VERSION 5.8 ;
BUSBITCHARS "[]" ;
DIVIDERCHAR "/" ;
UNITS
    DATABASE MICRONS 1000 ;
END UNITS

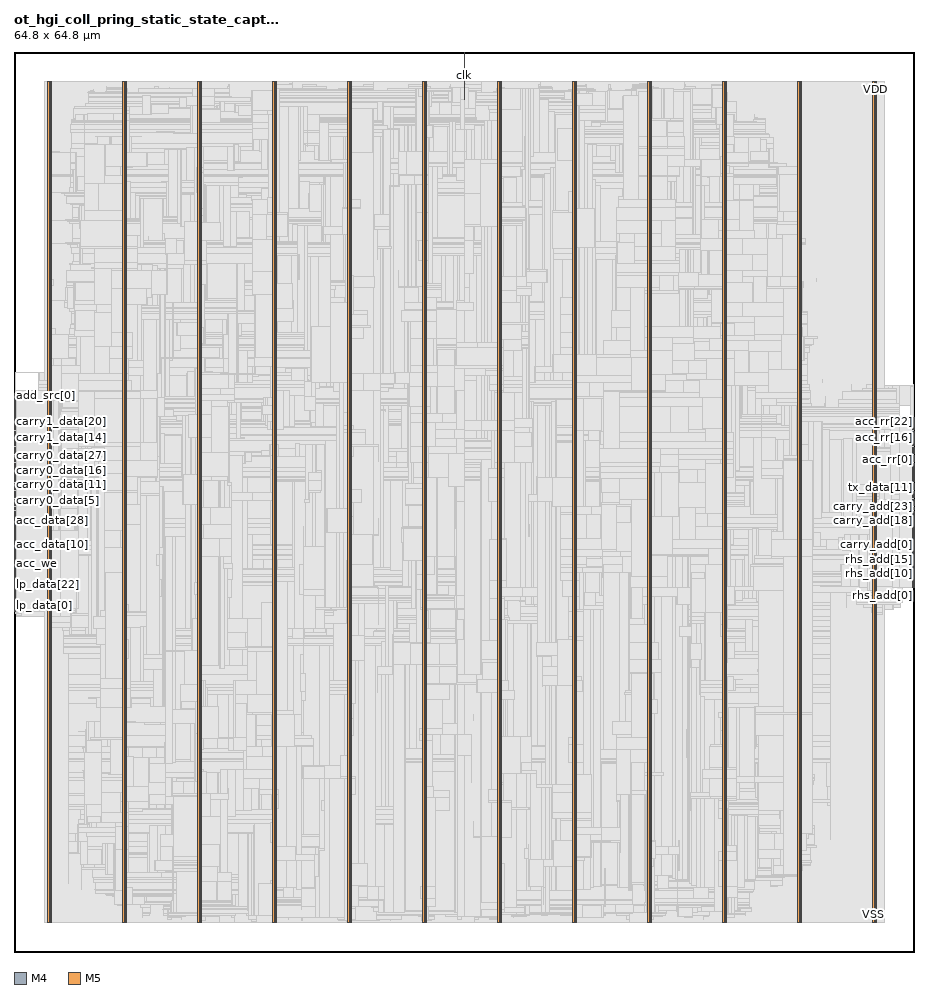
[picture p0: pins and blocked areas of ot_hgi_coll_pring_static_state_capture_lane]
MACRO ot_hgi_coll_pring_static_state_capture_lane
  FOREIGN ot_hgi_coll_pring_static_state_capture_lane 0 0 ;
  CLASS BLOCK ;
  SIZE 64.8 BY 64.8 ;
  PIN acc_data[0]
    DIRECTION INPUT ;
    USE SIGNAL ;
    PORT
      LAYER M4 ;
        RECT  0 28.368 0.084 28.392 ;
    END
  END acc_data[0]
  PIN acc_data[10]
    DIRECTION INPUT ;
    USE SIGNAL ;
    PORT
      LAYER M4 ;
        RECT  0 29.328 0.084 29.352 ;
    END
  END acc_data[10]
  PIN acc_data[11]
    DIRECTION INPUT ;
    USE SIGNAL ;
    PORT
      LAYER M4 ;
        RECT  0 29.424 0.084 29.448 ;
    END
  END acc_data[11]
  PIN acc_data[12]
    DIRECTION INPUT ;
    USE SIGNAL ;
    PORT
      LAYER M4 ;
        RECT  0 29.52 0.084 29.544 ;
    END
  END acc_data[12]
  PIN acc_data[13]
    DIRECTION INPUT ;
    USE SIGNAL ;
    PORT
      LAYER M4 ;
        RECT  0 29.616 0.084 29.64 ;
    END
  END acc_data[13]
  PIN acc_data[14]
    DIRECTION INPUT ;
    USE SIGNAL ;
    PORT
      LAYER M4 ;
        RECT  0 29.712 0.084 29.736 ;
    END
  END acc_data[14]
  PIN acc_data[15]
    DIRECTION INPUT ;
    USE SIGNAL ;
    PORT
      LAYER M4 ;
        RECT  0 29.808 0.084 29.832 ;
    END
  END acc_data[15]
  PIN acc_data[16]
    DIRECTION INPUT ;
    USE SIGNAL ;
    PORT
      LAYER M4 ;
        RECT  0 29.904 0.084 29.928 ;
    END
  END acc_data[16]
  PIN acc_data[17]
    DIRECTION INPUT ;
    USE SIGNAL ;
    PORT
      LAYER M4 ;
        RECT  0 30 0.084 30.024 ;
    END
  END acc_data[17]
  PIN acc_data[18]
    DIRECTION INPUT ;
    USE SIGNAL ;
    PORT
      LAYER M4 ;
        RECT  0 30.096 0.084 30.12 ;
    END
  END acc_data[18]
  PIN acc_data[19]
    DIRECTION INPUT ;
    USE SIGNAL ;
    PORT
      LAYER M4 ;
        RECT  0 30.192 0.084 30.216 ;
    END
  END acc_data[19]
  PIN acc_data[1]
    DIRECTION INPUT ;
    USE SIGNAL ;
    PORT
      LAYER M4 ;
        RECT  0 28.464 0.084 28.488 ;
    END
  END acc_data[1]
  PIN acc_data[20]
    DIRECTION INPUT ;
    USE SIGNAL ;
    PORT
      LAYER M4 ;
        RECT  0 30.288 0.084 30.312 ;
    END
  END acc_data[20]
  PIN acc_data[21]
    DIRECTION INPUT ;
    USE SIGNAL ;
    PORT
      LAYER M4 ;
        RECT  0 30.384 0.084 30.408 ;
    END
  END acc_data[21]
  PIN acc_data[22]
    DIRECTION INPUT ;
    USE SIGNAL ;
    PORT
      LAYER M4 ;
        RECT  0 30.48 0.084 30.504 ;
    END
  END acc_data[22]
  PIN acc_data[23]
    DIRECTION INPUT ;
    USE SIGNAL ;
    PORT
      LAYER M4 ;
        RECT  0 30.576 0.084 30.6 ;
    END
  END acc_data[23]
  PIN acc_data[24]
    DIRECTION INPUT ;
    USE SIGNAL ;
    PORT
      LAYER M4 ;
        RECT  0 30.672 0.084 30.696 ;
    END
  END acc_data[24]
  PIN acc_data[25]
    DIRECTION INPUT ;
    USE SIGNAL ;
    PORT
      LAYER M4 ;
        RECT  0 30.768 0.084 30.792 ;
    END
  END acc_data[25]
  PIN acc_data[26]
    DIRECTION INPUT ;
    USE SIGNAL ;
    PORT
      LAYER M4 ;
        RECT  0 30.864 0.084 30.888 ;
    END
  END acc_data[26]
  PIN acc_data[27]
    DIRECTION INPUT ;
    USE SIGNAL ;
    PORT
      LAYER M4 ;
        RECT  0 30.96 0.084 30.984 ;
    END
  END acc_data[27]
  PIN acc_data[28]
    DIRECTION INPUT ;
    USE SIGNAL ;
    PORT
      LAYER M4 ;
        RECT  0 31.056 0.084 31.08 ;
    END
  END acc_data[28]
  PIN acc_data[29]
    DIRECTION INPUT ;
    USE SIGNAL ;
    PORT
      LAYER M4 ;
        RECT  0 31.152 0.084 31.176 ;
    END
  END acc_data[29]
  PIN acc_data[2]
    DIRECTION INPUT ;
    USE SIGNAL ;
    PORT
      LAYER M4 ;
        RECT  0 28.56 0.084 28.584 ;
    END
  END acc_data[2]
  PIN acc_data[30]
    DIRECTION INPUT ;
    USE SIGNAL ;
    PORT
      LAYER M4 ;
        RECT  0 31.248 0.084 31.272 ;
    END
  END acc_data[30]
  PIN acc_data[31]
    DIRECTION INPUT ;
    USE SIGNAL ;
    PORT
      LAYER M4 ;
        RECT  0 31.344 0.084 31.368 ;
    END
  END acc_data[31]
  PIN acc_data[3]
    DIRECTION INPUT ;
    USE SIGNAL ;
    PORT
      LAYER M4 ;
        RECT  0 28.656 0.084 28.68 ;
    END
  END acc_data[3]
  PIN acc_data[4]
    DIRECTION INPUT ;
    USE SIGNAL ;
    PORT
      LAYER M4 ;
        RECT  0 28.752 0.084 28.776 ;
    END
  END acc_data[4]
  PIN acc_data[5]
    DIRECTION INPUT ;
    USE SIGNAL ;
    PORT
      LAYER M4 ;
        RECT  0 28.848 0.084 28.872 ;
    END
  END acc_data[5]
  PIN acc_data[6]
    DIRECTION INPUT ;
    USE SIGNAL ;
    PORT
      LAYER M4 ;
        RECT  0 28.944 0.084 28.968 ;
    END
  END acc_data[6]
  PIN acc_data[7]
    DIRECTION INPUT ;
    USE SIGNAL ;
    PORT
      LAYER M4 ;
        RECT  0 29.04 0.084 29.064 ;
    END
  END acc_data[7]
  PIN acc_data[8]
    DIRECTION INPUT ;
    USE SIGNAL ;
    PORT
      LAYER M4 ;
        RECT  0 29.136 0.084 29.16 ;
    END
  END acc_data[8]
  PIN acc_data[9]
    DIRECTION INPUT ;
    USE SIGNAL ;
    PORT
      LAYER M4 ;
        RECT  0 29.232 0.084 29.256 ;
    END
  END acc_data[9]
  PIN acc_rr[0]
    DIRECTION OUTPUT ;
    USE SIGNAL ;
    PORT
      LAYER M4 ;
        RECT  64.716 35.472 64.8 35.496 ;
    END
  END acc_rr[0]
  PIN acc_rr[10]
    DIRECTION OUTPUT ;
    USE SIGNAL ;
    PORT
      LAYER M4 ;
        RECT  64.716 36.432 64.8 36.456 ;
    END
  END acc_rr[10]
  PIN acc_rr[11]
    DIRECTION OUTPUT ;
    USE SIGNAL ;
    PORT
      LAYER M4 ;
        RECT  64.716 36.528 64.8 36.552 ;
    END
  END acc_rr[11]
  PIN acc_rr[12]
    DIRECTION OUTPUT ;
    USE SIGNAL ;
    PORT
      LAYER M4 ;
        RECT  64.716 36.624 64.8 36.648 ;
    END
  END acc_rr[12]
  PIN acc_rr[13]
    DIRECTION OUTPUT ;
    USE SIGNAL ;
    PORT
      LAYER M4 ;
        RECT  64.716 36.72 64.8 36.744 ;
    END
  END acc_rr[13]
  PIN acc_rr[14]
    DIRECTION OUTPUT ;
    USE SIGNAL ;
    PORT
      LAYER M4 ;
        RECT  64.716 36.816 64.8 36.84 ;
    END
  END acc_rr[14]
  PIN acc_rr[15]
    DIRECTION OUTPUT ;
    USE SIGNAL ;
    PORT
      LAYER M4 ;
        RECT  64.716 36.912 64.8 36.936 ;
    END
  END acc_rr[15]
  PIN acc_rr[16]
    DIRECTION OUTPUT ;
    USE SIGNAL ;
    PORT
      LAYER M4 ;
        RECT  64.716 37.008 64.8 37.032 ;
    END
  END acc_rr[16]
  PIN acc_rr[17]
    DIRECTION OUTPUT ;
    USE SIGNAL ;
    PORT
      LAYER M4 ;
        RECT  64.716 37.104 64.8 37.128 ;
    END
  END acc_rr[17]
  PIN acc_rr[18]
    DIRECTION OUTPUT ;
    USE SIGNAL ;
    PORT
      LAYER M4 ;
        RECT  64.716 37.2 64.8 37.224 ;
    END
  END acc_rr[18]
  PIN acc_rr[19]
    DIRECTION OUTPUT ;
    USE SIGNAL ;
    PORT
      LAYER M4 ;
        RECT  64.716 37.296 64.8 37.32 ;
    END
  END acc_rr[19]
  PIN acc_rr[1]
    DIRECTION OUTPUT ;
    USE SIGNAL ;
    PORT
      LAYER M4 ;
        RECT  64.716 35.568 64.8 35.592 ;
    END
  END acc_rr[1]
  PIN acc_rr[20]
    DIRECTION OUTPUT ;
    USE SIGNAL ;
    PORT
      LAYER M4 ;
        RECT  64.716 37.392 64.8 37.416 ;
    END
  END acc_rr[20]
  PIN acc_rr[21]
    DIRECTION OUTPUT ;
    USE SIGNAL ;
    PORT
      LAYER M4 ;
        RECT  64.716 37.488 64.8 37.512 ;
    END
  END acc_rr[21]
  PIN acc_rr[22]
    DIRECTION OUTPUT ;
    USE SIGNAL ;
    PORT
      LAYER M4 ;
        RECT  64.716 37.584 64.8 37.608 ;
    END
  END acc_rr[22]
  PIN acc_rr[23]
    DIRECTION OUTPUT ;
    USE SIGNAL ;
    PORT
      LAYER M4 ;
        RECT  64.716 37.68 64.8 37.704 ;
    END
  END acc_rr[23]
  PIN acc_rr[24]
    DIRECTION OUTPUT ;
    USE SIGNAL ;
    PORT
      LAYER M4 ;
        RECT  64.716 37.776 64.8 37.8 ;
    END
  END acc_rr[24]
  PIN acc_rr[25]
    DIRECTION OUTPUT ;
    USE SIGNAL ;
    PORT
      LAYER M4 ;
        RECT  64.716 37.872 64.8 37.896 ;
    END
  END acc_rr[25]
  PIN acc_rr[26]
    DIRECTION OUTPUT ;
    USE SIGNAL ;
    PORT
      LAYER M4 ;
        RECT  64.716 37.968 64.8 37.992 ;
    END
  END acc_rr[26]
  PIN acc_rr[27]
    DIRECTION OUTPUT ;
    USE SIGNAL ;
    PORT
      LAYER M4 ;
        RECT  64.716 38.064 64.8 38.088 ;
    END
  END acc_rr[27]
  PIN acc_rr[28]
    DIRECTION OUTPUT ;
    USE SIGNAL ;
    PORT
      LAYER M4 ;
        RECT  64.716 38.16 64.8 38.184 ;
    END
  END acc_rr[28]
  PIN acc_rr[29]
    DIRECTION OUTPUT ;
    USE SIGNAL ;
    PORT
      LAYER M4 ;
        RECT  64.716 38.256 64.8 38.28 ;
    END
  END acc_rr[29]
  PIN acc_rr[2]
    DIRECTION OUTPUT ;
    USE SIGNAL ;
    PORT
      LAYER M4 ;
        RECT  64.716 35.664 64.8 35.688 ;
    END
  END acc_rr[2]
  PIN acc_rr[30]
    DIRECTION OUTPUT ;
    USE SIGNAL ;
    PORT
      LAYER M4 ;
        RECT  64.716 38.352 64.8 38.376 ;
    END
  END acc_rr[30]
  PIN acc_rr[31]
    DIRECTION OUTPUT ;
    USE SIGNAL ;
    PORT
      LAYER M4 ;
        RECT  64.716 38.448 64.8 38.472 ;
    END
  END acc_rr[31]
  PIN acc_rr[3]
    DIRECTION OUTPUT ;
    USE SIGNAL ;
    PORT
      LAYER M4 ;
        RECT  64.716 35.76 64.8 35.784 ;
    END
  END acc_rr[3]
  PIN acc_rr[4]
    DIRECTION OUTPUT ;
    USE SIGNAL ;
    PORT
      LAYER M4 ;
        RECT  64.716 35.856 64.8 35.88 ;
    END
  END acc_rr[4]
  PIN acc_rr[5]
    DIRECTION OUTPUT ;
    USE SIGNAL ;
    PORT
      LAYER M4 ;
        RECT  64.716 35.952 64.8 35.976 ;
    END
  END acc_rr[5]
  PIN acc_rr[6]
    DIRECTION OUTPUT ;
    USE SIGNAL ;
    PORT
      LAYER M4 ;
        RECT  64.716 36.048 64.8 36.072 ;
    END
  END acc_rr[6]
  PIN acc_rr[7]
    DIRECTION OUTPUT ;
    USE SIGNAL ;
    PORT
      LAYER M4 ;
        RECT  64.716 36.144 64.8 36.168 ;
    END
  END acc_rr[7]
  PIN acc_rr[8]
    DIRECTION OUTPUT ;
    USE SIGNAL ;
    PORT
      LAYER M4 ;
        RECT  64.716 36.24 64.8 36.264 ;
    END
  END acc_rr[8]
  PIN acc_rr[9]
    DIRECTION OUTPUT ;
    USE SIGNAL ;
    PORT
      LAYER M4 ;
        RECT  64.716 36.336 64.8 36.36 ;
    END
  END acc_rr[9]
  PIN acc_tag[0]
    DIRECTION INPUT ;
    USE SIGNAL ;
    PORT
      LAYER M4 ;
        RECT  0 28.08 0.084 28.104 ;
    END
  END acc_tag[0]
  PIN acc_tag[1]
    DIRECTION INPUT ;
    USE SIGNAL ;
    PORT
      LAYER M4 ;
        RECT  0 28.176 0.084 28.2 ;
    END
  END acc_tag[1]
  PIN acc_tag[2]
    DIRECTION INPUT ;
    USE SIGNAL ;
    PORT
      LAYER M4 ;
        RECT  0 28.272 0.084 28.296 ;
    END
  END acc_tag[2]
  PIN acc_we
    DIRECTION INPUT ;
    USE SIGNAL ;
    PORT
      LAYER M4 ;
        RECT  0 27.984 0.084 28.008 ;
    END
  END acc_we
  PIN add_src[0]
    DIRECTION INPUT ;
    USE SIGNAL ;
    PORT
      LAYER M4 ;
        RECT  0 40.08 0.084 40.104 ;
    END
  END add_src[0]
  PIN add_src[1]
    DIRECTION INPUT ;
    USE SIGNAL ;
    PORT
      LAYER M4 ;
        RECT  0 40.176 0.084 40.2 ;
    END
  END add_src[1]
  PIN add_tag[0]
    DIRECTION INPUT ;
    USE SIGNAL ;
    PORT
      LAYER M4 ;
        RECT  0 39.216 0.084 39.24 ;
    END
  END add_tag[0]
  PIN add_tag[1]
    DIRECTION INPUT ;
    USE SIGNAL ;
    PORT
      LAYER M4 ;
        RECT  0 39.312 0.084 39.336 ;
    END
  END add_tag[1]
  PIN add_tag[2]
    DIRECTION INPUT ;
    USE SIGNAL ;
    PORT
      LAYER M4 ;
        RECT  0 39.408 0.084 39.432 ;
    END
  END add_tag[2]
  PIN carry0_data[0]
    DIRECTION INPUT ;
    USE SIGNAL ;
    PORT
      LAYER M4 ;
        RECT  0 32.592 0.084 32.616 ;
    END
  END carry0_data[0]
  PIN carry0_data[10]
    DIRECTION INPUT ;
    USE SIGNAL ;
    PORT
      LAYER M4 ;
        RECT  0 33.552 0.084 33.576 ;
    END
  END carry0_data[10]
  PIN carry0_data[11]
    DIRECTION INPUT ;
    USE SIGNAL ;
    PORT
      LAYER M4 ;
        RECT  0 33.648 0.084 33.672 ;
    END
  END carry0_data[11]
  PIN carry0_data[12]
    DIRECTION INPUT ;
    USE SIGNAL ;
    PORT
      LAYER M4 ;
        RECT  0 33.744 0.084 33.768 ;
    END
  END carry0_data[12]
  PIN carry0_data[13]
    DIRECTION INPUT ;
    USE SIGNAL ;
    PORT
      LAYER M4 ;
        RECT  0 33.84 0.084 33.864 ;
    END
  END carry0_data[13]
  PIN carry0_data[14]
    DIRECTION INPUT ;
    USE SIGNAL ;
    PORT
      LAYER M4 ;
        RECT  0 33.936 0.084 33.96 ;
    END
  END carry0_data[14]
  PIN carry0_data[15]
    DIRECTION INPUT ;
    USE SIGNAL ;
    PORT
      LAYER M4 ;
        RECT  0 34.032 0.084 34.056 ;
    END
  END carry0_data[15]
  PIN carry0_data[16]
    DIRECTION INPUT ;
    USE SIGNAL ;
    PORT
      LAYER M4 ;
        RECT  0 34.128 0.084 34.152 ;
    END
  END carry0_data[16]
  PIN carry0_data[17]
    DIRECTION INPUT ;
    USE SIGNAL ;
    PORT
      LAYER M4 ;
        RECT  0 34.224 0.084 34.248 ;
    END
  END carry0_data[17]
  PIN carry0_data[18]
    DIRECTION INPUT ;
    USE SIGNAL ;
    PORT
      LAYER M4 ;
        RECT  0 34.32 0.084 34.344 ;
    END
  END carry0_data[18]
  PIN carry0_data[19]
    DIRECTION INPUT ;
    USE SIGNAL ;
    PORT
      LAYER M4 ;
        RECT  0 34.416 0.084 34.44 ;
    END
  END carry0_data[19]
  PIN carry0_data[1]
    DIRECTION INPUT ;
    USE SIGNAL ;
    PORT
      LAYER M4 ;
        RECT  0 32.688 0.084 32.712 ;
    END
  END carry0_data[1]
  PIN carry0_data[20]
    DIRECTION INPUT ;
    USE SIGNAL ;
    PORT
      LAYER M4 ;
        RECT  0 34.512 0.084 34.536 ;
    END
  END carry0_data[20]
  PIN carry0_data[21]
    DIRECTION INPUT ;
    USE SIGNAL ;
    PORT
      LAYER M4 ;
        RECT  0 34.608 0.084 34.632 ;
    END
  END carry0_data[21]
  PIN carry0_data[22]
    DIRECTION INPUT ;
    USE SIGNAL ;
    PORT
      LAYER M4 ;
        RECT  0 34.704 0.084 34.728 ;
    END
  END carry0_data[22]
  PIN carry0_data[23]
    DIRECTION INPUT ;
    USE SIGNAL ;
    PORT
      LAYER M4 ;
        RECT  0 34.8 0.084 34.824 ;
    END
  END carry0_data[23]
  PIN carry0_data[24]
    DIRECTION INPUT ;
    USE SIGNAL ;
    PORT
      LAYER M4 ;
        RECT  0 34.896 0.084 34.92 ;
    END
  END carry0_data[24]
  PIN carry0_data[25]
    DIRECTION INPUT ;
    USE SIGNAL ;
    PORT
      LAYER M4 ;
        RECT  0 34.992 0.084 35.016 ;
    END
  END carry0_data[25]
  PIN carry0_data[26]
    DIRECTION INPUT ;
    USE SIGNAL ;
    PORT
      LAYER M4 ;
        RECT  0 35.088 0.084 35.112 ;
    END
  END carry0_data[26]
  PIN carry0_data[27]
    DIRECTION INPUT ;
    USE SIGNAL ;
    PORT
      LAYER M4 ;
        RECT  0 35.184 0.084 35.208 ;
    END
  END carry0_data[27]
  PIN carry0_data[28]
    DIRECTION INPUT ;
    USE SIGNAL ;
    PORT
      LAYER M4 ;
        RECT  0 35.28 0.084 35.304 ;
    END
  END carry0_data[28]
  PIN carry0_data[29]
    DIRECTION INPUT ;
    USE SIGNAL ;
    PORT
      LAYER M4 ;
        RECT  0 35.376 0.084 35.4 ;
    END
  END carry0_data[29]
  PIN carry0_data[2]
    DIRECTION INPUT ;
    USE SIGNAL ;
    PORT
      LAYER M4 ;
        RECT  0 32.784 0.084 32.808 ;
    END
  END carry0_data[2]
  PIN carry0_data[30]
    DIRECTION INPUT ;
    USE SIGNAL ;
    PORT
      LAYER M4 ;
        RECT  0 35.472 0.084 35.496 ;
    END
  END carry0_data[30]
  PIN carry0_data[31]
    DIRECTION INPUT ;
    USE SIGNAL ;
    PORT
      LAYER M4 ;
        RECT  0 35.568 0.084 35.592 ;
    END
  END carry0_data[31]
  PIN carry0_data[3]
    DIRECTION INPUT ;
    USE SIGNAL ;
    PORT
      LAYER M4 ;
        RECT  0 32.88 0.084 32.904 ;
    END
  END carry0_data[3]
  PIN carry0_data[4]
    DIRECTION INPUT ;
    USE SIGNAL ;
    PORT
      LAYER M4 ;
        RECT  0 32.976 0.084 33 ;
    END
  END carry0_data[4]
  PIN carry0_data[5]
    DIRECTION INPUT ;
    USE SIGNAL ;
    PORT
      LAYER M4 ;
        RECT  0 33.072 0.084 33.096 ;
    END
  END carry0_data[5]
  PIN carry0_data[6]
    DIRECTION INPUT ;
    USE SIGNAL ;
    PORT
      LAYER M4 ;
        RECT  0 33.168 0.084 33.192 ;
    END
  END carry0_data[6]
  PIN carry0_data[7]
    DIRECTION INPUT ;
    USE SIGNAL ;
    PORT
      LAYER M4 ;
        RECT  0 33.264 0.084 33.288 ;
    END
  END carry0_data[7]
  PIN carry0_data[8]
    DIRECTION INPUT ;
    USE SIGNAL ;
    PORT
      LAYER M4 ;
        RECT  0 33.36 0.084 33.384 ;
    END
  END carry0_data[8]
  PIN carry0_data[9]
    DIRECTION INPUT ;
    USE SIGNAL ;
    PORT
      LAYER M4 ;
        RECT  0 33.456 0.084 33.48 ;
    END
  END carry0_data[9]
  PIN carry0_src[0]
    DIRECTION INPUT ;
    USE SIGNAL ;
    PORT
      LAYER M4 ;
        RECT  0 32.208 0.084 32.232 ;
    END
  END carry0_src[0]
  PIN carry0_src[1]
    DIRECTION INPUT ;
    USE SIGNAL ;
    PORT
      LAYER M4 ;
        RECT  0 32.304 0.084 32.328 ;
    END
  END carry0_src[1]
  PIN carry0_tag[0]
    DIRECTION INPUT ;
    USE SIGNAL ;
    PORT
      LAYER M4 ;
        RECT  0 31.632 0.084 31.656 ;
    END
  END carry0_tag[0]
  PIN carry0_tag[1]
    DIRECTION INPUT ;
    USE SIGNAL ;
    PORT
      LAYER M4 ;
        RECT  0 31.728 0.084 31.752 ;
    END
  END carry0_tag[1]
  PIN carry0_tag[2]
    DIRECTION INPUT ;
    USE SIGNAL ;
    PORT
      LAYER M4 ;
        RECT  0 31.824 0.084 31.848 ;
    END
  END carry0_tag[2]
  PIN carry1_data[0]
    DIRECTION INPUT ;
    USE SIGNAL ;
    PORT
      LAYER M4 ;
        RECT  0 35.664 0.084 35.688 ;
    END
  END carry1_data[0]
  PIN carry1_data[10]
    DIRECTION INPUT ;
    USE SIGNAL ;
    PORT
      LAYER M4 ;
        RECT  0 36.624 0.084 36.648 ;
    END
  END carry1_data[10]
  PIN carry1_data[11]
    DIRECTION INPUT ;
    USE SIGNAL ;
    PORT
      LAYER M4 ;
        RECT  0 36.72 0.084 36.744 ;
    END
  END carry1_data[11]
  PIN carry1_data[12]
    DIRECTION INPUT ;
    USE SIGNAL ;
    PORT
      LAYER M4 ;
        RECT  0 36.816 0.084 36.84 ;
    END
  END carry1_data[12]
  PIN carry1_data[13]
    DIRECTION INPUT ;
    USE SIGNAL ;
    PORT
      LAYER M4 ;
        RECT  0 36.912 0.084 36.936 ;
    END
  END carry1_data[13]
  PIN carry1_data[14]
    DIRECTION INPUT ;
    USE SIGNAL ;
    PORT
      LAYER M4 ;
        RECT  0 37.008 0.084 37.032 ;
    END
  END carry1_data[14]
  PIN carry1_data[15]
    DIRECTION INPUT ;
    USE SIGNAL ;
    PORT
      LAYER M4 ;
        RECT  0 37.104 0.084 37.128 ;
    END
  END carry1_data[15]
  PIN carry1_data[16]
    DIRECTION INPUT ;
    USE SIGNAL ;
    PORT
      LAYER M4 ;
        RECT  0 37.2 0.084 37.224 ;
    END
  END carry1_data[16]
  PIN carry1_data[17]
    DIRECTION INPUT ;
    USE SIGNAL ;
    PORT
      LAYER M4 ;
        RECT  0 37.296 0.084 37.32 ;
    END
  END carry1_data[17]
  PIN carry1_data[18]
    DIRECTION INPUT ;
    USE SIGNAL ;
    PORT
      LAYER M4 ;
        RECT  0 37.392 0.084 37.416 ;
    END
  END carry1_data[18]
  PIN carry1_data[19]
    DIRECTION INPUT ;
    USE SIGNAL ;
    PORT
      LAYER M4 ;
        RECT  0 37.488 0.084 37.512 ;
    END
  END carry1_data[19]
  PIN carry1_data[1]
    DIRECTION INPUT ;
    USE SIGNAL ;
    PORT
      LAYER M4 ;
        RECT  0 35.76 0.084 35.784 ;
    END
  END carry1_data[1]
  PIN carry1_data[20]
    DIRECTION INPUT ;
    USE SIGNAL ;
    PORT
      LAYER M4 ;
        RECT  0 37.584 0.084 37.608 ;
    END
  END carry1_data[20]
  PIN carry1_data[21]
    DIRECTION INPUT ;
    USE SIGNAL ;
    PORT
      LAYER M4 ;
        RECT  0 37.68 0.084 37.704 ;
    END
  END carry1_data[21]
  PIN carry1_data[22]
    DIRECTION INPUT ;
    USE SIGNAL ;
    PORT
      LAYER M4 ;
        RECT  0 37.776 0.084 37.8 ;
    END
  END carry1_data[22]
  PIN carry1_data[23]
    DIRECTION INPUT ;
    USE SIGNAL ;
    PORT
      LAYER M4 ;
        RECT  0 37.872 0.084 37.896 ;
    END
  END carry1_data[23]
  PIN carry1_data[24]
    DIRECTION INPUT ;
    USE SIGNAL ;
    PORT
      LAYER M4 ;
        RECT  0 37.968 0.084 37.992 ;
    END
  END carry1_data[24]
  PIN carry1_data[25]
    DIRECTION INPUT ;
    USE SIGNAL ;
    PORT
      LAYER M4 ;
        RECT  0 38.064 0.084 38.088 ;
    END
  END carry1_data[25]
  PIN carry1_data[26]
    DIRECTION INPUT ;
    USE SIGNAL ;
    PORT
      LAYER M4 ;
        RECT  0 38.16 0.084 38.184 ;
    END
  END carry1_data[26]
  PIN carry1_data[27]
    DIRECTION INPUT ;
    USE SIGNAL ;
    PORT
      LAYER M4 ;
        RECT  0 38.256 0.084 38.28 ;
    END
  END carry1_data[27]
  PIN carry1_data[28]
    DIRECTION INPUT ;
    USE SIGNAL ;
    PORT
      LAYER M4 ;
        RECT  0 38.352 0.084 38.376 ;
    END
  END carry1_data[28]
  PIN carry1_data[29]
    DIRECTION INPUT ;
    USE SIGNAL ;
    PORT
      LAYER M4 ;
        RECT  0 38.448 0.084 38.472 ;
    END
  END carry1_data[29]
  PIN carry1_data[2]
    DIRECTION INPUT ;
    USE SIGNAL ;
    PORT
      LAYER M4 ;
        RECT  0 35.856 0.084 35.88 ;
    END
  END carry1_data[2]
  PIN carry1_data[30]
    DIRECTION INPUT ;
    USE SIGNAL ;
    PORT
      LAYER M4 ;
        RECT  0 38.544 0.084 38.568 ;
    END
  END carry1_data[30]
  PIN carry1_data[31]
    DIRECTION INPUT ;
    USE SIGNAL ;
    PORT
      LAYER M4 ;
        RECT  0 38.64 0.084 38.664 ;
    END
  END carry1_data[31]
  PIN carry1_data[3]
    DIRECTION INPUT ;
    USE SIGNAL ;
    PORT
      LAYER M4 ;
        RECT  0 35.952 0.084 35.976 ;
    END
  END carry1_data[3]
  PIN carry1_data[4]
    DIRECTION INPUT ;
    USE SIGNAL ;
    PORT
      LAYER M4 ;
        RECT  0 36.048 0.084 36.072 ;
    END
  END carry1_data[4]
  PIN carry1_data[5]
    DIRECTION INPUT ;
    USE SIGNAL ;
    PORT
      LAYER M4 ;
        RECT  0 36.144 0.084 36.168 ;
    END
  END carry1_data[5]
  PIN carry1_data[6]
    DIRECTION INPUT ;
    USE SIGNAL ;
    PORT
      LAYER M4 ;
        RECT  0 36.24 0.084 36.264 ;
    END
  END carry1_data[6]
  PIN carry1_data[7]
    DIRECTION INPUT ;
    USE SIGNAL ;
    PORT
      LAYER M4 ;
        RECT  0 36.336 0.084 36.36 ;
    END
  END carry1_data[7]
  PIN carry1_data[8]
    DIRECTION INPUT ;
    USE SIGNAL ;
    PORT
      LAYER M4 ;
        RECT  0 36.432 0.084 36.456 ;
    END
  END carry1_data[8]
  PIN carry1_data[9]
    DIRECTION INPUT ;
    USE SIGNAL ;
    PORT
      LAYER M4 ;
        RECT  0 36.528 0.084 36.552 ;
    END
  END carry1_data[9]
  PIN carry1_src[0]
    DIRECTION INPUT ;
    USE SIGNAL ;
    PORT
      LAYER M4 ;
        RECT  0 32.4 0.084 32.424 ;
    END
  END carry1_src[0]
  PIN carry1_src[1]
    DIRECTION INPUT ;
    USE SIGNAL ;
    PORT
      LAYER M4 ;
        RECT  0 32.496 0.084 32.52 ;
    END
  END carry1_src[1]
  PIN carry1_tag[0]
    DIRECTION INPUT ;
    USE SIGNAL ;
    PORT
      LAYER M4 ;
        RECT  0 31.92 0.084 31.944 ;
    END
  END carry1_tag[0]
  PIN carry1_tag[1]
    DIRECTION INPUT ;
    USE SIGNAL ;
    PORT
      LAYER M4 ;
        RECT  0 32.016 0.084 32.04 ;
    END
  END carry1_tag[1]
  PIN carry1_tag[2]
    DIRECTION INPUT ;
    USE SIGNAL ;
    PORT
      LAYER M4 ;
        RECT  0 32.112 0.084 32.136 ;
    END
  END carry1_tag[2]
  PIN carry_add[0]
    DIRECTION OUTPUT ;
    USE SIGNAL ;
    PORT
      LAYER M4 ;
        RECT  64.716 29.328 64.8 29.352 ;
    END
  END carry_add[0]
  PIN carry_add[10]
    DIRECTION OUTPUT ;
    USE SIGNAL ;
    PORT
      LAYER M4 ;
        RECT  64.716 30.288 64.8 30.312 ;
    END
  END carry_add[10]
  PIN carry_add[11]
    DIRECTION OUTPUT ;
    USE SIGNAL ;
    PORT
      LAYER M4 ;
        RECT  64.716 30.384 64.8 30.408 ;
    END
  END carry_add[11]
  PIN carry_add[12]
    DIRECTION OUTPUT ;
    USE SIGNAL ;
    PORT
      LAYER M4 ;
        RECT  64.716 30.48 64.8 30.504 ;
    END
  END carry_add[12]
  PIN carry_add[13]
    DIRECTION OUTPUT ;
    USE SIGNAL ;
    PORT
      LAYER M4 ;
        RECT  64.716 30.576 64.8 30.6 ;
    END
  END carry_add[13]
  PIN carry_add[14]
    DIRECTION OUTPUT ;
    USE SIGNAL ;
    PORT
      LAYER M4 ;
        RECT  64.716 30.672 64.8 30.696 ;
    END
  END carry_add[14]
  PIN carry_add[15]
    DIRECTION OUTPUT ;
    USE SIGNAL ;
    PORT
      LAYER M4 ;
        RECT  64.716 30.768 64.8 30.792 ;
    END
  END carry_add[15]
  PIN carry_add[16]
    DIRECTION OUTPUT ;
    USE SIGNAL ;
    PORT
      LAYER M4 ;
        RECT  64.716 30.864 64.8 30.888 ;
    END
  END carry_add[16]
  PIN carry_add[17]
    DIRECTION OUTPUT ;
    USE SIGNAL ;
    PORT
      LAYER M4 ;
        RECT  64.716 30.96 64.8 30.984 ;
    END
  END carry_add[17]
  PIN carry_add[18]
    DIRECTION OUTPUT ;
    USE SIGNAL ;
    PORT
      LAYER M4 ;
        RECT  64.716 31.056 64.8 31.08 ;
    END
  END carry_add[18]
  PIN carry_add[19]
    DIRECTION OUTPUT ;
    USE SIGNAL ;
    PORT
      LAYER M4 ;
        RECT  64.716 31.152 64.8 31.176 ;
    END
  END carry_add[19]
  PIN carry_add[1]
    DIRECTION OUTPUT ;
    USE SIGNAL ;
    PORT
      LAYER M4 ;
        RECT  64.716 29.424 64.8 29.448 ;
    END
  END carry_add[1]
  PIN carry_add[20]
    DIRECTION OUTPUT ;
    USE SIGNAL ;
    PORT
      LAYER M4 ;
        RECT  64.716 31.248 64.8 31.272 ;
    END
  END carry_add[20]
  PIN carry_add[21]
    DIRECTION OUTPUT ;
    USE SIGNAL ;
    PORT
      LAYER M4 ;
        RECT  64.716 31.344 64.8 31.368 ;
    END
  END carry_add[21]
  PIN carry_add[22]
    DIRECTION OUTPUT ;
    USE SIGNAL ;
    PORT
      LAYER M4 ;
        RECT  64.716 31.44 64.8 31.464 ;
    END
  END carry_add[22]
  PIN carry_add[23]
    DIRECTION OUTPUT ;
    USE SIGNAL ;
    PORT
      LAYER M4 ;
        RECT  64.716 31.536 64.8 31.56 ;
    END
  END carry_add[23]
  PIN carry_add[24]
    DIRECTION OUTPUT ;
    USE SIGNAL ;
    PORT
      LAYER M4 ;
        RECT  64.716 31.632 64.8 31.656 ;
    END
  END carry_add[24]
  PIN carry_add[25]
    DIRECTION OUTPUT ;
    USE SIGNAL ;
    PORT
      LAYER M4 ;
        RECT  64.716 31.728 64.8 31.752 ;
    END
  END carry_add[25]
  PIN carry_add[26]
    DIRECTION OUTPUT ;
    USE SIGNAL ;
    PORT
      LAYER M4 ;
        RECT  64.716 31.824 64.8 31.848 ;
    END
  END carry_add[26]
  PIN carry_add[27]
    DIRECTION OUTPUT ;
    USE SIGNAL ;
    PORT
      LAYER M4 ;
        RECT  64.716 31.92 64.8 31.944 ;
    END
  END carry_add[27]
  PIN carry_add[28]
    DIRECTION OUTPUT ;
    USE SIGNAL ;
    PORT
      LAYER M4 ;
        RECT  64.716 32.016 64.8 32.04 ;
    END
  END carry_add[28]
  PIN carry_add[29]
    DIRECTION OUTPUT ;
    USE SIGNAL ;
    PORT
      LAYER M4 ;
        RECT  64.716 32.112 64.8 32.136 ;
    END
  END carry_add[29]
  PIN carry_add[2]
    DIRECTION OUTPUT ;
    USE SIGNAL ;
    PORT
      LAYER M4 ;
        RECT  64.716 29.52 64.8 29.544 ;
    END
  END carry_add[2]
  PIN carry_add[30]
    DIRECTION OUTPUT ;
    USE SIGNAL ;
    PORT
      LAYER M4 ;
        RECT  64.716 32.208 64.8 32.232 ;
    END
  END carry_add[30]
  PIN carry_add[31]
    DIRECTION OUTPUT ;
    USE SIGNAL ;
    PORT
      LAYER M4 ;
        RECT  64.716 32.304 64.8 32.328 ;
    END
  END carry_add[31]
  PIN carry_add[3]
    DIRECTION OUTPUT ;
    USE SIGNAL ;
    PORT
      LAYER M4 ;
        RECT  64.716 29.616 64.8 29.64 ;
    END
  END carry_add[3]
  PIN carry_add[4]
    DIRECTION OUTPUT ;
    USE SIGNAL ;
    PORT
      LAYER M4 ;
        RECT  64.716 29.712 64.8 29.736 ;
    END
  END carry_add[4]
  PIN carry_add[5]
    DIRECTION OUTPUT ;
    USE SIGNAL ;
    PORT
      LAYER M4 ;
        RECT  64.716 29.808 64.8 29.832 ;
    END
  END carry_add[5]
  PIN carry_add[6]
    DIRECTION OUTPUT ;
    USE SIGNAL ;
    PORT
      LAYER M4 ;
        RECT  64.716 29.904 64.8 29.928 ;
    END
  END carry_add[6]
  PIN carry_add[7]
    DIRECTION OUTPUT ;
    USE SIGNAL ;
    PORT
      LAYER M4 ;
        RECT  64.716 30 64.8 30.024 ;
    END
  END carry_add[7]
  PIN carry_add[8]
    DIRECTION OUTPUT ;
    USE SIGNAL ;
    PORT
      LAYER M4 ;
        RECT  64.716 30.096 64.8 30.12 ;
    END
  END carry_add[8]
  PIN carry_add[9]
    DIRECTION OUTPUT ;
    USE SIGNAL ;
    PORT
      LAYER M4 ;
        RECT  64.716 30.192 64.8 30.216 ;
    END
  END carry_add[9]
  PIN carry_we[0]
    DIRECTION INPUT ;
    USE SIGNAL ;
    PORT
      LAYER M4 ;
        RECT  0 31.44 0.084 31.464 ;
    END
  END carry_we[0]
  PIN carry_we[1]
    DIRECTION INPUT ;
    USE SIGNAL ;
    PORT
      LAYER M4 ;
        RECT  0 31.536 0.084 31.56 ;
    END
  END carry_we[1]
  PIN clk
    DIRECTION INPUT ;
    USE SIGNAL ;
    PORT
      LAYER M5 ;
        RECT  32.4 64.716 32.424 64.8 ;
    END
    PORT
      LAYER M5 ;
        RECT  32.4 61.379 32.424 64.784 ;
    END
  END clk
  PIN lp_data[0]
    DIRECTION INPUT ;
    USE SIGNAL ;
    PORT
      LAYER M4 ;
        RECT  0 24.912 0.084 24.936 ;
    END
  END lp_data[0]
  PIN lp_data[10]
    DIRECTION INPUT ;
    USE SIGNAL ;
    PORT
      LAYER M4 ;
        RECT  0 25.872 0.084 25.896 ;
    END
  END lp_data[10]
  PIN lp_data[11]
    DIRECTION INPUT ;
    USE SIGNAL ;
    PORT
      LAYER M4 ;
        RECT  0 25.968 0.084 25.992 ;
    END
  END lp_data[11]
  PIN lp_data[12]
    DIRECTION INPUT ;
    USE SIGNAL ;
    PORT
      LAYER M4 ;
        RECT  0 26.064 0.084 26.088 ;
    END
  END lp_data[12]
  PIN lp_data[13]
    DIRECTION INPUT ;
    USE SIGNAL ;
    PORT
      LAYER M4 ;
        RECT  0 26.16 0.084 26.184 ;
    END
  END lp_data[13]
  PIN lp_data[14]
    DIRECTION INPUT ;
    USE SIGNAL ;
    PORT
      LAYER M4 ;
        RECT  0 26.256 0.084 26.28 ;
    END
  END lp_data[14]
  PIN lp_data[15]
    DIRECTION INPUT ;
    USE SIGNAL ;
    PORT
      LAYER M4 ;
        RECT  0 26.352 0.084 26.376 ;
    END
  END lp_data[15]
  PIN lp_data[16]
    DIRECTION INPUT ;
    USE SIGNAL ;
    PORT
      LAYER M4 ;
        RECT  0 26.448 0.084 26.472 ;
    END
  END lp_data[16]
  PIN lp_data[17]
    DIRECTION INPUT ;
    USE SIGNAL ;
    PORT
      LAYER M4 ;
        RECT  0 26.544 0.084 26.568 ;
    END
  END lp_data[17]
  PIN lp_data[18]
    DIRECTION INPUT ;
    USE SIGNAL ;
    PORT
      LAYER M4 ;
        RECT  0 26.64 0.084 26.664 ;
    END
  END lp_data[18]
  PIN lp_data[19]
    DIRECTION INPUT ;
    USE SIGNAL ;
    PORT
      LAYER M4 ;
        RECT  0 26.736 0.084 26.76 ;
    END
  END lp_data[19]
  PIN lp_data[1]
    DIRECTION INPUT ;
    USE SIGNAL ;
    PORT
      LAYER M4 ;
        RECT  0 25.008 0.084 25.032 ;
    END
  END lp_data[1]
  PIN lp_data[20]
    DIRECTION INPUT ;
    USE SIGNAL ;
    PORT
      LAYER M4 ;
        RECT  0 26.832 0.084 26.856 ;
    END
  END lp_data[20]
  PIN lp_data[21]
    DIRECTION INPUT ;
    USE SIGNAL ;
    PORT
      LAYER M4 ;
        RECT  0 26.928 0.084 26.952 ;
    END
  END lp_data[21]
  PIN lp_data[22]
    DIRECTION INPUT ;
    USE SIGNAL ;
    PORT
      LAYER M4 ;
        RECT  0 27.024 0.084 27.048 ;
    END
  END lp_data[22]
  PIN lp_data[23]
    DIRECTION INPUT ;
    USE SIGNAL ;
    PORT
      LAYER M4 ;
        RECT  0 27.12 0.084 27.144 ;
    END
  END lp_data[23]
  PIN lp_data[24]
    DIRECTION INPUT ;
    USE SIGNAL ;
    PORT
      LAYER M4 ;
        RECT  0 27.216 0.084 27.24 ;
    END
  END lp_data[24]
  PIN lp_data[25]
    DIRECTION INPUT ;
    USE SIGNAL ;
    PORT
      LAYER M4 ;
        RECT  0 27.312 0.084 27.336 ;
    END
  END lp_data[25]
  PIN lp_data[26]
    DIRECTION INPUT ;
    USE SIGNAL ;
    PORT
      LAYER M4 ;
        RECT  0 27.408 0.084 27.432 ;
    END
  END lp_data[26]
  PIN lp_data[27]
    DIRECTION INPUT ;
    USE SIGNAL ;
    PORT
      LAYER M4 ;
        RECT  0 27.504 0.084 27.528 ;
    END
  END lp_data[27]
  PIN lp_data[28]
    DIRECTION INPUT ;
    USE SIGNAL ;
    PORT
      LAYER M4 ;
        RECT  0 27.6 0.084 27.624 ;
    END
  END lp_data[28]
  PIN lp_data[29]
    DIRECTION INPUT ;
    USE SIGNAL ;
    PORT
      LAYER M4 ;
        RECT  0 27.696 0.084 27.72 ;
    END
  END lp_data[29]
  PIN lp_data[2]
    DIRECTION INPUT ;
    USE SIGNAL ;
    PORT
      LAYER M4 ;
        RECT  0 25.104 0.084 25.128 ;
    END
  END lp_data[2]
  PIN lp_data[30]
    DIRECTION INPUT ;
    USE SIGNAL ;
    PORT
      LAYER M4 ;
        RECT  0 27.792 0.084 27.816 ;
    END
  END lp_data[30]
  PIN lp_data[31]
    DIRECTION INPUT ;
    USE SIGNAL ;
    PORT
      LAYER M4 ;
        RECT  0 27.888 0.084 27.912 ;
    END
  END lp_data[31]
  PIN lp_data[3]
    DIRECTION INPUT ;
    USE SIGNAL ;
    PORT
      LAYER M4 ;
        RECT  0 25.2 0.084 25.224 ;
    END
  END lp_data[3]
  PIN lp_data[4]
    DIRECTION INPUT ;
    USE SIGNAL ;
    PORT
      LAYER M4 ;
        RECT  0 25.296 0.084 25.32 ;
    END
  END lp_data[4]
  PIN lp_data[5]
    DIRECTION INPUT ;
    USE SIGNAL ;
    PORT
      LAYER M4 ;
        RECT  0 25.392 0.084 25.416 ;
    END
  END lp_data[5]
  PIN lp_data[6]
    DIRECTION INPUT ;
    USE SIGNAL ;
    PORT
      LAYER M4 ;
        RECT  0 25.488 0.084 25.512 ;
    END
  END lp_data[6]
  PIN lp_data[7]
    DIRECTION INPUT ;
    USE SIGNAL ;
    PORT
      LAYER M4 ;
        RECT  0 25.584 0.084 25.608 ;
    END
  END lp_data[7]
  PIN lp_data[8]
    DIRECTION INPUT ;
    USE SIGNAL ;
    PORT
      LAYER M4 ;
        RECT  0 25.68 0.084 25.704 ;
    END
  END lp_data[8]
  PIN lp_data[9]
    DIRECTION INPUT ;
    USE SIGNAL ;
    PORT
      LAYER M4 ;
        RECT  0 25.776 0.084 25.8 ;
    END
  END lp_data[9]
  PIN lp_tag[0]
    DIRECTION INPUT ;
    USE SIGNAL ;
    PORT
      LAYER M4 ;
        RECT  0 24.624 0.084 24.648 ;
    END
  END lp_tag[0]
  PIN lp_tag[1]
    DIRECTION INPUT ;
    USE SIGNAL ;
    PORT
      LAYER M4 ;
        RECT  0 24.72 0.084 24.744 ;
    END
  END lp_tag[1]
  PIN lp_tag[2]
    DIRECTION INPUT ;
    USE SIGNAL ;
    PORT
      LAYER M4 ;
        RECT  0 24.816 0.084 24.84 ;
    END
  END lp_tag[2]
  PIN lp_we
    DIRECTION INPUT ;
    USE SIGNAL ;
    PORT
      LAYER M4 ;
        RECT  0 24.528 0.084 24.552 ;
    END
  END lp_we
  PIN read_add
    DIRECTION INPUT ;
    USE SIGNAL ;
    PORT
      LAYER M4 ;
        RECT  0 38.736 0.084 38.76 ;
    END
  END read_add
  PIN read_rhs_acc
    DIRECTION INPUT ;
    USE SIGNAL ;
    PORT
      LAYER M4 ;
        RECT  0 39.024 0.084 39.048 ;
    END
  END read_rhs_acc
  PIN read_rr
    DIRECTION INPUT ;
    USE SIGNAL ;
    PORT
      LAYER M4 ;
        RECT  0 38.928 0.084 38.952 ;
    END
  END read_rr
  PIN read_tx
    DIRECTION INPUT ;
    USE SIGNAL ;
    PORT
      LAYER M4 ;
        RECT  0 38.832 0.084 38.856 ;
    END
  END read_tx
  PIN read_tx_acc
    DIRECTION INPUT ;
    USE SIGNAL ;
    PORT
      LAYER M4 ;
        RECT  0 39.12 0.084 39.144 ;
    END
  END read_tx_acc
  PIN rhs_add[0]
    DIRECTION OUTPUT ;
    USE SIGNAL ;
    PORT
      LAYER M4 ;
        RECT  64.716 26.256 64.8 26.28 ;
    END
  END rhs_add[0]
  PIN rhs_add[10]
    DIRECTION OUTPUT ;
    USE SIGNAL ;
    PORT
      LAYER M4 ;
        RECT  64.716 27.216 64.8 27.24 ;
    END
  END rhs_add[10]
  PIN rhs_add[11]
    DIRECTION OUTPUT ;
    USE SIGNAL ;
    PORT
      LAYER M4 ;
        RECT  64.716 27.312 64.8 27.336 ;
    END
  END rhs_add[11]
  PIN rhs_add[12]
    DIRECTION OUTPUT ;
    USE SIGNAL ;
    PORT
      LAYER M4 ;
        RECT  64.716 27.408 64.8 27.432 ;
    END
  END rhs_add[12]
  PIN rhs_add[13]
    DIRECTION OUTPUT ;
    USE SIGNAL ;
    PORT
      LAYER M4 ;
        RECT  64.716 27.504 64.8 27.528 ;
    END
  END rhs_add[13]
  PIN rhs_add[14]
    DIRECTION OUTPUT ;
    USE SIGNAL ;
    PORT
      LAYER M4 ;
        RECT  64.716 27.6 64.8 27.624 ;
    END
  END rhs_add[14]
  PIN rhs_add[15]
    DIRECTION OUTPUT ;
    USE SIGNAL ;
    PORT
      LAYER M4 ;
        RECT  64.716 27.696 64.8 27.72 ;
    END
  END rhs_add[15]
  PIN rhs_add[16]
    DIRECTION OUTPUT ;
    USE SIGNAL ;
    PORT
      LAYER M4 ;
        RECT  64.716 27.792 64.8 27.816 ;
    END
  END rhs_add[16]
  PIN rhs_add[17]
    DIRECTION OUTPUT ;
    USE SIGNAL ;
    PORT
      LAYER M4 ;
        RECT  64.716 27.888 64.8 27.912 ;
    END
  END rhs_add[17]
  PIN rhs_add[18]
    DIRECTION OUTPUT ;
    USE SIGNAL ;
    PORT
      LAYER M4 ;
        RECT  64.716 27.984 64.8 28.008 ;
    END
  END rhs_add[18]
  PIN rhs_add[19]
    DIRECTION OUTPUT ;
    USE SIGNAL ;
    PORT
      LAYER M4 ;
        RECT  64.716 28.08 64.8 28.104 ;
    END
  END rhs_add[19]
  PIN rhs_add[1]
    DIRECTION OUTPUT ;
    USE SIGNAL ;
    PORT
      LAYER M4 ;
        RECT  64.716 26.352 64.8 26.376 ;
    END
  END rhs_add[1]
  PIN rhs_add[20]
    DIRECTION OUTPUT ;
    USE SIGNAL ;
    PORT
      LAYER M4 ;
        RECT  64.716 28.176 64.8 28.2 ;
    END
  END rhs_add[20]
  PIN rhs_add[21]
    DIRECTION OUTPUT ;
    USE SIGNAL ;
    PORT
      LAYER M4 ;
        RECT  64.716 28.272 64.8 28.296 ;
    END
  END rhs_add[21]
  PIN rhs_add[22]
    DIRECTION OUTPUT ;
    USE SIGNAL ;
    PORT
      LAYER M4 ;
        RECT  64.716 28.368 64.8 28.392 ;
    END
  END rhs_add[22]
  PIN rhs_add[23]
    DIRECTION OUTPUT ;
    USE SIGNAL ;
    PORT
      LAYER M4 ;
        RECT  64.716 28.464 64.8 28.488 ;
    END
  END rhs_add[23]
  PIN rhs_add[24]
    DIRECTION OUTPUT ;
    USE SIGNAL ;
    PORT
      LAYER M4 ;
        RECT  64.716 28.56 64.8 28.584 ;
    END
  END rhs_add[24]
  PIN rhs_add[25]
    DIRECTION OUTPUT ;
    USE SIGNAL ;
    PORT
      LAYER M4 ;
        RECT  64.716 28.656 64.8 28.68 ;
    END
  END rhs_add[25]
  PIN rhs_add[26]
    DIRECTION OUTPUT ;
    USE SIGNAL ;
    PORT
      LAYER M4 ;
        RECT  64.716 28.752 64.8 28.776 ;
    END
  END rhs_add[26]
  PIN rhs_add[27]
    DIRECTION OUTPUT ;
    USE SIGNAL ;
    PORT
      LAYER M4 ;
        RECT  64.716 28.848 64.8 28.872 ;
    END
  END rhs_add[27]
  PIN rhs_add[28]
    DIRECTION OUTPUT ;
    USE SIGNAL ;
    PORT
      LAYER M4 ;
        RECT  64.716 28.944 64.8 28.968 ;
    END
  END rhs_add[28]
  PIN rhs_add[29]
    DIRECTION OUTPUT ;
    USE SIGNAL ;
    PORT
      LAYER M4 ;
        RECT  64.716 29.04 64.8 29.064 ;
    END
  END rhs_add[29]
  PIN rhs_add[2]
    DIRECTION OUTPUT ;
    USE SIGNAL ;
    PORT
      LAYER M4 ;
        RECT  64.716 26.448 64.8 26.472 ;
    END
  END rhs_add[2]
  PIN rhs_add[30]
    DIRECTION OUTPUT ;
    USE SIGNAL ;
    PORT
      LAYER M4 ;
        RECT  64.716 29.136 64.8 29.16 ;
    END
  END rhs_add[30]
  PIN rhs_add[31]
    DIRECTION OUTPUT ;
    USE SIGNAL ;
    PORT
      LAYER M4 ;
        RECT  64.716 29.232 64.8 29.256 ;
    END
  END rhs_add[31]
  PIN rhs_add[3]
    DIRECTION OUTPUT ;
    USE SIGNAL ;
    PORT
      LAYER M4 ;
        RECT  64.716 26.544 64.8 26.568 ;
    END
  END rhs_add[3]
  PIN rhs_add[4]
    DIRECTION OUTPUT ;
    USE SIGNAL ;
    PORT
      LAYER M4 ;
        RECT  64.716 26.64 64.8 26.664 ;
    END
  END rhs_add[4]
  PIN rhs_add[5]
    DIRECTION OUTPUT ;
    USE SIGNAL ;
    PORT
      LAYER M4 ;
        RECT  64.716 26.736 64.8 26.76 ;
    END
  END rhs_add[5]
  PIN rhs_add[6]
    DIRECTION OUTPUT ;
    USE SIGNAL ;
    PORT
      LAYER M4 ;
        RECT  64.716 26.832 64.8 26.856 ;
    END
  END rhs_add[6]
  PIN rhs_add[7]
    DIRECTION OUTPUT ;
    USE SIGNAL ;
    PORT
      LAYER M4 ;
        RECT  64.716 26.928 64.8 26.952 ;
    END
  END rhs_add[7]
  PIN rhs_add[8]
    DIRECTION OUTPUT ;
    USE SIGNAL ;
    PORT
      LAYER M4 ;
        RECT  64.716 27.024 64.8 27.048 ;
    END
  END rhs_add[8]
  PIN rhs_add[9]
    DIRECTION OUTPUT ;
    USE SIGNAL ;
    PORT
      LAYER M4 ;
        RECT  64.716 27.12 64.8 27.144 ;
    END
  END rhs_add[9]
  PIN rr_tag[0]
    DIRECTION INPUT ;
    USE SIGNAL ;
    PORT
      LAYER M4 ;
        RECT  0 39.792 0.084 39.816 ;
    END
  END rr_tag[0]
  PIN rr_tag[1]
    DIRECTION INPUT ;
    USE SIGNAL ;
    PORT
      LAYER M4 ;
        RECT  0 39.888 0.084 39.912 ;
    END
  END rr_tag[1]
  PIN rr_tag[2]
    DIRECTION INPUT ;
    USE SIGNAL ;
    PORT
      LAYER M4 ;
        RECT  0 39.984 0.084 40.008 ;
    END
  END rr_tag[2]
  PIN tx_data[0]
    DIRECTION OUTPUT ;
    USE SIGNAL ;
    PORT
      LAYER M4 ;
        RECT  64.716 32.4 64.8 32.424 ;
    END
  END tx_data[0]
  PIN tx_data[10]
    DIRECTION OUTPUT ;
    USE SIGNAL ;
    PORT
      LAYER M4 ;
        RECT  64.716 33.36 64.8 33.384 ;
    END
  END tx_data[10]
  PIN tx_data[11]
    DIRECTION OUTPUT ;
    USE SIGNAL ;
    PORT
      LAYER M4 ;
        RECT  64.716 33.456 64.8 33.48 ;
    END
  END tx_data[11]
  PIN tx_data[12]
    DIRECTION OUTPUT ;
    USE SIGNAL ;
    PORT
      LAYER M4 ;
        RECT  64.716 33.552 64.8 33.576 ;
    END
  END tx_data[12]
  PIN tx_data[13]
    DIRECTION OUTPUT ;
    USE SIGNAL ;
    PORT
      LAYER M4 ;
        RECT  64.716 33.648 64.8 33.672 ;
    END
  END tx_data[13]
  PIN tx_data[14]
    DIRECTION OUTPUT ;
    USE SIGNAL ;
    PORT
      LAYER M4 ;
        RECT  64.716 33.744 64.8 33.768 ;
    END
  END tx_data[14]
  PIN tx_data[15]
    DIRECTION OUTPUT ;
    USE SIGNAL ;
    PORT
      LAYER M4 ;
        RECT  64.716 33.84 64.8 33.864 ;
    END
  END tx_data[15]
  PIN tx_data[16]
    DIRECTION OUTPUT ;
    USE SIGNAL ;
    PORT
      LAYER M4 ;
        RECT  64.716 33.936 64.8 33.96 ;
    END
  END tx_data[16]
  PIN tx_data[17]
    DIRECTION OUTPUT ;
    USE SIGNAL ;
    PORT
      LAYER M4 ;
        RECT  64.716 34.032 64.8 34.056 ;
    END
  END tx_data[17]
  PIN tx_data[18]
    DIRECTION OUTPUT ;
    USE SIGNAL ;
    PORT
      LAYER M4 ;
        RECT  64.716 34.128 64.8 34.152 ;
    END
  END tx_data[18]
  PIN tx_data[19]
    DIRECTION OUTPUT ;
    USE SIGNAL ;
    PORT
      LAYER M4 ;
        RECT  64.716 34.224 64.8 34.248 ;
    END
  END tx_data[19]
  PIN tx_data[1]
    DIRECTION OUTPUT ;
    USE SIGNAL ;
    PORT
      LAYER M4 ;
        RECT  64.716 32.496 64.8 32.52 ;
    END
  END tx_data[1]
  PIN tx_data[20]
    DIRECTION OUTPUT ;
    USE SIGNAL ;
    PORT
      LAYER M4 ;
        RECT  64.716 34.32 64.8 34.344 ;
    END
  END tx_data[20]
  PIN tx_data[21]
    DIRECTION OUTPUT ;
    USE SIGNAL ;
    PORT
      LAYER M4 ;
        RECT  64.716 34.416 64.8 34.44 ;
    END
  END tx_data[21]
  PIN tx_data[22]
    DIRECTION OUTPUT ;
    USE SIGNAL ;
    PORT
      LAYER M4 ;
        RECT  64.716 34.512 64.8 34.536 ;
    END
  END tx_data[22]
  PIN tx_data[23]
    DIRECTION OUTPUT ;
    USE SIGNAL ;
    PORT
      LAYER M4 ;
        RECT  64.716 34.608 64.8 34.632 ;
    END
  END tx_data[23]
  PIN tx_data[24]
    DIRECTION OUTPUT ;
    USE SIGNAL ;
    PORT
      LAYER M4 ;
        RECT  64.716 34.704 64.8 34.728 ;
    END
  END tx_data[24]
  PIN tx_data[25]
    DIRECTION OUTPUT ;
    USE SIGNAL ;
    PORT
      LAYER M4 ;
        RECT  64.716 34.8 64.8 34.824 ;
    END
  END tx_data[25]
  PIN tx_data[26]
    DIRECTION OUTPUT ;
    USE SIGNAL ;
    PORT
      LAYER M4 ;
        RECT  64.716 34.896 64.8 34.92 ;
    END
  END tx_data[26]
  PIN tx_data[27]
    DIRECTION OUTPUT ;
    USE SIGNAL ;
    PORT
      LAYER M4 ;
        RECT  64.716 34.992 64.8 35.016 ;
    END
  END tx_data[27]
  PIN tx_data[28]
    DIRECTION OUTPUT ;
    USE SIGNAL ;
    PORT
      LAYER M4 ;
        RECT  64.716 35.088 64.8 35.112 ;
    END
  END tx_data[28]
  PIN tx_data[29]
    DIRECTION OUTPUT ;
    USE SIGNAL ;
    PORT
      LAYER M4 ;
        RECT  64.716 35.184 64.8 35.208 ;
    END
  END tx_data[29]
  PIN tx_data[2]
    DIRECTION OUTPUT ;
    USE SIGNAL ;
    PORT
      LAYER M4 ;
        RECT  64.716 32.592 64.8 32.616 ;
    END
  END tx_data[2]
  PIN tx_data[30]
    DIRECTION OUTPUT ;
    USE SIGNAL ;
    PORT
      LAYER M4 ;
        RECT  64.716 35.28 64.8 35.304 ;
    END
  END tx_data[30]
  PIN tx_data[31]
    DIRECTION OUTPUT ;
    USE SIGNAL ;
    PORT
      LAYER M4 ;
        RECT  64.716 35.376 64.8 35.4 ;
    END
  END tx_data[31]
  PIN tx_data[3]
    DIRECTION OUTPUT ;
    USE SIGNAL ;
    PORT
      LAYER M4 ;
        RECT  64.716 32.688 64.8 32.712 ;
    END
  END tx_data[3]
  PIN tx_data[4]
    DIRECTION OUTPUT ;
    USE SIGNAL ;
    PORT
      LAYER M4 ;
        RECT  64.716 32.784 64.8 32.808 ;
    END
  END tx_data[4]
  PIN tx_data[5]
    DIRECTION OUTPUT ;
    USE SIGNAL ;
    PORT
      LAYER M4 ;
        RECT  64.716 32.88 64.8 32.904 ;
    END
  END tx_data[5]
  PIN tx_data[6]
    DIRECTION OUTPUT ;
    USE SIGNAL ;
    PORT
      LAYER M4 ;
        RECT  64.716 32.976 64.8 33 ;
    END
  END tx_data[6]
  PIN tx_data[7]
    DIRECTION OUTPUT ;
    USE SIGNAL ;
    PORT
      LAYER M4 ;
        RECT  64.716 33.072 64.8 33.096 ;
    END
  END tx_data[7]
  PIN tx_data[8]
    DIRECTION OUTPUT ;
    USE SIGNAL ;
    PORT
      LAYER M4 ;
        RECT  64.716 33.168 64.8 33.192 ;
    END
  END tx_data[8]
  PIN tx_data[9]
    DIRECTION OUTPUT ;
    USE SIGNAL ;
    PORT
      LAYER M4 ;
        RECT  64.716 33.264 64.8 33.288 ;
    END
  END tx_data[9]
  PIN tx_tag[0]
    DIRECTION INPUT ;
    USE SIGNAL ;
    PORT
      LAYER M4 ;
        RECT  0 39.504 0.084 39.528 ;
    END
  END tx_tag[0]
  PIN tx_tag[1]
    DIRECTION INPUT ;
    USE SIGNAL ;
    PORT
      LAYER M4 ;
        RECT  0 39.6 0.084 39.624 ;
    END
  END tx_tag[1]
  PIN tx_tag[2]
    DIRECTION INPUT ;
    USE SIGNAL ;
    PORT
      LAYER M4 ;
        RECT  0 39.696 0.084 39.72 ;
    END
  END tx_tag[2]
  PIN VSS
    DIRECTION INOUT ;
    USE GROUND ;
    PORT
      LAYER M5 ;
        RECT  61.8 2.137 61.92 62.663 ;
        RECT  56.4 2.137 56.52 62.663 ;
        RECT  51 2.137 51.12 62.663 ;
        RECT  45.6 2.137 45.72 62.663 ;
        RECT  40.2 2.137 40.32 62.663 ;
        RECT  34.8 2.137 34.92 62.663 ;
        RECT  29.4 2.137 29.52 62.663 ;
        RECT  24 2.137 24.12 62.663 ;
        RECT  18.6 2.137 18.72 62.663 ;
        RECT  13.2 2.137 13.32 62.663 ;
        RECT  7.8 2.137 7.92 62.663 ;
        RECT  2.4 2.137 2.52 62.663 ;
    END
  END VSS
  PIN VDD
    DIRECTION INOUT ;
    USE POWER ;
    PORT
      LAYER M5 ;
        RECT  61.992 2.151 62.112 62.649 ;
        RECT  56.592 2.151 56.712 62.649 ;
        RECT  51.192 2.151 51.312 62.649 ;
        RECT  45.792 2.151 45.912 62.649 ;
        RECT  40.392 2.151 40.512 62.649 ;
        RECT  34.992 2.151 35.112 62.649 ;
        RECT  29.592 2.151 29.712 62.649 ;
        RECT  24.192 2.151 24.312 62.649 ;
        RECT  18.792 2.151 18.912 62.649 ;
        RECT  13.392 2.151 13.512 62.649 ;
        RECT  7.992 2.151 8.112 62.649 ;
        RECT  2.592 2.151 2.712 62.649 ;
    END
  END VDD
  # OT_OBS_CLOSED layer=M5 d_um=1.536 added=369
  OBS
    LAYER RVTN ;
     RECT  2.16 2.16 62.64 2.295 ;
     RECT  2.16 2.565 62.64 2.835 ;
     RECT  2.16 3.105 62.64 3.375 ;
     RECT  2.16 3.645 62.64 3.915 ;
     RECT  2.16 4.185 62.64 4.455 ;
     RECT  2.16 4.725 62.64 4.995 ;
     RECT  2.16 5.265 62.64 5.535 ;
     RECT  2.16 5.805 62.64 6.075 ;
     RECT  2.16 6.345 62.64 6.615 ;
     RECT  2.16 6.885 62.64 7.155 ;
     RECT  2.16 7.425 62.64 7.695 ;
     RECT  2.16 7.965 62.64 8.235 ;
     RECT  2.16 8.505 62.64 8.775 ;
     RECT  2.16 9.045 62.64 9.315 ;
     RECT  2.16 9.585 62.64 9.855 ;
     RECT  2.16 10.125 62.64 10.395 ;
     RECT  2.16 10.665 62.64 10.935 ;
     RECT  2.16 11.205 62.64 11.475 ;
     RECT  2.16 11.745 62.64 12.015 ;
     RECT  2.16 12.285 62.64 12.555 ;
     RECT  2.16 12.825 62.64 13.095 ;
     RECT  2.16 13.365 62.64 13.635 ;
     RECT  2.16 13.905 62.64 14.175 ;
     RECT  2.16 14.445 62.64 14.715 ;
     RECT  2.16 14.985 62.64 15.255 ;
     RECT  2.16 15.525 62.64 15.795 ;
     RECT  2.16 16.065 62.64 16.335 ;
     RECT  2.16 16.605 62.64 16.875 ;
     RECT  2.16 17.145 62.64 17.415 ;
     RECT  2.16 17.685 62.64 17.955 ;
     RECT  2.16 18.225 62.64 18.495 ;
     RECT  2.16 18.765 62.64 19.035 ;
     RECT  2.16 19.305 62.64 19.575 ;
     RECT  2.16 19.845 62.64 20.115 ;
     RECT  2.16 20.385 62.64 20.655 ;
     RECT  2.16 20.925 62.64 21.195 ;
     RECT  2.16 21.465 62.64 21.735 ;
     RECT  2.16 22.005 62.64 22.275 ;
     RECT  2.16 22.545 62.64 22.815 ;
     RECT  2.16 23.085 62.64 23.355 ;
     RECT  2.16 23.625 62.64 23.895 ;
     RECT  2.16 24.165 62.64 24.435 ;
     RECT  2.16 24.705 62.64 24.975 ;
     RECT  2.16 25.245 62.64 25.515 ;
     RECT  2.16 25.785 62.64 26.055 ;
     RECT  2.16 26.325 62.64 26.595 ;
     RECT  2.16 26.865 62.64 27.135 ;
     RECT  2.16 27.405 62.64 27.675 ;
     RECT  2.16 27.945 62.64 28.215 ;
     RECT  2.16 28.485 62.64 28.755 ;
     RECT  2.16 29.025 62.64 29.295 ;
     RECT  2.16 29.565 62.64 29.835 ;
     RECT  2.16 30.105 62.64 30.375 ;
     RECT  2.16 30.645 62.64 30.915 ;
     RECT  2.16 31.185 62.64 31.455 ;
     RECT  2.16 31.725 62.64 31.995 ;
     RECT  2.16 32.265 62.64 32.535 ;
     RECT  2.16 32.805 62.64 33.075 ;
     RECT  2.16 33.345 62.64 33.615 ;
     RECT  2.16 33.885 62.64 34.155 ;
     RECT  2.16 34.425 62.64 34.695 ;
     RECT  2.16 34.965 62.64 35.235 ;
     RECT  2.16 35.505 62.64 35.775 ;
     RECT  2.16 36.045 62.64 36.315 ;
     RECT  2.16 36.585 62.64 36.855 ;
     RECT  2.16 37.125 62.64 37.395 ;
     RECT  2.16 37.665 62.64 37.935 ;
     RECT  2.16 38.205 62.64 38.475 ;
     RECT  2.16 38.745 62.64 39.015 ;
     RECT  2.16 39.285 62.64 39.555 ;
     RECT  2.16 39.825 62.64 40.095 ;
     RECT  2.16 40.365 62.64 40.635 ;
     RECT  2.16 40.905 62.64 41.175 ;
     RECT  2.16 41.445 62.64 41.715 ;
     RECT  2.16 41.985 62.64 42.255 ;
     RECT  2.16 42.525 62.64 42.795 ;
     RECT  2.16 43.065 62.64 43.335 ;
     RECT  2.16 43.605 62.64 43.875 ;
     RECT  2.16 44.145 62.64 44.415 ;
     RECT  2.16 44.685 62.64 44.955 ;
     RECT  2.16 45.225 62.64 45.495 ;
     RECT  2.16 45.765 62.64 46.035 ;
     RECT  2.16 46.305 62.64 46.575 ;
     RECT  2.16 46.845 62.64 47.115 ;
     RECT  2.16 47.385 62.64 47.655 ;
     RECT  2.16 47.925 62.64 48.195 ;
     RECT  2.16 48.465 62.64 48.735 ;
     RECT  2.16 49.005 62.64 49.275 ;
     RECT  2.16 49.545 62.64 49.815 ;
     RECT  2.16 50.085 62.64 50.355 ;
     RECT  2.16 50.625 62.64 50.895 ;
     RECT  2.16 51.165 62.64 51.435 ;
     RECT  2.16 51.705 62.64 51.975 ;
     RECT  2.16 52.245 62.64 52.515 ;
     RECT  2.16 52.785 62.64 53.055 ;
     RECT  2.16 53.325 62.64 53.595 ;
     RECT  2.16 53.865 62.64 54.135 ;
     RECT  2.16 54.405 62.64 54.675 ;
     RECT  2.16 54.945 62.64 55.215 ;
     RECT  2.16 55.485 62.64 55.755 ;
     RECT  2.16 56.025 62.64 56.295 ;
     RECT  2.16 56.565 62.64 56.835 ;
     RECT  2.16 57.105 62.64 57.375 ;
     RECT  2.16 57.645 62.64 57.915 ;
     RECT  2.16 58.185 62.64 58.455 ;
     RECT  2.16 58.725 62.64 58.995 ;
     RECT  2.16 59.265 62.64 59.535 ;
     RECT  2.16 59.805 62.64 60.075 ;
     RECT  2.16 60.345 62.64 60.615 ;
     RECT  2.16 60.885 62.64 61.155 ;
     RECT  2.16 61.425 62.64 61.695 ;
     RECT  2.16 61.965 62.64 62.235 ;
     RECT  2.16 62.505 62.64 62.64 ;
    LAYER RVTP ;
     RECT  2.16 2.295 62.64 2.565 ;
     RECT  2.16 2.835 62.64 3.105 ;
     RECT  2.16 3.375 62.64 3.645 ;
     RECT  2.16 3.915 62.64 4.185 ;
     RECT  2.16 4.455 62.64 4.725 ;
     RECT  2.16 4.995 62.64 5.265 ;
     RECT  2.16 5.535 62.64 5.805 ;
     RECT  2.16 6.075 62.64 6.345 ;
     RECT  2.16 6.615 62.64 6.885 ;
     RECT  2.16 7.155 62.64 7.425 ;
     RECT  2.16 7.695 62.64 7.965 ;
     RECT  2.16 8.235 62.64 8.505 ;
     RECT  2.16 8.775 62.64 9.045 ;
     RECT  2.16 9.315 62.64 9.585 ;
     RECT  2.16 9.855 62.64 10.125 ;
     RECT  2.16 10.395 62.64 10.665 ;
     RECT  2.16 10.935 62.64 11.205 ;
     RECT  2.16 11.475 62.64 11.745 ;
     RECT  2.16 12.015 62.64 12.285 ;
     RECT  2.16 12.555 62.64 12.825 ;
     RECT  2.16 13.095 62.64 13.365 ;
     RECT  2.16 13.635 62.64 13.905 ;
     RECT  2.16 14.175 62.64 14.445 ;
     RECT  2.16 14.715 62.64 14.985 ;
     RECT  2.16 15.255 62.64 15.525 ;
     RECT  2.16 15.795 62.64 16.065 ;
     RECT  2.16 16.335 62.64 16.605 ;
     RECT  2.16 16.875 62.64 17.145 ;
     RECT  2.16 17.415 62.64 17.685 ;
     RECT  2.16 17.955 62.64 18.225 ;
     RECT  2.16 18.495 62.64 18.765 ;
     RECT  2.16 19.035 62.64 19.305 ;
     RECT  2.16 19.575 62.64 19.845 ;
     RECT  2.16 20.115 62.64 20.385 ;
     RECT  2.16 20.655 62.64 20.925 ;
     RECT  2.16 21.195 62.64 21.465 ;
     RECT  2.16 21.735 62.64 22.005 ;
     RECT  2.16 22.275 62.64 22.545 ;
     RECT  2.16 22.815 62.64 23.085 ;
     RECT  2.16 23.355 62.64 23.625 ;
     RECT  2.16 23.895 62.64 24.165 ;
     RECT  2.16 24.435 62.64 24.705 ;
     RECT  2.16 24.975 62.64 25.245 ;
     RECT  2.16 25.515 62.64 25.785 ;
     RECT  2.16 26.055 62.64 26.325 ;
     RECT  2.16 26.595 62.64 26.865 ;
     RECT  2.16 27.135 62.64 27.405 ;
     RECT  2.16 27.675 62.64 27.945 ;
     RECT  2.16 28.215 62.64 28.485 ;
     RECT  2.16 28.755 62.64 29.025 ;
     RECT  2.16 29.295 62.64 29.565 ;
     RECT  2.16 29.835 62.64 30.105 ;
     RECT  2.16 30.375 62.64 30.645 ;
     RECT  2.16 30.915 62.64 31.185 ;
     RECT  2.16 31.455 62.64 31.725 ;
     RECT  2.16 31.995 62.64 32.265 ;
     RECT  2.16 32.535 62.64 32.805 ;
     RECT  2.16 33.075 62.64 33.345 ;
     RECT  2.16 33.615 62.64 33.885 ;
     RECT  2.16 34.155 62.64 34.425 ;
     RECT  2.16 34.695 62.64 34.965 ;
     RECT  2.16 35.235 62.64 35.505 ;
     RECT  2.16 35.775 62.64 36.045 ;
     RECT  2.16 36.315 62.64 36.585 ;
     RECT  2.16 36.855 62.64 37.125 ;
     RECT  2.16 37.395 62.64 37.665 ;
     RECT  2.16 37.935 62.64 38.205 ;
     RECT  2.16 38.475 62.64 38.745 ;
     RECT  2.16 39.015 62.64 39.285 ;
     RECT  2.16 39.555 62.64 39.825 ;
     RECT  2.16 40.095 62.64 40.365 ;
     RECT  2.16 40.635 62.64 40.905 ;
     RECT  2.16 41.175 62.64 41.445 ;
     RECT  2.16 41.715 62.64 41.985 ;
     RECT  2.16 42.255 62.64 42.525 ;
     RECT  2.16 42.795 62.64 43.065 ;
     RECT  2.16 43.335 62.64 43.605 ;
     RECT  2.16 43.875 62.64 44.145 ;
     RECT  2.16 44.415 62.64 44.685 ;
     RECT  2.16 44.955 62.64 45.225 ;
     RECT  2.16 45.495 62.64 45.765 ;
     RECT  2.16 46.035 62.64 46.305 ;
     RECT  2.16 46.575 62.64 46.845 ;
     RECT  2.16 47.115 62.64 47.385 ;
     RECT  2.16 47.655 62.64 47.925 ;
     RECT  2.16 48.195 62.64 48.465 ;
     RECT  2.16 48.735 62.64 49.005 ;
     RECT  2.16 49.275 62.64 49.545 ;
     RECT  2.16 49.815 62.64 50.085 ;
     RECT  2.16 50.355 62.64 50.625 ;
     RECT  2.16 50.895 62.64 51.165 ;
     RECT  2.16 51.435 62.64 51.705 ;
     RECT  2.16 51.975 62.64 52.245 ;
     RECT  2.16 52.515 62.64 52.785 ;
     RECT  2.16 53.055 62.64 53.325 ;
     RECT  2.16 53.595 62.64 53.865 ;
     RECT  2.16 54.135 62.64 54.405 ;
     RECT  2.16 54.675 62.64 54.945 ;
     RECT  2.16 55.215 62.64 55.485 ;
     RECT  2.16 55.755 62.64 56.025 ;
     RECT  2.16 56.295 62.64 56.565 ;
     RECT  2.16 56.835 62.64 57.105 ;
     RECT  2.16 57.375 62.64 57.645 ;
     RECT  2.16 57.915 62.64 58.185 ;
     RECT  2.16 58.455 62.64 58.725 ;
     RECT  2.16 58.995 62.64 59.265 ;
     RECT  2.16 59.535 62.64 59.805 ;
     RECT  2.16 60.075 62.64 60.345 ;
     RECT  2.16 60.615 62.64 60.885 ;
     RECT  2.16 61.155 62.64 61.425 ;
     RECT  2.16 61.695 62.64 61.965 ;
     RECT  2.16 62.235 62.64 62.505 ;
    LAYER M1 ;
     RECT  2.16 2.151 62.64 62.649 ;
    LAYER M2 ;
     RECT  0.103 24.48 0.139 24.498 ;
     RECT  0.139 24.408 0.175 24.498 ;
     RECT  0.103 28.422 0.175 28.44 ;
     RECT  0.211 29.61 0.535 29.628 ;
     RECT  0.103 41.724 1.759 41.742 ;
     RECT  1.759 41.112 1.831 41.742 ;
     RECT  0.175 24.138 2.16 24.498 ;
     RECT  0.535 25.56 2.16 25.578 ;
     RECT  0.175 26.604 2.16 26.622 ;
     RECT  0.175 28.26 2.16 28.44 ;
     RECT  0.535 29.61 2.16 29.898 ;
     RECT  0.535 32.238 2.16 32.256 ;
     RECT  0.211 33.048 2.16 33.066 ;
     RECT  0.103 34.47 2.16 34.488 ;
     RECT  1.831 40.644 2.16 41.742 ;
     RECT  2.16 2.151 62.64 62.649 ;
     RECT  62.64 24.678 63.275 28.674 ;
     RECT  62.64 30.384 63.275 40.824 ;
     RECT  63.275 24.678 63.311 28.584 ;
     RECT  63.275 36.018 63.779 40.824 ;
     RECT  63.311 24.786 63.815 28.584 ;
     RECT  63.275 30.384 63.851 35.226 ;
     RECT  63.779 36.018 63.851 38.574 ;
     RECT  63.815 25.182 63.887 28.584 ;
     RECT  63.851 30.69 63.887 32.022 ;
     RECT  63.851 32.778 63.887 35.226 ;
     RECT  63.887 26.028 63.923 28.584 ;
     RECT  63.887 32.778 63.923 33.714 ;
     RECT  63.887 25.182 63.959 25.2 ;
     RECT  63.887 30.726 63.959 31.986 ;
     RECT  63.923 26.298 63.995 28.584 ;
     RECT  63.995 26.298 64.067 28.548 ;
     RECT  64.067 28.026 64.103 28.548 ;
     RECT  64.067 26.298 64.139 26.856 ;
     RECT  63.851 36.018 64.535 38.124 ;
     RECT  63.887 34.938 64.543 35.226 ;
     RECT  64.535 36.018 64.543 37.926 ;
     RECT  64.543 34.938 64.571 37.926 ;
     RECT  62.64 29.574 64.615 29.592 ;
     RECT  63.959 30.726 64.615 31.914 ;
     RECT  63.779 39.33 64.643 40.824 ;
     RECT  64.139 26.298 64.679 26.694 ;
     RECT  64.571 34.938 64.679 35.694 ;
     RECT  64.643 39.33 64.679 39.654 ;
     RECT  63.923 33.426 64.687 33.714 ;
     RECT  64.615 29.574 64.715 31.914 ;
     RECT  64.687 33.426 64.715 33.804 ;
     RECT  64.679 35.676 64.715 35.694 ;
     RECT  64.571 36.522 64.715 37.926 ;
     RECT  64.679 39.33 64.715 39.348 ;
     RECT  64.679 26.298 64.751 26.316 ;
     RECT  64.103 28.53 64.751 28.548 ;
     RECT  64.715 33.786 64.787 33.804 ;
     RECT  64.715 36.522 64.787 36.54 ;
     RECT  64.715 37.908 64.787 37.926 ;
     RECT  64.643 40.806 64.787 40.824 ;
    LAYER M3 ;
     RECT  24.015 2.143 24.105 2.191 ;
     RECT  17.064 2.191 17.082 2.227 ;
     RECT  23.94 2.191 24.105 2.251 ;
     RECT  29.415 2.143 29.505 2.251 ;
     RECT  13.215 2.143 13.305 2.263 ;
     RECT  26.1 2.251 26.118 2.263 ;
     RECT  29.415 2.251 29.79 2.263 ;
     RECT  18.615 2.143 18.705 2.299 ;
     RECT  23.832 2.251 24.105 2.299 ;
     RECT  29.415 2.263 30.006 2.299 ;
     RECT  29.34 2.299 30.078 2.335 ;
     RECT  11.052 2.335 11.07 2.371 ;
     RECT  15.84 2.227 15.858 2.371 ;
     RECT  17.064 2.227 17.442 2.371 ;
     RECT  23.364 2.299 24.105 2.371 ;
     RECT  26.1 2.263 26.298 2.371 ;
     RECT  27.108 2.299 27.126 2.371 ;
     RECT  29.34 2.335 30.222 2.371 ;
     RECT  32.22 2.335 32.238 2.371 ;
     RECT  33.156 2.191 33.174 2.371 ;
     RECT  34.815 2.143 34.905 2.371 ;
     RECT  44.28 2.191 44.298 2.371 ;
     RECT  45.615 2.143 45.705 2.371 ;
     RECT  2.415 2.143 2.505 2.413 ;
     RECT  7.815 2.143 7.905 2.413 ;
     RECT  18.615 2.299 18.774 2.413 ;
     RECT  34.2 2.371 34.905 2.413 ;
     RECT  40.215 2.143 40.305 2.413 ;
     RECT  51.015 2.143 51.105 2.413 ;
     RECT  56.415 2.143 56.505 2.413 ;
     RECT  61.815 2.143 61.905 2.413 ;
     RECT  11.052 2.371 11.322 2.461 ;
     RECT  12.06 2.371 12.078 2.461 ;
     RECT  15.84 2.371 15.894 2.461 ;
     RECT  19.728 2.371 19.746 2.461 ;
     RECT  20.7 2.299 20.79 2.461 ;
     RECT  33.156 2.371 33.462 2.461 ;
     RECT  34.2 2.413 35.097 2.461 ;
     RECT  51.015 2.413 51.297 2.461 ;
     RECT  40.215 2.413 40.497 2.491 ;
     RECT  48.24 2.461 48.258 2.497 ;
     RECT  31.932 2.371 32.238 2.533 ;
     RECT  35.964 2.461 35.982 2.533 ;
     RECT  48.24 2.497 48.87 2.533 ;
     RECT  49.644 2.371 49.662 2.533 ;
     RECT  48.096 2.533 48.87 2.539 ;
     RECT  11.052 2.461 12.078 2.569 ;
     RECT  13.215 2.263 13.77 2.569 ;
     RECT  14.796 2.227 14.814 2.569 ;
     RECT  29.34 2.371 30.294 2.569 ;
     RECT  31.824 2.533 32.238 2.569 ;
     RECT  35.928 2.533 36.882 2.569 ;
     RECT  45.615 2.371 46.062 2.569 ;
     RECT  11.016 2.569 12.33 2.605 ;
     RECT  13.215 2.569 14.814 2.605 ;
     RECT  15.624 2.461 15.894 2.605 ;
     RECT  18.615 2.413 18.897 2.605 ;
     RECT  19.728 2.461 19.782 2.605 ;
     RECT  20.7 2.461 20.862 2.605 ;
     RECT  35.82 2.569 36.882 2.605 ;
     RECT  44.1 2.371 44.298 2.605 ;
     RECT  45.615 2.569 46.674 2.605 ;
     RECT  47.808 2.539 48.87 2.605 ;
     RECT  49.644 2.533 49.986 2.605 ;
     RECT  9.252 2.461 9.27 2.641 ;
     RECT  11.016 2.605 15.966 2.641 ;
     RECT  16.848 2.371 17.442 2.641 ;
     RECT  18.504 2.605 18.897 2.641 ;
     RECT  19.728 2.605 20.862 2.641 ;
     RECT  26.1 2.371 27.882 2.641 ;
     RECT  29.088 2.569 30.294 2.641 ;
     RECT  39.348 2.605 39.366 2.641 ;
     RECT  40.215 2.491 41.202 2.641 ;
     RECT  42.408 2.488 42.426 2.641 ;
     RECT  43.488 2.605 44.298 2.641 ;
     RECT  47.808 2.605 49.986 2.641 ;
     RECT  26.1 2.641 30.294 2.731 ;
     RECT  31.032 2.569 32.238 2.731 ;
     RECT  33.156 2.461 35.097 2.731 ;
     RECT  35.82 2.605 37.134 2.731 ;
     RECT  37.944 2.641 38.43 2.731 ;
     RECT  39.348 2.641 42.606 2.731 ;
     RECT  51.015 2.461 51.894 2.731 ;
     RECT  52.668 2.605 52.686 2.731 ;
     RECT  10.764 2.641 15.966 2.767 ;
     RECT  16.74 2.641 21.906 2.767 ;
     RECT  45.615 2.605 46.926 2.767 ;
     RECT  51.015 2.731 52.686 2.767 ;
     RECT  9.252 2.641 9.738 2.803 ;
     RECT  10.764 2.767 21.906 2.803 ;
     RECT  33.156 2.731 42.606 2.803 ;
     RECT  43.38 2.641 44.334 2.803 ;
     RECT  45.612 2.767 46.926 2.803 ;
     RECT  45.612 2.803 46.962 2.827 ;
     RECT  9.252 2.803 9.81 2.839 ;
     RECT  33.156 2.803 44.55 2.839 ;
     RECT  26.1 2.731 32.238 2.911 ;
     RECT  47.808 2.641 50.094 2.911 ;
     RECT  51.012 2.767 52.686 2.911 ;
     RECT  47.808 2.911 53.118 2.923 ;
     RECT  33.156 2.839 44.586 3.001 ;
     RECT  45.432 2.827 46.962 3.001 ;
     RECT  33.156 3.001 46.962 3.028 ;
     RECT  10.764 2.803 22.482 3.037 ;
     RECT  33.12 3.028 46.962 3.073 ;
     RECT  10.728 3.037 22.482 3.109 ;
     RECT  23.256 2.371 24.57 3.109 ;
     RECT  33.048 3.073 46.962 3.145 ;
     RECT  47.736 2.923 53.118 3.145 ;
     RECT  33.048 3.145 53.118 3.173 ;
     RECT  9.216 2.839 9.81 3.181 ;
     RECT  25.848 2.911 32.238 3.181 ;
     RECT  33.048 3.173 52.974 3.181 ;
     RECT  10.728 3.109 24.57 3.271 ;
     RECT  7.815 2.413 8.097 3.343 ;
     RECT  25.74 3.181 52.974 3.355 ;
     RECT  10.728 3.271 24.606 3.379 ;
     RECT  25.596 3.355 52.974 3.407 ;
     RECT  7.452 3.343 8.097 3.415 ;
     RECT  9.072 3.181 9.81 3.415 ;
     RECT  10.728 3.379 24.642 3.415 ;
     RECT  25.596 3.407 44.586 3.437 ;
     RECT  7.38 3.415 8.097 3.451 ;
     RECT  9.072 3.415 24.714 3.451 ;
     RECT  45.36 3.407 52.974 3.569 ;
     RECT  7.38 3.451 24.714 3.577 ;
     RECT  7.272 3.577 24.714 3.605 ;
     RECT  15.192 3.605 24.714 3.721 ;
     RECT  25.596 3.437 44.55 3.721 ;
     RECT  15.192 3.721 44.55 3.749 ;
     RECT  45.468 3.569 52.974 3.839 ;
     RECT  15.192 3.749 25.434 3.911 ;
     RECT  20.124 3.911 25.434 3.92 ;
     RECT  7.272 3.605 14.418 3.991 ;
     RECT  7.092 3.991 14.418 4.081 ;
     RECT  6.66 4.081 14.418 4.117 ;
     RECT  6.552 4.117 14.418 4.189 ;
     RECT  5.976 4.189 14.418 4.225 ;
     RECT  50.004 3.839 52.974 4.261 ;
     RECT  50.004 4.261 53.154 4.387 ;
     RECT  5.868 4.225 14.418 4.423 ;
     RECT  15.192 3.911 19.386 4.423 ;
     RECT  45.468 3.839 48.906 4.459 ;
     RECT  5.868 4.423 19.386 4.507 ;
     RECT  50.004 4.387 53.226 4.531 ;
     RECT  45.432 4.459 48.906 4.559 ;
     RECT  47.088 4.559 48.906 4.651 ;
     RECT  47.088 4.651 49.158 4.657 ;
     RECT  20.124 3.92 24.642 4.757 ;
     RECT  45.432 4.559 46.35 4.765 ;
     RECT  25.416 3.92 25.434 4.801 ;
     RECT  26.244 3.749 44.55 4.801 ;
     RECT  54.468 4.729 54.954 4.801 ;
     RECT  25.416 4.801 44.55 4.829 ;
     RECT  25.488 4.829 44.55 4.891 ;
     RECT  45.324 4.765 46.35 4.891 ;
     RECT  5.832 4.507 19.386 5.029 ;
     RECT  20.124 4.757 24.606 5.029 ;
     RECT  5.832 5.029 24.606 5.035 ;
     RECT  25.488 4.891 46.35 5.063 ;
     RECT  47.088 4.657 49.266 5.071 ;
     RECT  50.004 4.531 53.334 5.071 ;
     RECT  47.088 5.071 53.334 5.161 ;
     RECT  54.468 4.801 55.35 5.161 ;
     RECT  5.724 5.035 24.606 5.197 ;
     RECT  5.688 5.197 24.606 5.333 ;
     RECT  5.688 5.333 10.602 5.341 ;
     RECT  47.088 5.161 55.35 5.341 ;
     RECT  47.088 5.341 55.458 5.431 ;
     RECT  56.415 2.413 56.697 5.431 ;
     RECT  33.192 5.063 46.35 5.539 ;
     RECT  47.088 5.431 56.697 5.539 ;
     RECT  11.412 5.333 24.606 5.773 ;
     RECT  25.488 5.063 32.346 5.773 ;
     RECT  33.192 5.539 56.697 5.845 ;
     RECT  4.824 4.531 4.842 5.971 ;
     RECT  5.616 5.341 10.602 5.971 ;
     RECT  11.412 5.773 32.346 6.007 ;
     RECT  33.192 5.845 56.79 6.007 ;
     RECT  4.824 5.971 10.602 6.071 ;
     RECT  11.412 6.007 56.79 6.241 ;
     RECT  4.824 6.071 5.022 6.269 ;
     RECT  4.824 6.269 4.842 6.328 ;
     RECT  5.76 6.071 10.602 6.331 ;
     RECT  11.412 6.241 57.366 6.331 ;
     RECT  5.76 6.331 57.366 6.421 ;
     RECT  5.76 6.421 57.438 6.611 ;
     RECT  5.76 6.611 57.366 6.989 ;
     RECT  3.888 4.963 3.906 7.087 ;
     RECT  5.76 6.989 32.886 7.087 ;
     RECT  3.888 7.087 4.59 7.099 ;
     RECT  5.508 7.087 32.886 7.099 ;
     RECT  3.888 7.099 32.886 7.133 ;
     RECT  33.624 6.989 57.366 7.501 ;
     RECT  5.292 7.133 32.886 7.619 ;
     RECT  33.624 7.501 57.798 7.691 ;
     RECT  25.596 7.619 32.886 7.771 ;
     RECT  33.624 7.691 57.654 7.771 ;
     RECT  3.888 7.133 3.906 7.963 ;
     RECT  5.292 7.619 24.714 8.311 ;
     RECT  25.596 7.771 57.654 8.429 ;
     RECT  3.888 7.963 4.482 8.525 ;
     RECT  5.22 8.311 24.714 8.581 ;
     RECT  25.596 8.429 27.558 8.581 ;
     RECT  28.296 8.429 57.654 8.879 ;
     RECT  45.396 8.879 57.654 9.113 ;
     RECT  4.644 8.581 27.558 9.247 ;
     RECT  28.296 8.879 44.658 9.247 ;
     RECT  4.644 9.247 44.658 9.509 ;
     RECT  4.752 9.509 44.658 9.895 ;
     RECT  45.396 9.113 57.402 9.895 ;
     RECT  3.888 8.525 3.906 10.291 ;
     RECT  4.752 9.895 57.402 10.291 ;
     RECT  3.888 10.291 57.402 10.471 ;
     RECT  58.788 8.131 58.806 10.561 ;
     RECT  3.888 10.471 57.51 10.625 ;
     RECT  22.212 10.625 57.51 10.661 ;
     RECT  49.176 10.661 57.51 10.733 ;
     RECT  49.464 10.733 57.51 10.741 ;
     RECT  58.572 10.561 58.806 10.741 ;
     RECT  49.464 10.741 58.806 11.003 ;
     RECT  3.888 10.625 21.15 11.261 ;
     RECT  3.888 11.261 21.114 11.399 ;
     RECT  22.212 10.661 48.438 11.407 ;
     RECT  22.212 11.407 48.654 11.515 ;
     RECT  21.888 11.515 48.654 11.551 ;
     RECT  49.464 11.003 57.474 11.551 ;
     RECT  58.572 11.003 58.806 11.947 ;
     RECT  21.888 11.551 57.474 12.091 ;
     RECT  21.888 12.091 57.582 12.209 ;
     RECT  12.96 11.399 21.114 12.289 ;
     RECT  21.888 12.209 48.474 12.289 ;
     RECT  3.888 11.399 12.222 12.325 ;
     RECT  12.96 12.289 48.474 12.325 ;
     RECT  49.356 12.209 57.582 12.361 ;
     RECT  49.356 12.361 57.654 12.515 ;
     RECT  3.888 12.325 48.474 12.551 ;
     RECT  49.428 12.515 57.654 12.557 ;
     RECT  49.5 12.557 57.654 12.785 ;
     RECT  49.5 12.785 57.438 12.857 ;
     RECT  3.888 12.551 41.49 12.893 ;
     RECT  42.228 12.551 48.474 13.297 ;
     RECT  42.156 13.297 48.474 13.567 ;
     RECT  42.156 13.567 48.618 13.675 ;
     RECT  49.5 12.857 57.402 13.675 ;
     RECT  58.464 11.947 58.806 13.675 ;
     RECT  3.888 12.893 41.274 13.711 ;
     RECT  42.156 13.675 48.69 13.711 ;
     RECT  3.888 13.711 48.69 13.837 ;
     RECT  49.5 13.675 58.806 13.837 ;
     RECT  3.888 13.837 58.806 13.901 ;
     RECT  3.888 13.901 22.05 14.369 ;
     RECT  22.788 13.901 58.806 14.779 ;
     RECT  3.888 14.369 21.762 14.819 ;
     RECT  20.484 14.819 21.762 15.187 ;
     RECT  22.572 14.779 58.806 15.187 ;
     RECT  3.888 14.819 19.746 15.601 ;
     RECT  20.484 15.187 58.806 15.601 ;
     RECT  3.888 15.601 58.806 17.915 ;
     RECT  37.908 17.915 58.806 18.661 ;
     RECT  3.888 17.915 37.026 18.805 ;
     RECT  3.888 18.805 37.062 19.075 ;
     RECT  37.836 18.661 58.806 19.075 ;
     RECT  3.888 19.075 58.806 19.229 ;
     RECT  3.888 19.229 20.502 20.011 ;
     RECT  21.384 19.229 58.806 20.011 ;
     RECT  3.888 20.011 58.806 21.101 ;
     RECT  34.128 21.101 58.806 21.389 ;
     RECT  3.888 21.101 33.246 21.505 ;
     RECT  3.564 21.505 33.246 21.901 ;
     RECT  3.564 21.901 33.354 22.009 ;
     RECT  3.564 22.009 33.462 22.207 ;
     RECT  34.308 21.389 58.806 22.207 ;
     RECT  3.564 22.207 58.806 22.577 ;
     RECT  3.564 22.577 20.034 22.685 ;
     RECT  20.88 22.577 58.806 22.739 ;
     RECT  3.564 22.685 17.838 22.775 ;
     RECT  20.88 22.739 25.002 22.781 ;
     RECT  20.88 22.781 24.75 22.811 ;
     RECT  20.88 22.811 22.518 23.009 ;
     RECT  25.884 22.739 58.806 23.045 ;
     RECT  25.956 23.045 58.806 23.117 ;
     RECT  25.992 23.117 58.806 23.153 ;
     RECT  3.564 22.775 17.802 23.161 ;
     RECT  22.392 23.009 22.518 23.279 ;
     RECT  23.328 22.811 24.75 23.279 ;
     RECT  20.88 23.009 21.546 23.309 ;
     RECT  22.392 23.279 22.482 23.315 ;
     RECT  22.464 23.315 22.482 23.351 ;
     RECT  23.4 23.279 24.642 23.351 ;
     RECT  18.615 22.685 20.034 23.359 ;
     RECT  20.88 23.309 21.222 23.359 ;
     RECT  2.415 2.413 2.697 23.371 ;
     RECT  3.492 23.161 17.802 23.371 ;
     RECT  26.064 23.153 58.806 23.423 ;
     RECT  34.236 23.423 58.806 23.891 ;
     RECT  26.064 23.423 33.39 23.935 ;
     RECT  25.776 23.935 33.39 23.947 ;
     RECT  23.94 23.351 24.642 24.061 ;
     RECT  25.488 23.947 33.39 24.061 ;
     RECT  34.236 23.891 35.694 24.089 ;
     RECT  36.432 23.891 58.806 24.125 ;
     RECT  18.615 23.359 21.222 24.133 ;
     RECT  21.96 24.091 21.978 24.133 ;
     RECT  18.615 24.133 21.978 24.169 ;
     RECT  0.18 24.133 0.198 24.205 ;
     RECT  2.415 23.371 17.802 24.205 ;
     RECT  18.615 24.169 22.302 24.205 ;
     RECT  34.236 24.089 35.622 24.233 ;
     RECT  2.415 24.205 22.302 24.241 ;
     RECT  23.94 24.061 33.39 24.241 ;
     RECT  34.236 24.233 35.55 24.241 ;
     RECT  61.815 2.413 62.097 24.331 ;
     RECT  36.432 24.125 38.718 24.395 ;
     RECT  0.18 24.205 0.558 24.403 ;
     RECT  0.144 24.403 0.558 24.475 ;
     RECT  2.415 24.241 22.986 24.475 ;
     RECT  61.815 24.331 62.55 24.475 ;
     RECT  2.376 24.475 22.986 24.601 ;
     RECT  39.456 24.125 58.806 24.665 ;
     RECT  23.94 24.241 35.55 24.701 ;
     RECT  2.376 24.601 23.202 24.709 ;
     RECT  23.94 24.701 31.734 24.709 ;
     RECT  61.74 24.475 62.55 24.781 ;
     RECT  63.288 24.673 63.306 24.781 ;
     RECT  36.432 24.395 38.502 24.899 ;
     RECT  0.108 24.475 0.558 24.941 ;
     RECT  39.6 24.665 58.806 24.971 ;
     RECT  61.164 24.781 62.55 25.051 ;
     RECT  63.288 24.781 63.81 25.051 ;
     RECT  41.832 24.971 58.806 25.169 ;
     RECT  60.66 25.051 63.81 25.177 ;
     RECT  38.268 24.899 38.502 25.213 ;
     RECT  0.324 24.941 0.558 25.229 ;
     RECT  36.432 24.899 37.458 25.249 ;
     RECT  2.376 24.709 31.734 25.285 ;
     RECT  2.304 25.285 31.734 25.339 ;
     RECT  36.396 25.249 37.458 25.349 ;
     RECT  38.268 25.213 38.754 25.411 ;
     RECT  39.6 24.971 41.058 25.411 ;
     RECT  2.196 25.339 31.734 25.475 ;
     RECT  2.268 25.475 31.734 25.547 ;
     RECT  32.472 24.701 35.55 25.591 ;
     RECT  2.304 25.547 31.734 25.681 ;
     RECT  32.472 25.591 35.622 25.681 ;
     RECT  59.904 24.781 59.922 25.681 ;
     RECT  60.66 25.177 63.954 25.681 ;
     RECT  41.868 25.169 58.806 25.861 ;
     RECT  59.904 25.681 63.954 25.861 ;
     RECT  0.54 25.229 0.558 25.963 ;
     RECT  0.324 25.963 0.558 26.189 ;
     RECT  2.304 25.681 35.622 26.221 ;
     RECT  36.432 25.349 37.458 26.221 ;
     RECT  38.268 25.411 41.058 26.221 ;
     RECT  2.304 26.221 41.058 26.401 ;
     RECT  41.868 25.861 63.954 26.401 ;
     RECT  0.324 26.189 0.342 26.573 ;
     RECT  2.304 26.401 63.954 26.599 ;
     RECT  2.304 26.599 63.99 26.671 ;
     RECT  64.728 26.293 64.746 26.671 ;
     RECT  2.304 26.671 64.746 27.019 ;
     RECT  2.268 27.019 64.746 27.203 ;
     RECT  41.868 27.203 64.746 27.239 ;
     RECT  41.94 27.239 64.746 27.365 ;
     RECT  2.268 27.203 41.022 27.533 ;
     RECT  0.18 26.599 0.198 27.787 ;
     RECT  2.304 27.533 41.022 28.111 ;
     RECT  2.304 28.111 41.13 28.147 ;
     RECT  2.304 28.147 41.238 28.255 ;
     RECT  41.976 27.365 64.746 28.255 ;
     RECT  0.18 27.787 0.342 28.417 ;
     RECT  0.108 28.417 0.342 28.493 ;
     RECT  2.304 28.255 64.746 28.553 ;
     RECT  2.304 28.553 64.674 28.651 ;
     RECT  0.108 28.493 0.198 28.877 ;
     RECT  0.18 28.877 0.198 28.973 ;
     RECT  2.268 28.651 64.674 28.985 ;
     RECT  2.304 28.985 64.674 29.261 ;
     RECT  0.216 29.419 0.342 29.875 ;
     RECT  0.216 29.875 0.558 29.899 ;
     RECT  64.692 29.515 64.71 30.001 ;
     RECT  0.144 29.899 0.558 30.077 ;
     RECT  64.62 30.001 64.71 30.077 ;
     RECT  0.216 30.077 0.558 30.125 ;
     RECT  0.54 30.125 0.558 30.413 ;
     RECT  2.304 29.261 63.882 30.571 ;
     RECT  2.268 30.571 63.882 30.875 ;
     RECT  2.304 30.875 63.882 31.289 ;
     RECT  0.216 30.907 0.234 31.339 ;
     RECT  63.252 31.289 63.882 31.423 ;
     RECT  0.216 31.339 0.342 31.469 ;
     RECT  63.252 31.423 63.918 31.693 ;
     RECT  64.692 30.077 64.71 31.693 ;
     RECT  63.252 31.693 64.71 32.011 ;
     RECT  63.216 32.011 64.71 32.107 ;
     RECT  0.144 31.675 0.162 32.233 ;
     RECT  2.304 31.289 62.37 32.233 ;
     RECT  63.18 32.107 64.71 32.233 ;
     RECT  2.304 32.233 64.71 32.395 ;
     RECT  2.268 32.395 64.71 32.477 ;
     RECT  0.144 32.233 0.558 32.525 ;
     RECT  2.268 32.477 62.334 32.765 ;
     RECT  63.144 32.477 64.71 32.909 ;
     RECT  2.304 32.765 62.334 32.999 ;
     RECT  0.144 32.525 0.234 33.101 ;
     RECT  63.144 32.909 63.918 33.101 ;
     RECT  64.656 32.909 64.71 33.781 ;
     RECT  2.304 32.999 62.298 33.931 ;
     RECT  63.144 33.101 63.882 33.931 ;
     RECT  2.304 33.931 63.882 34.027 ;
     RECT  2.268 34.027 63.882 34.187 ;
     RECT  2.304 34.187 63.882 34.219 ;
     RECT  64.656 33.781 64.782 34.219 ;
     RECT  0.144 33.101 0.162 34.465 ;
     RECT  2.304 34.219 64.782 34.619 ;
     RECT  2.304 34.619 63.558 34.889 ;
     RECT  0.108 34.465 0.162 34.925 ;
     RECT  0.144 34.925 0.162 35.371 ;
     RECT  28.296 34.889 63.558 35.465 ;
     RECT  0.144 35.371 0.342 35.501 ;
     RECT  41.976 35.465 63.558 35.563 ;
     RECT  64.476 34.619 64.782 35.563 ;
     RECT  2.304 34.889 27.558 35.659 ;
     RECT  0.144 35.501 0.198 35.741 ;
     RECT  2.268 35.659 27.558 36.005 ;
     RECT  28.296 35.465 41.13 36.005 ;
     RECT  2.304 36.005 27.558 36.049 ;
     RECT  28.296 36.005 31.374 36.049 ;
     RECT  32.256 36.005 41.13 36.247 ;
     RECT  41.976 35.563 64.782 36.247 ;
     RECT  0.144 35.741 0.162 36.317 ;
     RECT  32.256 36.247 64.782 36.347 ;
     RECT  63.108 36.347 64.782 36.545 ;
     RECT  32.256 36.347 41.418 36.779 ;
     RECT  2.304 36.049 31.374 36.811 ;
     RECT  32.256 36.779 41.382 36.811 ;
     RECT  42.156 36.347 62.334 36.815 ;
     RECT  2.304 36.811 41.382 37.192 ;
     RECT  2.268 37.192 41.382 37.229 ;
     RECT  42.156 36.815 62.298 37.579 ;
     RECT  2.304 37.229 41.382 37.741 ;
     RECT  42.156 37.579 62.334 37.741 ;
     RECT  63.108 36.545 64.71 37.903 ;
     RECT  2.304 37.741 62.334 37.963 ;
     RECT  63.108 37.903 64.782 37.963 ;
     RECT  2.304 37.963 64.782 38.039 ;
     RECT  2.304 38.039 54.882 38.189 ;
     RECT  2.304 38.189 41.454 38.347 ;
     RECT  42.768 38.189 54.882 38.399 ;
     RECT  42.84 38.399 54.882 38.525 ;
     RECT  55.656 38.039 64.782 38.579 ;
     RECT  0.324 37.291 0.342 38.731 ;
     RECT  0.108 38.731 0.342 38.765 ;
     RECT  42.912 38.525 54.882 38.779 ;
     RECT  55.656 38.579 63.774 38.779 ;
     RECT  2.268 38.347 41.454 38.911 ;
     RECT  42.912 38.779 63.774 38.939 ;
     RECT  55.332 38.939 63.774 39.047 ;
     RECT  2.268 38.911 41.598 39.115 ;
     RECT  2.232 39.115 41.598 39.181 ;
     RECT  55.368 39.047 63.774 39.209 ;
     RECT  55.368 39.209 58.446 39.245 ;
     RECT  55.368 39.245 57.402 39.479 ;
     RECT  58.356 39.245 58.446 39.479 ;
     RECT  59.364 39.209 63.774 39.479 ;
     RECT  2.232 39.181 41.67 39.487 ;
     RECT  2.232 39.487 41.814 39.595 ;
     RECT  42.912 38.939 54.378 39.721 ;
     RECT  59.364 39.479 63.558 39.749 ;
     RECT  1.764 39.595 41.814 39.793 ;
     RECT  1.764 39.793 41.922 39.865 ;
     RECT  42.912 39.721 54.558 39.865 ;
     RECT  55.368 39.479 57.33 39.865 ;
     RECT  58.392 39.479 58.41 40.019 ;
     RECT  55.332 39.865 57.33 40.297 ;
     RECT  59.616 39.749 63.558 40.325 ;
     RECT  0.108 38.765 0.162 40.397 ;
     RECT  60.3 40.325 63.558 40.397 ;
     RECT  55.296 40.297 57.33 40.433 ;
     RECT  61.056 40.397 63.558 40.559 ;
     RECT  61.056 40.559 62.982 40.595 ;
     RECT  1.764 39.865 54.558 40.639 ;
     RECT  55.296 40.433 57.294 40.639 ;
     RECT  62.964 40.595 62.982 40.667 ;
     RECT  64.548 38.579 64.782 40.703 ;
     RECT  60.3 40.397 60.318 40.829 ;
     RECT  61.344 40.595 62.097 40.829 ;
     RECT  64.764 40.703 64.782 40.829 ;
     RECT  61.776 40.829 62.097 40.865 ;
     RECT  1.764 40.639 57.294 40.877 ;
     RECT  1.764 40.877 57.15 41.135 ;
     RECT  58.212 40.981 58.23 41.243 ;
     RECT  2.415 41.135 57.15 41.513 ;
     RECT  0.108 40.397 0.126 41.747 ;
     RECT  2.415 41.513 31.662 42.089 ;
     RECT  22.752 42.089 31.662 42.331 ;
     RECT  32.4 41.513 57.15 42.331 ;
     RECT  2.415 42.089 22.014 42.719 ;
     RECT  22.752 42.331 57.15 42.719 ;
     RECT  2.415 42.719 3.15 42.749 ;
     RECT  3.888 42.719 22.014 42.835 ;
     RECT  22.752 42.719 42.75 42.835 ;
     RECT  43.488 42.719 57.15 43.141 ;
     RECT  3.888 42.835 42.75 43.501 ;
     RECT  43.488 43.141 57.294 43.501 ;
     RECT  3.888 43.501 57.294 43.681 ;
     RECT  3.888 43.681 57.402 43.771 ;
     RECT  3.888 43.771 57.546 44.185 ;
     RECT  3.888 44.185 57.87 44.339 ;
     RECT  2.415 42.749 2.697 44.443 ;
     RECT  3.888 44.339 28.314 44.477 ;
     RECT  2.415 44.443 2.97 44.915 ;
     RECT  3.996 44.477 28.314 44.915 ;
     RECT  4.032 44.915 28.314 45.185 ;
     RECT  4.104 45.185 28.314 45.193 ;
     RECT  29.088 44.339 57.15 45.193 ;
     RECT  4.104 45.193 57.15 45.221 ;
     RECT  27.936 45.221 57.15 45.869 ;
     RECT  27.936 45.869 33.102 45.959 ;
     RECT  4.104 45.221 27.126 46.003 ;
     RECT  27.936 45.959 32.958 46.003 ;
     RECT  33.876 45.869 57.15 46.109 ;
     RECT  4.104 46.003 32.958 46.111 ;
     RECT  3.996 46.111 32.958 46.345 ;
     RECT  3.852 46.345 32.958 46.381 ;
     RECT  33.876 46.109 56.754 46.741 ;
     RECT  3.636 46.381 32.958 46.747 ;
     RECT  33.804 46.741 56.754 46.747 ;
     RECT  3.636 46.747 56.754 46.885 ;
     RECT  3.492 46.885 56.754 46.913 ;
     RECT  3.492 46.913 23.094 46.925 ;
     RECT  23.976 46.913 56.754 47.695 ;
     RECT  3.744 46.925 23.094 47.731 ;
     RECT  23.904 47.695 56.754 47.821 ;
     RECT  2.415 44.915 2.697 47.965 ;
     RECT  3.744 47.731 23.13 47.965 ;
     RECT  23.904 47.821 56.826 47.965 ;
     RECT  3.744 47.965 56.826 48.229 ;
     RECT  3.744 48.229 56.862 48.269 ;
     RECT  2.415 47.965 2.862 48.425 ;
     RECT  57.78 48.271 57.798 48.461 ;
     RECT  3.744 48.269 56.697 49.073 ;
     RECT  4.032 49.073 56.697 49.565 ;
     RECT  4.248 49.565 56.697 50.323 ;
     RECT  4.14 50.323 56.697 50.701 ;
     RECT  4.068 50.701 56.697 50.935 ;
     RECT  4.068 50.935 56.97 50.971 ;
     RECT  3.816 50.971 56.97 51.019 ;
     RECT  3.672 51.019 56.97 51.089 ;
     RECT  4.212 51.089 56.97 51.359 ;
     RECT  4.212 51.359 56.862 51.395 ;
     RECT  4.212 51.395 56.697 52.483 ;
     RECT  3.996 52.483 56.697 52.591 ;
     RECT  3.816 52.591 56.697 52.651 ;
     RECT  3.672 52.651 56.697 52.709 ;
     RECT  4.212 52.709 56.697 52.889 ;
     RECT  4.212 52.889 55.674 53.6 ;
     RECT  30.924 53.6 55.674 53.663 ;
     RECT  4.212 53.6 30.15 53.833 ;
     RECT  4.068 53.833 30.15 53.869 ;
     RECT  3.744 53.869 30.15 54.409 ;
     RECT  30.924 53.663 55.566 54.409 ;
     RECT  3.744 54.409 55.566 54.445 ;
     RECT  56.415 52.889 56.697 54.445 ;
     RECT  3.744 54.445 56.697 54.481 ;
     RECT  3.6 54.481 56.697 54.599 ;
     RECT  3.6 54.599 21.978 54.643 ;
     RECT  3.42 54.643 21.978 54.701 ;
     RECT  22.752 54.599 56.697 54.707 ;
     RECT  22.752 54.707 55.494 54.941 ;
     RECT  3.996 54.701 21.978 55.013 ;
     RECT  4.032 55.013 21.978 55.381 ;
     RECT  22.752 54.941 49.086 55.381 ;
     RECT  50.148 54.941 55.422 55.759 ;
     RECT  2.415 48.425 2.697 55.819 ;
     RECT  2.415 55.819 3.294 55.831 ;
     RECT  4.032 55.381 49.086 55.831 ;
     RECT  49.896 55.759 55.422 55.831 ;
     RECT  56.415 54.707 56.697 55.831 ;
     RECT  2.415 55.831 49.086 55.921 ;
     RECT  49.896 55.831 56.697 55.921 ;
     RECT  2.415 55.921 56.697 55.949 ;
     RECT  2.415 55.949 3.294 55.985 ;
     RECT  4.032 55.949 56.697 56.363 ;
     RECT  4.032 56.363 55.602 56.795 ;
     RECT  4.032 56.795 54.954 56.867 ;
     RECT  2.415 55.985 2.697 57.547 ;
     RECT  2.415 57.547 3.294 57.605 ;
     RECT  4.032 56.867 54.666 57.875 ;
     RECT  4.104 57.875 54.666 58.217 ;
     RECT  31.716 58.217 54.666 58.649 ;
     RECT  31.716 58.649 54.414 58.829 ;
     RECT  31.716 58.829 54.306 58.955 ;
     RECT  4.104 58.217 30.87 59.035 ;
     RECT  31.716 58.955 54.126 59.071 ;
     RECT  4.068 59.035 30.87 59.233 ;
     RECT  31.644 59.071 54.126 59.233 ;
     RECT  4.068 59.233 54.126 59.603 ;
     RECT  4.104 59.603 54.126 59.729 ;
     RECT  4.104 59.729 52.326 59.789 ;
     RECT  4.104 59.789 52.038 59.885 ;
     RECT  4.104 59.885 33.318 59.909 ;
     RECT  53.208 59.729 54.126 59.909 ;
     RECT  4.248 59.909 33.318 59.999 ;
     RECT  53.28 59.909 54.126 60.035 ;
     RECT  18.324 59.999 33.318 60.071 ;
     RECT  53.28 60.035 53.514 60.107 ;
     RECT  18.54 60.071 33.246 60.305 ;
     RECT  53.28 60.107 53.298 60.305 ;
     RECT  34.2 59.885 52.038 60.413 ;
     RECT  34.2 60.413 50.202 60.691 ;
     RECT  4.248 59.999 17.154 60.719 ;
     RECT  4.356 60.719 17.154 60.845 ;
     RECT  4.5 60.845 17.154 60.881 ;
     RECT  31.464 60.305 33.246 60.961 ;
     RECT  34.164 60.691 50.202 60.961 ;
     RECT  5.148 60.881 17.154 61.115 ;
     RECT  18.54 60.305 30.618 61.195 ;
     RECT  31.464 60.961 50.202 61.195 ;
     RECT  50.976 60.413 52.038 61.223 ;
     RECT  5.328 61.115 17.154 61.229 ;
     RECT  18.54 61.195 50.202 61.231 ;
     RECT  50.976 61.223 51.354 61.231 ;
     RECT  18.108 61.231 51.354 61.457 ;
     RECT  5.328 61.229 17.01 61.493 ;
     RECT  18.54 61.457 51.354 61.517 ;
     RECT  5.328 61.493 16.038 61.529 ;
     RECT  5.328 61.529 15.678 61.619 ;
     RECT  18.54 61.517 41.958 61.655 ;
     RECT  42.768 61.517 51.354 61.727 ;
     RECT  5.328 61.619 15.534 61.799 ;
     RECT  50.112 61.727 51.354 61.799 ;
     RECT  6.552 61.799 15.534 61.889 ;
     RECT  18.615 61.655 41.958 61.889 ;
     RECT  50.22 61.799 51.354 61.889 ;
     RECT  5.328 61.799 5.814 61.901 ;
     RECT  5.364 61.901 5.814 61.925 ;
     RECT  6.552 61.889 8.19 61.925 ;
     RECT  34.524 61.889 41.958 61.925 ;
     RECT  5.472 61.925 5.814 61.961 ;
     RECT  34.704 61.925 41.958 61.961 ;
     RECT  5.472 61.961 5.742 62.033 ;
     RECT  18.615 61.889 33.678 62.033 ;
     RECT  34.704 61.961 41.886 62.033 ;
     RECT  42.768 61.727 46.53 62.045 ;
     RECT  5.724 62.033 5.742 62.069 ;
     RECT  6.624 61.925 8.19 62.069 ;
     RECT  18.615 62.033 25.866 62.069 ;
     RECT  39.924 62.033 41.886 62.069 ;
     RECT  42.768 62.045 43.002 62.069 ;
     RECT  43.992 62.045 46.53 62.069 ;
     RECT  47.448 61.727 49.302 62.069 ;
     RECT  34.704 62.033 38.79 62.141 ;
     RECT  6.624 62.069 8.154 62.159 ;
     RECT  8.928 61.889 15.534 62.159 ;
     RECT  18.615 62.069 22.518 62.159 ;
     RECT  23.328 62.069 25.866 62.159 ;
     RECT  26.856 62.033 33.678 62.159 ;
     RECT  36.576 62.141 38.79 62.159 ;
     RECT  40.176 62.069 41.742 62.159 ;
     RECT  42.804 62.069 43.002 62.159 ;
     RECT  48.204 62.069 49.302 62.159 ;
     RECT  8.928 62.159 8.946 62.195 ;
     RECT  10.08 62.159 11.79 62.195 ;
     RECT  12.708 62.159 13.497 62.195 ;
     RECT  14.4 62.159 15.534 62.195 ;
     RECT  20.772 62.159 22.518 62.195 ;
     RECT  26.856 62.159 26.874 62.195 ;
     RECT  27.684 62.159 31.518 62.195 ;
     RECT  34.704 62.141 35.514 62.195 ;
     RECT  36.576 62.159 36.594 62.195 ;
     RECT  40.176 62.159 41.634 62.195 ;
     RECT  44.46 62.069 46.53 62.195 ;
     RECT  47.448 62.069 47.466 62.195 ;
     RECT  48.276 62.159 49.302 62.195 ;
     RECT  6.624 62.159 8.097 62.231 ;
     RECT  11.16 62.195 11.178 62.231 ;
     RECT  37.728 62.159 38.79 62.231 ;
     RECT  44.532 62.195 46.422 62.231 ;
     RECT  31.356 62.195 31.518 62.237 ;
     RECT  6.624 62.231 6.75 62.267 ;
     RECT  34.815 62.195 35.298 62.267 ;
     RECT  6.624 62.267 6.642 62.303 ;
     RECT  10.08 62.195 10.422 62.303 ;
     RECT  31.356 62.237 31.41 62.303 ;
     RECT  37.728 62.231 38.682 62.303 ;
     RECT  40.176 62.195 41.202 62.303 ;
     RECT  44.532 62.231 46.062 62.303 ;
     RECT  15.372 62.195 15.534 62.312 ;
     RECT  20.772 62.195 22.482 62.339 ;
     RECT  24.015 62.159 25.866 62.339 ;
     RECT  28.368 62.195 30.006 62.339 ;
     RECT  37.728 62.303 38.43 62.339 ;
     RECT  48.276 62.195 49.05 62.339 ;
     RECT  2.415 57.605 2.697 62.387 ;
     RECT  7.815 62.231 8.097 62.387 ;
     RECT  13.215 62.195 13.497 62.387 ;
     RECT  24.015 62.339 24.297 62.387 ;
     RECT  34.815 62.267 35.097 62.387 ;
     RECT  40.215 62.303 41.202 62.387 ;
     RECT  44.532 62.303 45.897 62.387 ;
     RECT  50.22 61.889 51.297 62.387 ;
     RECT  56.415 56.363 56.697 62.387 ;
     RECT  61.815 40.865 62.097 62.387 ;
     RECT  15.408 62.312 15.534 62.429 ;
     RECT  20.772 62.339 21.798 62.429 ;
     RECT  25.164 62.339 25.866 62.429 ;
     RECT  28.368 62.339 29.754 62.429 ;
     RECT  31.392 62.303 31.41 62.429 ;
     RECT  32.4 62.159 33.678 62.429 ;
     RECT  37.728 62.339 37.89 62.429 ;
     RECT  41.112 62.387 41.202 62.429 ;
     RECT  42.804 62.159 42.93 62.429 ;
     RECT  44.532 62.387 45.774 62.429 ;
     RECT  50.22 62.387 51.174 62.429 ;
     RECT  15.408 62.429 15.426 62.465 ;
     RECT  18.615 62.159 20.034 62.465 ;
     RECT  20.772 62.429 20.79 62.465 ;
     RECT  28.368 62.429 28.386 62.465 ;
     RECT  29.232 62.429 29.574 62.465 ;
     RECT  41.112 62.429 41.13 62.465 ;
     RECT  42.804 62.429 42.822 62.465 ;
     RECT  48.276 62.339 48.33 62.465 ;
     RECT  50.22 62.429 50.238 62.465 ;
     RECT  19.836 62.465 20.034 62.501 ;
     RECT  32.508 62.429 32.526 62.501 ;
     RECT  45.036 62.429 45.705 62.501 ;
     RECT  25.848 62.429 25.866 62.573 ;
     RECT  33.66 62.429 33.678 62.573 ;
     RECT  37.872 62.429 37.89 62.573 ;
     RECT  20.016 62.501 20.034 62.609 ;
     RECT  48.276 62.465 48.294 62.609 ;
     RECT  2.415 62.387 2.505 62.657 ;
     RECT  7.815 62.387 7.905 62.657 ;
     RECT  13.215 62.387 13.305 62.657 ;
     RECT  18.615 62.465 18.705 62.657 ;
     RECT  24.015 62.387 24.105 62.657 ;
     RECT  29.415 62.465 29.505 62.657 ;
     RECT  34.815 62.387 34.905 62.657 ;
     RECT  40.215 62.387 40.305 62.657 ;
     RECT  45.615 62.501 45.705 62.657 ;
     RECT  51.015 62.429 51.105 62.657 ;
     RECT  56.415 62.387 56.505 62.657 ;
     RECT  61.815 62.387 61.905 62.657 ;
    LAYER M4 ;
     RECT  0.06 24.528 0.133 40.2 ;
     RECT  0.133 24.528 0.209 40.392 ;
     RECT  0.209 24.624 2.408 40.392 ;
     RECT  2.408 2.148 2.512 62.652 ;
     RECT  2.512 2.418 2.704 62.382 ;
     RECT  2.704 24.72 2.837 42.744 ;
     RECT  2.837 25.056 2.867 42.744 ;
     RECT  2.867 25.056 3.197 40.824 ;
     RECT  3.197 25.056 3.269 39.768 ;
     RECT  3.269 25.056 3.305 37.656 ;
     RECT  3.305 25.056 3.341 28.296 ;
     RECT  3.341 25.056 3.347 28.008 ;
     RECT  3.305 29.328 3.377 37.656 ;
     RECT  3.269 38.736 3.377 39.768 ;
     RECT  3.377 31.92 3.413 37.656 ;
     RECT  3.377 39.024 3.413 39.768 ;
     RECT  2.867 42.192 3.443 42.744 ;
     RECT  3.413 31.92 3.449 34.872 ;
     RECT  3.413 39.216 3.485 39.768 ;
     RECT  3.449 34.704 3.701 34.872 ;
     RECT  2.704 46.896 3.733 46.92 ;
     RECT  3.733 46.896 3.841 47.88 ;
     RECT  2.704 23.376 3.913 23.736 ;
     RECT  3.913 23.376 3.98 24.072 ;
     RECT  3.98 23.376 4.021 24.408 ;
     RECT  4.021 22.848 4.133 24.408 ;
     RECT  3.701 34.704 4.133 34.728 ;
     RECT  4.133 22.848 4.169 23.4 ;
     RECT  2.704 55.824 4.201 55.848 ;
     RECT  4.021 49.536 4.237 49.56 ;
     RECT  3.841 46.368 4.273 47.88 ;
     RECT  2.704 54.672 4.273 54.696 ;
     RECT  4.201 55.824 4.273 56.328 ;
     RECT  3.347 25.584 4.345 28.008 ;
     RECT  3.377 29.328 4.345 30.936 ;
     RECT  2.704 44.448 4.357 44.472 ;
     RECT  4.273 46.368 4.381 48.168 ;
     RECT  4.381 46.272 4.403 48.168 ;
     RECT  4.273 54.672 4.412 56.328 ;
     RECT  2.704 57.552 4.412 57.576 ;
     RECT  4.133 24.384 4.417 24.408 ;
     RECT  4.345 25.584 4.417 30.936 ;
     RECT  3.443 42.72 4.417 42.744 ;
     RECT  3.197 40.8 4.453 40.824 ;
     RECT  4.417 42.144 4.453 42.744 ;
     RECT  4.381 59.856 4.453 59.88 ;
     RECT  4.453 40.8 4.489 42.744 ;
     RECT  4.357 44.352 4.489 44.472 ;
     RECT  4.412 54.672 4.493 57.576 ;
     RECT  4.493 54.672 4.499 57.288 ;
     RECT  4.417 24.384 4.529 30.936 ;
     RECT  4.499 54.672 4.529 56.328 ;
     RECT  4.453 7.968 4.561 8.52 ;
     RECT  2.704 51.024 4.561 51.048 ;
     RECT  4.529 54.864 4.565 56.328 ;
     RECT  4.561 7.104 4.597 8.52 ;
     RECT  4.169 22.848 4.597 22.872 ;
     RECT  4.529 29.664 4.597 30.936 ;
     RECT  3.449 31.92 4.597 33.528 ;
     RECT  2.704 52.656 4.633 52.68 ;
     RECT  4.597 7.104 4.643 9.192 ;
     RECT  4.597 29.664 4.669 33.528 ;
     RECT  4.633 52.656 4.7 53.592 ;
     RECT  4.597 22.8 4.709 22.872 ;
     RECT  4.237 49.536 4.741 49.752 ;
     RECT  4.561 50.736 4.741 51.048 ;
     RECT  4.7 52.128 4.741 53.592 ;
     RECT  4.489 40.8 4.777 44.472 ;
     RECT  4.741 49.536 4.787 51.048 ;
     RECT  3.485 39.216 4.789 39.672 ;
     RECT  4.777 40.8 4.789 44.76 ;
     RECT  4.643 7.104 4.813 7.992 ;
     RECT  3.413 36.288 4.849 37.656 ;
     RECT  4.741 52.128 4.849 53.784 ;
     RECT  4.787 49.536 4.925 50.712 ;
     RECT  4.921 13.056 4.988 13.08 ;
     RECT  4.453 59.856 4.988 60.264 ;
     RECT  4.921 14.688 5.029 14.712 ;
     RECT  4.988 12.48 5.075 13.08 ;
     RECT  4.565 54.864 5.075 56.28 ;
     RECT  4.988 59.712 5.075 60.264 ;
     RECT  4.633 10.608 5.101 10.632 ;
     RECT  4.403 46.272 5.125 47.88 ;
     RECT  4.849 36.24 5.137 37.656 ;
     RECT  4.789 39.216 5.137 44.76 ;
     RECT  4.849 51.888 5.149 53.784 ;
     RECT  5.029 14.352 5.173 14.712 ;
     RECT  4.669 15.888 5.173 15.912 ;
     RECT  4.709 22.848 5.173 22.872 ;
     RECT  5.173 14.352 5.209 16.008 ;
     RECT  5.125 46.224 5.213 47.88 ;
     RECT  5.075 12.72 5.221 13.08 ;
     RECT  5.221 12.72 5.267 12.888 ;
     RECT  5.137 36.24 5.285 44.76 ;
     RECT  4.669 29.664 5.317 33.576 ;
     RECT  5.075 59.856 5.317 60.264 ;
     RECT  4.813 6.288 5.321 7.992 ;
     RECT  5.173 22.848 5.353 23.352 ;
     RECT  4.529 24.384 5.353 28.584 ;
     RECT  5.285 39.888 5.353 44.76 ;
     RECT  5.209 14.352 5.357 16.632 ;
     RECT  5.353 39.888 5.393 45.048 ;
     RECT  5.149 51.888 5.393 51.912 ;
     RECT  4.643 8.976 5.42 9.192 ;
     RECT  5.101 10.608 5.42 11.064 ;
     RECT  5.317 29.664 5.497 33.72 ;
     RECT  4.925 49.536 5.501 49.56 ;
     RECT  5.353 22.848 5.569 28.584 ;
     RECT  5.497 29.664 5.569 33.816 ;
     RECT  5.285 36.24 5.573 38.808 ;
     RECT  5.42 8.976 5.605 11.064 ;
     RECT  5.149 53.28 5.677 53.784 ;
     RECT  5.573 36.336 5.717 38.808 ;
     RECT  5.393 40.368 5.753 45.048 ;
     RECT  5.357 14.688 5.789 16.632 ;
     RECT  5.677 35.04 5.821 35.064 ;
     RECT  5.213 46.224 5.852 47.16 ;
     RECT  5.389 18.288 5.929 18.312 ;
     RECT  5.605 8.976 5.933 11.544 ;
     RECT  5.852 46.08 5.939 47.16 ;
     RECT  5.569 22.848 5.941 33.816 ;
     RECT  5.941 22.176 6.001 33.816 ;
     RECT  5.893 58.704 6.001 58.728 ;
     RECT  5.569 49.248 6.044 49.272 ;
     RECT  6.001 22.176 6.109 33.912 ;
     RECT  5.821 35.04 6.109 35.352 ;
     RECT  6.109 22.176 6.113 35.352 ;
     RECT  5.075 55.296 6.185 56.28 ;
     RECT  4.925 50.64 6.253 50.712 ;
     RECT  5.753 43.056 6.257 45.048 ;
     RECT  5.321 6.288 6.325 7.368 ;
     RECT  5.677 53.28 6.325 54.216 ;
     RECT  6.185 55.296 6.325 55.896 ;
     RECT  6.325 6.288 6.397 7.416 ;
     RECT  5.753 40.368 6.397 41.784 ;
     RECT  6.044 49.2 6.505 49.272 ;
     RECT  6.476 56.88 6.563 56.904 ;
     RECT  6.145 19.968 6.565 19.992 ;
     RECT  6.397 6.288 6.577 7.8 ;
     RECT  5.929 17.616 6.577 18.312 ;
     RECT  5.317 61.872 6.581 61.896 ;
     RECT  6.113 22.752 6.611 35.352 ;
     RECT  6.577 5.952 6.613 7.8 ;
     RECT  6.611 26.256 6.613 35.352 ;
     RECT  5.717 36.336 6.613 38.568 ;
     RECT  6.613 26.256 6.653 38.568 ;
     RECT  5.789 14.784 6.721 16.632 ;
     RECT  6.577 17.616 6.721 18.408 ;
     RECT  6.613 5.616 6.757 7.8 ;
     RECT  6.721 14.784 6.761 18.456 ;
     RECT  6.325 53.28 6.821 55.896 ;
     RECT  5.267 12.864 6.829 12.888 ;
     RECT  6.397 39.696 6.833 41.784 ;
     RECT  6.505 48.96 6.865 49.272 ;
     RECT  6.253 50.64 6.865 51.624 ;
     RECT  6.001 58.08 6.865 58.728 ;
     RECT  6.565 19.968 6.901 20.328 ;
     RECT  6.761 14.784 6.937 16.728 ;
     RECT  6.829 12.816 6.973 12.888 ;
     RECT  6.937 14.496 6.973 16.728 ;
     RECT  6.865 58.032 6.973 58.728 ;
     RECT  6.973 57.984 7.009 58.728 ;
     RECT  6.653 30.576 7.081 38.568 ;
     RECT  6.833 39.696 7.081 41.736 ;
     RECT  6.865 48.96 7.093 51.624 ;
     RECT  6.257 43.104 7.148 45.048 ;
     RECT  5.939 46.224 7.148 47.16 ;
     RECT  5.821 4.512 7.153 4.536 ;
     RECT  6.757 5.616 7.153 7.848 ;
     RECT  7.153 4.512 7.196 7.848 ;
     RECT  7.237 3.408 7.261 3.432 ;
     RECT  7.196 4.416 7.261 7.848 ;
     RECT  6.469 21.456 7.261 21.48 ;
     RECT  6.611 22.752 7.261 25.176 ;
     RECT  7.093 48.528 7.261 51.624 ;
     RECT  7.261 3.408 7.441 7.848 ;
     RECT  5.933 8.976 7.441 10.728 ;
     RECT  7.441 3.408 7.549 10.728 ;
     RECT  6.653 26.256 7.621 29.544 ;
     RECT  7.081 30.576 7.621 41.736 ;
     RECT  7.549 3.408 7.649 11.16 ;
     RECT  6.821 52.992 7.669 55.896 ;
     RECT  5.317 59.856 7.801 60.408 ;
     RECT  7.649 3.408 7.808 11.448 ;
     RECT  6.973 12.816 7.808 16.728 ;
     RECT  6.761 18.144 7.808 18.456 ;
     RECT  6.901 19.632 7.808 20.328 ;
     RECT  7.261 21.456 7.808 25.176 ;
     RECT  7.621 26.256 7.808 41.736 ;
     RECT  7.148 43.104 7.808 47.16 ;
     RECT  7.261 48.48 7.808 51.624 ;
     RECT  7.669 52.992 7.808 56.52 ;
     RECT  7.009 57.84 7.808 58.728 ;
     RECT  7.801 59.856 7.808 60.84 ;
     RECT  7.808 2.148 7.912 62.652 ;
     RECT  7.912 2.418 8.104 62.382 ;
     RECT  8.104 16.512 8.165 16.632 ;
     RECT  8.104 9.792 8.243 14.76 ;
     RECT  8.104 5.76 8.273 8.76 ;
     RECT  8.104 56.496 8.291 60.84 ;
     RECT  8.291 59.856 8.339 60.84 ;
     RECT  8.104 17.616 8.387 23.4 ;
     RECT  8.104 52.8 8.417 55.512 ;
     RECT  8.387 17.616 8.489 18.312 ;
     RECT  8.291 56.496 8.489 58.728 ;
     RECT  8.489 56.496 8.525 57.576 ;
     RECT  8.104 3.408 8.561 4.68 ;
     RECT  8.165 16.512 8.741 16.584 ;
     RECT  8.417 52.8 8.777 54.648 ;
     RECT  8.104 42.624 8.867 51.624 ;
     RECT  8.867 42.624 8.915 49.608 ;
     RECT  8.777 52.8 9.065 54.456 ;
     RECT  8.387 19.488 9.097 23.4 ;
     RECT  8.867 50.736 9.133 51.624 ;
     RECT  9.065 52.8 9.133 54.264 ;
     RECT  8.104 24.528 9.137 41.544 ;
     RECT  8.915 42.624 9.173 49.512 ;
     RECT  8.489 58.704 9.173 58.728 ;
     RECT  8.243 10.128 9.245 14.76 ;
     RECT  8.339 60.336 9.277 60.84 ;
     RECT  9.137 36.528 9.349 41.544 ;
     RECT  9.173 42.624 9.349 45.576 ;
     RECT  9.097 19.488 9.353 23.448 ;
     RECT  9.133 50.736 9.353 54.264 ;
     RECT  8.561 3.408 9.389 4.008 ;
     RECT  8.741 16.512 9.421 16.536 ;
     RECT  9.353 21.456 9.529 23.448 ;
     RECT  9.137 24.528 9.529 32.856 ;
     RECT  8.525 56.736 9.541 57.576 ;
     RECT  9.389 3.648 9.569 4.008 ;
     RECT  9.541 56.592 9.628 57.576 ;
     RECT  8.273 5.76 9.637 6.84 ;
     RECT  8.273 7.968 9.637 8.52 ;
     RECT  9.569 3.984 9.641 4.008 ;
     RECT  9.637 5.76 9.781 8.52 ;
     RECT  8.489 18.288 9.853 18.312 ;
     RECT  9.277 60.336 9.857 61.656 ;
     RECT  9.857 60.336 9.929 61.032 ;
     RECT  9.173 46.56 9.965 49.512 ;
     RECT  9.853 17.664 10.033 18.312 ;
     RECT  9.353 19.488 10.033 20.328 ;
     RECT  9.137 33.888 10.177 35.016 ;
     RECT  9.245 10.32 10.241 11.16 ;
     RECT  9.245 12.192 10.241 14.76 ;
     RECT  10.177 33.888 10.249 35.16 ;
     RECT  9.349 36.528 10.249 45.576 ;
     RECT  9.965 46.56 10.325 49.464 ;
     RECT  9.781 5.76 10.357 9.096 ;
     RECT  10.249 33.888 10.451 45.576 ;
     RECT  9.529 21.456 10.465 32.856 ;
     RECT  10.451 33.888 10.465 33.912 ;
     RECT  10.451 35.136 10.465 45.576 ;
     RECT  10.325 46.56 10.465 49.224 ;
     RECT  10.465 21.456 10.469 33.912 ;
     RECT  9.421 16.416 10.573 16.536 ;
     RECT  10.465 35.136 10.577 49.224 ;
     RECT  10.645 55.488 10.681 55.512 ;
     RECT  9.353 51.216 10.685 54.264 ;
     RECT  10.033 17.664 10.717 20.328 ;
     RECT  10.469 21.456 10.717 33.528 ;
     RECT  10.717 17.664 10.757 33.528 ;
     RECT  10.685 52.944 10.757 54.264 ;
     RECT  10.241 10.32 10.825 14.76 ;
     RECT  10.577 35.136 10.829 37.32 ;
     RECT  10.577 38.544 10.835 49.224 ;
     RECT  9.628 56.736 10.861 57.576 ;
     RECT  10.757 17.664 10.865 33.192 ;
     RECT  10.685 51.216 10.865 51.72 ;
     RECT  10.825 10.32 10.885 15.096 ;
     RECT  10.573 16.368 10.885 16.536 ;
     RECT  10.885 10.32 10.931 16.536 ;
     RECT  10.931 13.584 10.933 16.536 ;
     RECT  10.865 17.664 10.933 29.928 ;
     RECT  10.357 5.76 10.937 9.144 ;
     RECT  10.835 40.032 10.937 49.224 ;
     RECT  10.865 51.216 10.943 51.384 ;
     RECT  10.757 52.992 10.969 54.264 ;
     RECT  10.681 55.392 10.969 55.512 ;
     RECT  10.717 3.072 11.029 3.096 ;
     RECT  11.029 2.64 11.116 3.096 ;
     RECT  9.929 60.384 11.117 61.032 ;
     RECT  10.969 52.992 11.149 55.512 ;
     RECT  10.861 56.736 11.149 57.768 ;
     RECT  10.937 40.032 11.189 45.576 ;
     RECT  11.189 40.032 11.225 41.544 ;
     RECT  11.116 2.88 11.293 3.096 ;
     RECT  10.937 6.864 11.365 9.144 ;
     RECT  10.931 10.32 11.365 12.552 ;
     RECT  11.293 2.88 11.372 3.672 ;
     RECT  11.365 6.864 11.441 12.552 ;
     RECT  10.933 13.584 11.441 29.928 ;
     RECT  11.189 42.624 11.441 45.576 ;
     RECT  11.441 42.768 11.459 45.576 ;
     RECT  11.372 2.88 11.473 3.72 ;
     RECT  10.249 59.04 11.509 59.064 ;
     RECT  10.835 38.544 11.513 39.048 ;
     RECT  11.509 58.944 11.549 59.064 ;
     RECT  11.441 13.68 11.621 16.44 ;
     RECT  11.441 17.472 11.621 29.928 ;
     RECT  11.473 2.88 11.689 4.248 ;
     RECT  10.937 5.76 11.689 5.784 ;
     RECT  11.513 38.544 11.689 38.664 ;
     RECT  11.441 12.288 11.729 12.552 ;
     RECT  10.943 50.256 11.729 51.384 ;
     RECT  11.149 52.992 11.797 57.768 ;
     RECT  11.117 60.816 11.941 61.032 ;
     RECT  11.459 43.344 11.981 45.576 ;
     RECT  11.797 52.464 12.013 57.768 ;
     RECT  10.829 35.136 12.049 37.224 ;
     RECT  10.937 46.752 12.053 49.224 ;
     RECT  12.013 52.224 12.053 57.768 ;
     RECT  12.049 34.368 12.092 37.224 ;
     RECT  12.092 34.32 12.121 37.224 ;
     RECT  11.689 38.256 12.121 38.664 ;
     RECT  12.053 46.8 12.188 49.224 ;
     RECT  11.729 50.256 12.188 51.24 ;
     RECT  10.865 31.2 12.337 33.192 ;
     RECT  12.121 34.32 12.337 38.664 ;
     RECT  11.621 23.328 12.373 29.928 ;
     RECT  12.337 31.2 12.373 38.664 ;
     RECT  11.225 40.032 12.409 41.496 ;
     RECT  12.053 55.536 12.409 57.768 ;
     RECT  11.941 60.816 12.409 61.56 ;
     RECT  12.409 40.032 12.481 41.688 ;
     RECT  12.188 46.8 12.697 51.24 ;
     RECT  12.053 52.224 12.697 54.552 ;
     RECT  11.549 58.944 12.697 58.968 ;
     RECT  12.409 60.816 12.697 61.608 ;
     RECT  11.621 13.872 12.733 16.44 ;
     RECT  12.373 23.328 12.733 38.664 ;
     RECT  11.621 17.472 12.805 22.056 ;
     RECT  12.733 23.328 12.805 38.712 ;
     RECT  12.697 58.944 12.877 61.608 ;
     RECT  11.729 12.288 12.985 12.504 ;
     RECT  12.733 13.728 12.985 16.44 ;
     RECT  12.481 40.032 13.021 41.784 ;
     RECT  12.697 46.8 13.021 54.552 ;
     RECT  12.409 55.536 13.021 57.912 ;
     RECT  12.805 17.472 13.057 38.712 ;
     RECT  13.021 40.032 13.057 42.024 ;
     RECT  12.985 12.288 13.093 16.44 ;
     RECT  13.057 17.472 13.093 42.024 ;
     RECT  11.689 2.88 13.208 5.784 ;
     RECT  11.441 6.864 13.208 11.208 ;
     RECT  13.093 12.288 13.208 42.024 ;
     RECT  11.981 43.44 13.208 45.576 ;
     RECT  13.021 46.8 13.208 57.96 ;
     RECT  12.877 58.944 13.208 62.184 ;
     RECT  13.208 2.148 13.312 62.652 ;
     RECT  13.312 2.418 13.504 62.382 ;
     RECT  13.504 43.824 13.619 58.008 ;
     RECT  13.504 3.648 13.637 13.128 ;
     RECT  13.504 14.592 13.637 19.56 ;
     RECT  13.637 14.592 13.673 16.392 ;
     RECT  13.619 56.448 13.673 58.008 ;
     RECT  13.504 36.528 13.709 42.792 ;
     RECT  13.619 43.824 13.715 55.272 ;
     RECT  13.637 17.472 13.781 19.56 ;
     RECT  13.715 43.824 13.781 45.576 ;
     RECT  13.715 46.896 13.781 55.272 ;
     RECT  13.709 41.232 13.817 42.792 ;
     RECT  13.504 59.856 13.817 60.696 ;
     RECT  13.781 46.896 13.853 55.176 ;
     RECT  13.637 3.648 13.859 12.984 ;
     RECT  13.853 46.896 13.859 49.8 ;
     RECT  13.781 17.472 13.925 19.032 ;
     RECT  13.859 46.896 13.925 49.608 ;
     RECT  13.709 36.528 14.249 40.152 ;
     RECT  13.817 41.232 14.285 41.784 ;
     RECT  13.504 62.16 14.493 62.184 ;
     RECT  13.817 60.528 14.569 60.696 ;
     RECT  13.859 3.648 14.668 12.936 ;
     RECT  13.673 14.688 14.677 16.392 ;
     RECT  13.925 17.472 14.677 18.552 ;
     RECT  14.569 60.528 14.677 60.936 ;
     RECT  14.668 5.088 14.689 12.936 ;
     RECT  13.504 20.64 14.713 35.496 ;
     RECT  14.249 36.528 14.713 37.656 ;
     RECT  14.249 38.736 14.749 40.152 ;
     RECT  14.285 41.232 14.749 41.736 ;
     RECT  14.677 60.528 14.78 60.984 ;
     RECT  13.817 42.768 14.785 42.792 ;
     RECT  14.78 59.76 14.785 60.984 ;
     RECT  14.713 20.64 14.821 37.656 ;
     RECT  13.853 51.36 14.821 55.176 ;
     RECT  14.785 59.76 14.867 61.224 ;
     RECT  14.689 5.616 14.893 12.936 ;
     RECT  14.821 20.448 14.897 37.656 ;
     RECT  14.785 42.768 15.009 43.512 ;
     RECT  13.781 44.592 15.009 45.576 ;
     RECT  14.821 51.216 15.109 55.176 ;
     RECT  14.749 38.736 15.113 41.736 ;
     RECT  14.897 20.448 15.185 37.32 ;
     RECT  14.867 60.528 15.185 61.224 ;
     RECT  15.113 40.992 15.325 41.736 ;
     RECT  15.009 42.768 15.325 45.576 ;
     RECT  15.325 40.992 15.397 45.576 ;
     RECT  13.673 57.024 15.397 58.008 ;
     RECT  14.893 5.616 15.401 13.128 ;
     RECT  14.677 14.688 15.469 18.552 ;
     RECT  15.185 20.64 15.491 37.32 ;
     RECT  15.109 50.832 15.617 55.176 ;
     RECT  14.668 3.648 15.637 3.72 ;
     RECT  15.113 38.736 15.653 39.864 ;
     RECT  15.637 3.36 15.757 3.72 ;
     RECT  15.469 14.496 15.827 18.552 ;
     RECT  15.827 14.688 15.829 18.552 ;
     RECT  15.793 19.536 15.829 19.56 ;
     RECT  15.397 56.304 15.829 58.008 ;
     RECT  15.829 56.304 15.869 58.152 ;
     RECT  15.185 60.528 15.901 61.08 ;
     RECT  15.757 3.36 15.937 4.152 ;
     RECT  15.401 9.744 15.941 13.128 ;
     RECT  15.901 60.432 15.941 61.08 ;
     RECT  15.829 14.688 15.971 19.56 ;
     RECT  15.491 37.008 16.009 37.32 ;
     RECT  15.653 38.736 16.009 39.576 ;
     RECT  15.617 50.832 16.013 53.352 ;
     RECT  15.397 40.992 16.045 45.96 ;
     RECT  13.925 47.088 16.045 49.608 ;
     RECT  16.045 40.992 16.085 49.608 ;
     RECT  15.617 54.336 16.153 55.176 ;
     RECT  16.085 40.992 16.157 45.24 ;
     RECT  16.153 54.336 16.157 55.8 ;
     RECT  15.869 56.928 16.157 58.152 ;
     RECT  15.937 3.312 16.189 4.152 ;
     RECT  15.401 5.616 16.189 8.52 ;
     RECT  15.941 60.432 16.189 60.936 ;
     RECT  16.157 56.928 16.301 58.008 ;
     RECT  16.009 37.008 16.337 39.576 ;
     RECT  16.157 44.4 16.373 45.24 ;
     RECT  16.337 38.208 16.409 39.576 ;
     RECT  15.491 20.64 16.481 35.784 ;
     RECT  16.157 55.776 16.481 55.8 ;
     RECT  15.941 10.176 16.547 13.128 ;
     RECT  16.481 35.136 16.585 35.784 ;
     RECT  16.337 37.008 16.589 37.032 ;
     RECT  16.085 46.224 16.625 49.608 ;
     RECT  16.585 35.136 16.661 35.976 ;
     RECT  16.157 54.336 16.769 54.552 ;
     RECT  16.481 27.648 16.805 34.152 ;
     RECT  16.189 3.312 16.837 8.52 ;
     RECT  16.157 40.992 16.841 43.32 ;
     RECT  16.837 2.976 16.873 8.52 ;
     RECT  16.013 51.456 16.949 53.352 ;
     RECT  16.189 60.24 17.084 60.936 ;
     RECT  16.873 2.64 17.089 8.52 ;
     RECT  16.769 54.336 17.125 54.504 ;
     RECT  17.084 60.24 17.125 61.224 ;
     RECT  16.547 10.176 17.129 12.552 ;
     RECT  16.661 35.328 17.129 35.976 ;
     RECT  17.125 59.76 17.161 62.04 ;
     RECT  16.805 27.648 17.165 30.072 ;
     RECT  16.841 40.992 17.165 42.168 ;
     RECT  17.161 59.28 17.171 62.04 ;
     RECT  16.301 57.696 17.173 58.008 ;
     RECT  17.171 59.28 17.173 60.552 ;
     RECT  17.173 57.696 17.237 60.552 ;
     RECT  17.237 57.696 17.245 59.304 ;
     RECT  17.089 2.64 17.269 8.568 ;
     RECT  17.269 2.64 17.341 9.096 ;
     RECT  16.625 46.224 17.363 47.304 ;
     RECT  15.971 14.688 17.372 19.272 ;
     RECT  16.949 51.456 17.413 52.728 ;
     RECT  17.372 14.688 17.459 19.656 ;
     RECT  17.459 14.688 17.485 19.368 ;
     RECT  17.485 13.92 17.489 19.368 ;
     RECT  17.165 41.472 17.597 42.168 ;
     RECT  17.129 10.272 17.629 12.552 ;
     RECT  16.625 48.384 17.629 49.608 ;
     RECT  17.629 48.384 17.653 50.136 ;
     RECT  17.245 57.696 17.665 58.536 ;
     RECT  17.629 10.272 17.701 12.84 ;
     RECT  16.373 44.688 17.701 45.24 ;
     RECT  17.363 46.224 17.701 47.16 ;
     RECT  16.409 38.208 17.804 38.28 ;
     RECT  16.409 39.264 17.804 39.576 ;
     RECT  17.701 10.272 17.809 12.936 ;
     RECT  17.489 13.92 17.809 15.288 ;
     RECT  17.129 35.712 17.809 35.976 ;
     RECT  17.125 54.144 17.809 54.504 ;
     RECT  17.161 56.352 17.809 56.376 ;
     RECT  17.665 57.648 17.809 58.536 ;
     RECT  17.165 27.648 17.953 28.296 ;
     RECT  17.804 38.208 17.989 39.576 ;
     RECT  17.413 51.264 18.061 52.728 ;
     RECT  17.989 38.208 18.097 39.912 ;
     RECT  17.597 42 18.229 42.168 ;
     RECT  16.841 43.296 18.229 43.32 ;
     RECT  17.237 60.528 18.229 60.552 ;
     RECT  18.097 37.92 18.241 39.912 ;
     RECT  17.809 56.352 18.284 58.536 ;
     RECT  17.809 35.712 18.385 36.072 ;
     RECT  16.805 31.2 18.469 34.152 ;
     RECT  18.385 35.712 18.469 36.552 ;
     RECT  18.241 37.632 18.469 39.912 ;
     RECT  18.061 51.264 18.469 53.064 ;
     RECT  17.165 29.328 18.493 30.072 ;
     RECT  18.469 31.2 18.493 36.552 ;
     RECT  17.809 10.272 18.529 15.288 ;
     RECT  17.489 16.32 18.529 19.368 ;
     RECT  18.229 60.288 18.565 60.552 ;
     RECT  17.171 62.016 18.565 62.04 ;
     RECT  17.341 2.64 18.608 9.288 ;
     RECT  18.529 10.272 18.608 19.368 ;
     RECT  16.481 20.64 18.608 26.376 ;
     RECT  17.953 27.6 18.608 28.296 ;
     RECT  18.493 29.328 18.608 36.552 ;
     RECT  18.469 37.632 18.608 40.584 ;
     RECT  18.229 42 18.608 43.32 ;
     RECT  17.701 44.688 18.608 47.16 ;
     RECT  17.653 48.384 18.608 50.184 ;
     RECT  18.469 51.168 18.608 53.064 ;
     RECT  17.809 54.144 18.608 54.984 ;
     RECT  18.284 56.352 18.608 58.68 ;
     RECT  18.565 60.288 18.608 62.04 ;
     RECT  18.608 2.148 18.712 62.652 ;
     RECT  18.712 2.418 18.904 62.382 ;
     RECT  18.904 27.648 19.001 28.296 ;
     RECT  18.904 44.64 19.001 50.136 ;
     RECT  18.904 35.664 19.037 36.552 ;
     RECT  18.904 51.168 19.109 62.184 ;
     RECT  18.904 37.632 19.433 40.44 ;
     RECT  18.904 41.712 19.577 42.072 ;
     RECT  18.904 4.656 19.649 16.392 ;
     RECT  18.904 17.424 19.721 26.664 ;
     RECT  19.109 51.168 19.756 60.84 ;
     RECT  19.433 37.872 19.829 40.44 ;
     RECT  19.577 41.712 19.969 42.024 ;
     RECT  19.001 44.64 20.005 45.432 ;
     RECT  19.001 46.656 20.005 50.136 ;
     RECT  19.756 51.168 20.045 52.44 ;
     RECT  19.001 27.696 20.077 28.296 ;
     RECT  18.904 29.328 20.077 33.912 ;
     RECT  19.649 15.84 20.149 16.392 ;
     RECT  19.721 17.424 20.149 22.056 ;
     RECT  19.829 37.872 20.189 40.056 ;
     RECT  19.721 23.328 20.221 26.664 ;
     RECT  20.077 27.696 20.221 33.912 ;
     RECT  19.037 35.664 20.257 36.264 ;
     RECT  19.649 4.656 20.365 14.808 ;
     RECT  20.005 44.64 20.401 50.136 ;
     RECT  20.045 51.168 20.401 52.392 ;
     RECT  20.401 44.64 20.405 52.392 ;
     RECT  19.756 53.52 20.477 60.84 ;
     RECT  20.257 35.664 20.585 36.6 ;
     RECT  20.477 53.52 20.585 55.848 ;
     RECT  20.477 57.024 20.621 60.84 ;
     RECT  20.365 4.512 20.693 14.808 ;
     RECT  20.693 4.512 20.723 7.512 ;
     RECT  20.149 15.84 20.833 22.056 ;
     RECT  18.904 43.296 20.833 43.32 ;
     RECT  20.621 57.648 20.837 60.84 ;
     RECT  20.693 8.496 20.869 14.808 ;
     RECT  20.833 15.792 20.869 22.056 ;
     RECT  19.969 41.184 20.905 42.024 ;
     RECT  20.833 43.296 20.905 43.56 ;
     RECT  20.405 44.64 20.905 52.344 ;
     RECT  20.905 41.136 20.917 42.024 ;
     RECT  20.221 23.328 20.977 33.912 ;
     RECT  20.585 35.664 20.977 36.552 ;
     RECT  20.837 57.648 21.017 58.152 ;
     RECT  20.917 41.04 21.125 42.024 ;
     RECT  20.837 59.184 21.155 60.84 ;
     RECT  20.905 43.296 21.161 52.344 ;
     RECT  21.125 41.04 21.197 41.208 ;
     RECT  20.189 38.256 21.265 40.056 ;
     RECT  21.197 41.04 21.265 41.16 ;
     RECT  20.585 53.52 21.265 55.512 ;
     RECT  21.265 53.328 21.305 55.512 ;
     RECT  21.265 38.256 21.349 41.16 ;
     RECT  21.161 43.296 21.373 50.088 ;
     RECT  20.977 23.328 21.517 36.552 ;
     RECT  21.017 57.648 21.625 58.056 ;
     RECT  21.517 23.28 21.683 36.552 ;
     RECT  21.349 37.872 21.683 41.16 ;
     RECT  18.904 2.496 21.697 3.384 ;
     RECT  20.723 4.656 21.697 7.512 ;
     RECT  19.109 62.16 21.841 62.184 ;
     RECT  21.841 62.016 21.881 62.184 ;
     RECT  21.625 57.072 21.913 58.056 ;
     RECT  21.373 42.528 21.917 50.088 ;
     RECT  21.155 59.184 21.989 60.312 ;
     RECT  21.697 2.496 22.021 7.512 ;
     RECT  20.869 8.496 22.021 22.056 ;
     RECT  21.913 57.024 22.021 58.056 ;
     RECT  21.989 59.184 22.021 59.736 ;
     RECT  21.683 40.56 22.025 41.16 ;
     RECT  21.161 51.072 22.165 52.344 ;
     RECT  21.305 53.328 22.165 55.272 ;
     RECT  21.683 37.872 22.277 39.48 ;
     RECT  22.165 51.072 22.309 55.272 ;
     RECT  22.309 51.072 22.316 55.848 ;
     RECT  21.683 23.328 22.349 36.552 ;
     RECT  22.316 51.072 22.403 55.944 ;
     RECT  22.349 24.672 22.453 36.552 ;
     RECT  22.025 40.704 22.489 41.16 ;
     RECT  22.021 57.024 22.637 59.736 ;
     RECT  22.021 2.496 22.709 22.056 ;
     RECT  22.709 19.536 22.745 22.056 ;
     RECT  22.489 40.704 22.787 41.448 ;
     RECT  21.917 42.624 22.787 50.088 ;
     RECT  22.637 57.024 22.789 58.728 ;
     RECT  22.787 46.32 22.813 50.088 ;
     RECT  22.403 51.072 22.813 55.848 ;
     RECT  22.813 46.32 22.817 55.848 ;
     RECT  22.637 59.712 22.853 59.736 ;
     RECT  22.745 19.584 23.029 22.056 ;
     RECT  22.349 23.328 23.029 23.688 ;
     RECT  22.787 40.704 23.029 41.016 ;
     RECT  21.881 62.016 23.033 62.04 ;
     RECT  22.453 24.672 23.209 36.84 ;
     RECT  22.277 37.872 23.209 39.336 ;
     RECT  22.787 42.624 23.245 43.656 ;
     RECT  23.209 24.672 23.425 39.336 ;
     RECT  23.029 40.368 23.425 41.016 ;
     RECT  23.245 42.576 23.497 43.656 ;
     RECT  23.497 42.528 23.533 43.656 ;
     RECT  23.425 24.672 23.749 41.016 ;
     RECT  22.817 48.384 23.749 55.848 ;
     RECT  22.789 56.88 23.749 58.728 ;
     RECT  22.787 44.688 23.785 45.24 ;
     RECT  22.817 46.32 23.785 47.16 ;
     RECT  22.709 2.496 23.821 18.552 ;
     RECT  23.785 44.688 23.893 47.16 ;
     RECT  23.749 48.384 23.893 58.728 ;
     RECT  23.821 2.256 24.008 18.552 ;
     RECT  23.029 19.584 24.008 23.688 ;
     RECT  23.749 24.672 24.008 41.064 ;
     RECT  23.533 42.24 24.008 43.656 ;
     RECT  23.893 44.688 24.008 58.728 ;
     RECT  24.008 2.148 24.112 62.652 ;
     RECT  24.112 2.256 24.304 62.382 ;
     RECT  24.304 3.312 24.833 25.08 ;
     RECT  24.304 59.76 24.905 60.744 ;
     RECT  24.833 4.752 25.235 25.08 ;
     RECT  24.304 26.352 25.913 58.728 ;
     RECT  25.913 26.352 25.985 26.664 ;
     RECT  25.235 4.752 26.021 22.056 ;
     RECT  24.304 2.256 26.129 2.28 ;
     RECT  24.905 59.856 26.161 60.744 ;
     RECT  25.985 26.352 26.189 26.376 ;
     RECT  24.833 3.312 26.233 3.72 ;
     RECT  25.913 27.696 26.387 58.728 ;
     RECT  26.021 10.464 26.485 22.056 ;
     RECT  26.387 41.616 26.557 58.728 ;
     RECT  26.161 59.856 26.557 61.224 ;
     RECT  26.233 2.88 26.593 3.72 ;
     RECT  26.387 27.696 26.633 39.336 ;
     RECT  26.557 41.616 26.633 61.224 ;
     RECT  26.593 2.88 26.665 3.768 ;
     RECT  26.021 4.752 26.665 9.192 ;
     RECT  26.485 10.464 26.737 22.344 ;
     RECT  25.235 23.328 26.737 25.08 ;
     RECT  26.737 10.464 26.773 25.08 ;
     RECT  26.189 26.208 26.773 26.376 ;
     RECT  26.633 35.232 26.957 39.336 ;
     RECT  26.387 40.368 26.957 40.632 ;
     RECT  26.773 10.464 26.993 26.376 ;
     RECT  26.633 27.696 27.133 33.96 ;
     RECT  26.633 41.616 27.137 60.888 ;
     RECT  26.665 2.88 27.313 9.192 ;
     RECT  26.993 10.464 27.313 25.32 ;
     RECT  27.137 57.12 27.317 60.888 ;
     RECT  27.313 2.88 27.353 25.32 ;
     RECT  26.957 40.608 27.356 40.632 ;
     RECT  27.137 41.616 27.356 56.04 ;
     RECT  27.353 23.328 27.569 25.32 ;
     RECT  27.569 23.328 27.641 25.176 ;
     RECT  26.957 36.24 27.925 37.896 ;
     RECT  26.957 39.072 27.925 39.336 ;
     RECT  26.993 26.352 27.997 26.376 ;
     RECT  27.133 27.456 27.997 33.96 ;
     RECT  27.356 40.608 28.105 56.04 ;
     RECT  27.317 57.12 28.105 59.496 ;
     RECT  27.353 2.88 28.145 22.344 ;
     RECT  28.145 3.024 28.217 22.344 ;
     RECT  27.925 36.24 28.321 39.336 ;
     RECT  28.105 40.608 28.321 59.496 ;
     RECT  26.957 35.232 28.357 35.256 ;
     RECT  28.321 36.24 28.357 59.496 ;
     RECT  27.997 26.352 28.429 33.96 ;
     RECT  28.357 35.232 28.429 59.496 ;
     RECT  28.217 14.64 28.465 22.344 ;
     RECT  27.641 23.328 28.465 23.688 ;
     RECT  27.641 24.768 28.609 25.176 ;
     RECT  28.429 26.352 28.609 59.496 ;
     RECT  28.609 24.768 28.897 59.496 ;
     RECT  27.317 60.816 28.897 60.888 ;
     RECT  27.673 62.16 28.897 62.184 ;
     RECT  28.465 14.64 28.969 23.688 ;
     RECT  28.897 24.768 28.969 62.184 ;
     RECT  28.217 3.024 29.408 13.656 ;
     RECT  28.969 14.64 29.408 62.184 ;
     RECT  29.408 2.148 29.512 62.652 ;
     RECT  29.512 2.256 29.704 62.382 ;
     RECT  29.704 25.776 29.729 61.944 ;
     RECT  29.704 2.256 29.837 24.696 ;
     RECT  29.837 2.256 29.843 22.2 ;
     RECT  29.729 48.144 29.843 61.944 ;
     RECT  29.843 57.648 29.909 61.944 ;
     RECT  29.837 23.232 29.987 24.696 ;
     RECT  29.909 60.864 30.053 61.944 ;
     RECT  29.843 48.144 30.125 56.52 ;
     RECT  29.909 57.648 30.172 59.496 ;
     RECT  30.053 61.68 30.197 61.944 ;
     RECT  29.729 25.776 30.419 47.16 ;
     RECT  30.419 25.776 30.485 43.416 ;
     RECT  30.485 27.6 30.515 43.416 ;
     RECT  30.419 44.688 30.521 45.72 ;
     RECT  30.125 51.456 30.521 56.52 ;
     RECT  29.843 14.208 30.701 22.2 ;
     RECT  30.419 46.848 30.769 47.16 ;
     RECT  30.125 48.144 30.769 50.136 ;
     RECT  30.521 55.728 30.845 56.52 ;
     RECT  30.769 46.848 31.093 50.136 ;
     RECT  30.845 55.968 31.201 56.52 ;
     RECT  30.172 57.648 31.201 59.448 ;
     RECT  30.485 25.776 31.309 26.376 ;
     RECT  30.197 61.728 31.309 61.944 ;
     RECT  31.201 55.968 31.381 59.448 ;
     RECT  31.309 61.248 31.489 61.944 ;
     RECT  31.489 61.248 31.561 62.232 ;
     RECT  31.381 55.968 31.601 59.832 ;
     RECT  30.521 44.688 31.669 45.432 ;
     RECT  31.093 46.848 31.669 50.184 ;
     RECT  29.843 2.976 31.705 13.032 ;
     RECT  30.701 14.208 31.705 22.056 ;
     RECT  30.515 27.6 31.717 41.16 ;
     RECT  30.515 42.192 31.717 43.416 ;
     RECT  31.601 57.648 31.781 59.832 ;
     RECT  31.705 2.832 31.813 22.056 ;
     RECT  29.987 23.28 31.813 24.696 ;
     RECT  31.309 25.68 31.813 26.376 ;
     RECT  31.717 27.6 31.813 43.416 ;
     RECT  31.601 55.968 31.885 56.472 ;
     RECT  31.813 25.68 31.889 43.416 ;
     RECT  31.813 2.832 31.957 24.696 ;
     RECT  31.889 34.944 31.957 43.416 ;
     RECT  31.669 44.688 31.957 50.184 ;
     RECT  31.957 34.944 32.099 50.184 ;
     RECT  31.561 61.152 32.149 62.232 ;
     RECT  32.099 34.944 32.321 41.256 ;
     RECT  32.321 34.944 32.339 41.16 ;
     RECT  32.339 34.944 32.393 35.256 ;
     RECT  31.957 2.544 32.461 24.696 ;
     RECT  31.889 25.68 32.461 33.96 ;
     RECT  30.521 51.456 32.461 54.504 ;
     RECT  31.885 55.536 32.461 56.472 ;
     RECT  32.339 36.384 32.465 41.16 ;
     RECT  32.461 51.456 32.605 56.472 ;
     RECT  31.781 57.648 32.605 59.256 ;
     RECT  32.149 60.768 32.717 62.232 ;
     RECT  32.605 51.456 32.973 59.256 ;
     RECT  32.973 51.216 33.181 59.256 ;
     RECT  32.717 60.768 33.257 61.992 ;
     RECT  32.465 37.008 33.301 41.16 ;
     RECT  32.099 42.384 33.301 50.184 ;
     RECT  33.257 61.392 33.329 61.992 ;
     RECT  32.461 2.544 33.613 33.96 ;
     RECT  32.393 35.088 33.613 35.256 ;
     RECT  33.613 2.544 33.649 35.256 ;
     RECT  33.301 37.008 33.649 50.184 ;
     RECT  33.181 51.216 33.649 59.544 ;
     RECT  33.649 37.008 33.865 59.544 ;
     RECT  33.865 37.008 34.117 59.88 ;
     RECT  33.649 2.544 34.369 35.448 ;
     RECT  34.117 36.816 34.369 59.88 ;
     RECT  34.369 2.544 34.808 59.88 ;
     RECT  33.329 61.392 34.808 61.704 ;
     RECT  34.808 2.148 34.912 62.652 ;
     RECT  34.912 2.418 35.104 62.382 ;
     RECT  35.104 53.952 35.165 56.28 ;
     RECT  35.104 37.152 35.219 52.344 ;
     RECT  35.104 25.296 35.315 36.12 ;
     RECT  35.104 14.448 35.417 23.976 ;
     RECT  35.417 14.736 35.525 23.976 ;
     RECT  35.219 37.152 35.705 40.296 ;
     RECT  35.219 41.424 35.939 47.4 ;
     RECT  35.525 14.736 35.957 23.688 ;
     RECT  35.939 44.688 36.205 47.4 ;
     RECT  35.219 48.384 36.205 52.344 ;
     RECT  35.165 53.952 36.205 55.8 ;
     RECT  35.104 2.736 36.209 13.176 ;
     RECT  35.315 25.296 36.457 35.928 ;
     RECT  36.205 44.688 36.601 52.344 ;
     RECT  36.205 53.952 36.601 56.52 ;
     RECT  35.104 57.648 36.601 62.136 ;
     RECT  35.705 38.4 36.637 40.296 ;
     RECT  35.939 41.424 36.637 43.464 ;
     RECT  36.209 2.736 36.757 3.336 ;
     RECT  36.457 25.296 36.817 36.024 ;
     RECT  36.757 2.592 36.844 3.336 ;
     RECT  36.601 44.688 36.853 52.68 ;
     RECT  36.601 53.712 36.853 62.136 ;
     RECT  36.209 4.464 36.925 13.176 ;
     RECT  35.705 37.152 36.925 37.32 ;
     RECT  36.637 38.4 36.925 43.464 ;
     RECT  35.957 15.264 36.961 23.688 ;
     RECT  36.925 37.152 37.033 43.464 ;
     RECT  36.853 44.688 37.033 62.136 ;
     RECT  37.033 37.152 37.073 62.136 ;
     RECT  37.073 37.152 37.105 53.112 ;
     RECT  37.105 37.056 37.109 53.112 ;
     RECT  36.844 2.736 37.145 3.336 ;
     RECT  37.109 37.056 37.145 45.576 ;
     RECT  36.925 4.464 37.189 13.608 ;
     RECT  36.961 15.072 37.189 23.688 ;
     RECT  37.073 54.096 37.217 62.136 ;
     RECT  36.817 25.056 37.237 36.024 ;
     RECT  37.145 37.056 37.237 39.624 ;
     RECT  37.189 14.784 37.276 23.688 ;
     RECT  37.237 25.056 37.433 39.624 ;
     RECT  37.217 57.312 37.433 62.136 ;
     RECT  37.145 40.992 37.541 45.576 ;
     RECT  37.276 14.88 37.681 23.688 ;
     RECT  37.433 25.056 37.681 39.336 ;
     RECT  37.433 57.552 37.865 62.136 ;
     RECT  37.145 2.832 37.969 3.336 ;
     RECT  37.189 4.464 37.969 13.656 ;
     RECT  37.109 46.848 38.077 53.112 ;
     RECT  37.217 54.096 38.077 55.8 ;
     RECT  37.541 41.184 38.185 45.576 ;
     RECT  38.077 46.848 38.185 55.8 ;
     RECT  38.185 41.184 38.221 55.8 ;
     RECT  37.969 2.832 38.257 13.656 ;
     RECT  37.681 14.88 38.257 39.336 ;
     RECT  37.865 57.552 38.477 61.368 ;
     RECT  38.257 2.832 38.585 39.336 ;
     RECT  38.221 41.184 38.617 56.04 ;
     RECT  38.585 4.416 38.725 39.336 ;
     RECT  38.617 41.184 38.809 56.472 ;
     RECT  38.477 57.552 38.945 60.552 ;
     RECT  38.725 4.416 38.977 39.624 ;
     RECT  38.809 51.168 39.013 56.472 ;
     RECT  38.945 57.552 39.013 60.312 ;
     RECT  38.977 4.416 39.053 39.816 ;
     RECT  39.053 37.68 39.089 39.816 ;
     RECT  38.809 41.184 39.517 49.896 ;
     RECT  39.445 61.392 39.625 61.416 ;
     RECT  39.625 61.392 40.129 61.944 ;
     RECT  38.585 2.832 40.208 3.096 ;
     RECT  39.053 4.416 40.208 36.648 ;
     RECT  39.089 37.92 40.208 39.816 ;
     RECT  39.517 41.136 40.208 49.896 ;
     RECT  39.013 51.168 40.208 60.312 ;
     RECT  40.129 61.392 40.208 61.992 ;
     RECT  40.208 2.148 40.312 62.652 ;
     RECT  40.312 2.418 40.504 62.382 ;
     RECT  40.504 41.136 40.637 62.04 ;
     RECT  40.637 42.48 40.745 62.04 ;
     RECT  40.504 2.496 40.961 3.432 ;
     RECT  40.504 4.512 41.027 39.912 ;
     RECT  41.027 4.512 41.033 36.84 ;
     RECT  40.745 42.48 41.069 59.88 ;
     RECT  41.069 42.48 41.105 58.248 ;
     RECT  41.033 25.872 41.177 36.84 ;
     RECT  41.027 37.824 41.213 39.912 ;
     RECT  40.745 60.96 41.213 62.04 ;
     RECT  41.105 42.48 41.321 58.2 ;
     RECT  41.213 38.16 41.393 39.912 ;
     RECT  41.213 60.96 41.393 61.992 ;
     RECT  41.033 4.512 41.537 24.648 ;
     RECT  41.069 59.472 41.573 59.88 ;
     RECT  41.321 42.48 41.681 58.152 ;
     RECT  41.537 4.656 41.717 24.648 ;
     RECT  41.681 42.48 41.861 55.656 ;
     RECT  41.861 42.48 41.884 55.176 ;
     RECT  40.637 41.136 41.893 41.496 ;
     RECT  41.884 42.48 41.893 49.896 ;
     RECT  41.893 41.136 41.929 49.896 ;
     RECT  41.681 57.264 41.933 58.152 ;
     RECT  41.177 25.872 42.181 33.912 ;
     RECT  41.177 34.896 42.181 36.84 ;
     RECT  41.393 38.16 42.181 38.472 ;
     RECT  41.717 4.704 42.221 24.648 ;
     RECT  41.573 59.472 42.221 59.736 ;
     RECT  41.884 51.12 42.257 55.176 ;
     RECT  41.393 39.6 42.277 39.912 ;
     RECT  42.181 25.68 42.323 38.472 ;
     RECT  40.961 2.496 42.325 3.336 ;
     RECT  42.221 4.704 42.329 13.56 ;
     RECT  42.221 14.592 42.433 24.648 ;
     RECT  42.323 25.68 42.433 36.888 ;
     RECT  42.325 2.496 42.437 3.432 ;
     RECT  42.221 59.712 42.613 59.736 ;
     RECT  41.393 60.96 42.613 61.944 ;
     RECT  42.613 59.712 42.757 61.944 ;
     RECT  42.323 37.92 42.829 38.472 ;
     RECT  42.757 59.712 42.869 62.04 ;
     RECT  42.829 37.92 42.973 38.52 ;
     RECT  42.277 39.6 42.973 40.008 ;
     RECT  41.933 57.264 42.973 58.056 ;
     RECT  42.973 37.92 43.081 40.008 ;
     RECT  41.929 41.04 43.081 49.896 ;
     RECT  42.973 57.024 43.297 58.056 ;
     RECT  42.437 2.832 43.301 3.432 ;
     RECT  43.081 37.92 43.333 49.896 ;
     RECT  42.329 4.896 43.441 13.56 ;
     RECT  43.297 56.112 43.585 58.056 ;
     RECT  43.441 4.656 43.621 13.56 ;
     RECT  42.433 14.592 43.621 36.888 ;
     RECT  43.333 37.92 43.801 50.136 ;
     RECT  43.585 56.112 43.837 58.152 ;
     RECT  42.257 51.12 43.841 54.984 ;
     RECT  43.801 37.872 44.125 50.136 ;
     RECT  43.841 51.12 44.125 53.064 ;
     RECT  43.837 56.112 44.165 58.2 ;
     RECT  44.165 56.976 44.201 58.2 ;
     RECT  43.621 4.656 44.269 36.888 ;
     RECT  44.125 37.872 44.273 53.064 ;
     RECT  44.269 4.464 44.341 36.888 ;
     RECT  44.273 37.872 44.341 50.136 ;
     RECT  43.841 54.144 44.341 54.984 ;
     RECT  44.341 4.464 44.387 50.136 ;
     RECT  44.201 57.552 44.413 58.2 ;
     RECT  44.387 46.608 44.417 50.136 ;
     RECT  44.387 4.464 44.425 45.624 ;
     RECT  44.425 4.464 44.453 45.528 ;
     RECT  42.869 59.808 44.489 62.04 ;
     RECT  43.301 2.88 44.597 3.432 ;
     RECT  44.273 51.216 44.633 53.064 ;
     RECT  44.633 51.6 44.845 53.064 ;
     RECT  44.341 54.144 44.845 55.992 ;
     RECT  44.489 61.056 44.845 62.04 ;
     RECT  44.413 57.552 45.025 58.248 ;
     RECT  44.597 2.88 45.421 3.336 ;
     RECT  44.453 4.992 45.421 45.528 ;
     RECT  45.421 4.464 45.457 45.528 ;
     RECT  44.417 46.8 45.457 50.136 ;
     RECT  45.025 57.552 45.493 58.68 ;
     RECT  45.421 2.832 45.565 3.336 ;
     RECT  45.457 4.464 45.565 50.136 ;
     RECT  45.565 2.832 45.608 50.136 ;
     RECT  44.845 51.6 45.608 55.992 ;
     RECT  45.493 57.552 45.608 58.728 ;
     RECT  44.489 59.808 45.608 59.832 ;
     RECT  44.845 61.056 45.608 62.184 ;
     RECT  45.608 2.148 45.712 62.652 ;
     RECT  45.712 2.418 45.904 62.382 ;
     RECT  45.904 53.904 45.965 62.184 ;
     RECT  45.904 2.832 46.109 52.776 ;
     RECT  46.109 4.464 46.145 52.776 ;
     RECT  46.109 2.832 46.217 3.384 ;
     RECT  46.145 4.464 46.397 4.488 ;
     RECT  46.217 2.88 46.433 3.384 ;
     RECT  46.145 5.52 46.613 52.776 ;
     RECT  45.965 54.096 46.643 62.184 ;
     RECT  46.613 42.72 46.685 52.776 ;
     RECT  46.685 43.104 46.691 52.776 ;
     RECT  46.643 56.448 46.793 62.184 ;
     RECT  46.691 43.104 46.829 50.04 ;
     RECT  46.793 59.712 46.865 62.184 ;
     RECT  46.643 54.096 47.257 55.464 ;
     RECT  46.691 51.696 47.329 52.776 ;
     RECT  47.257 53.952 47.329 55.464 ;
     RECT  46.613 5.52 47.437 29.352 ;
     RECT  46.865 59.76 47.477 62.184 ;
     RECT  47.329 51.696 47.549 55.464 ;
     RECT  47.437 5.28 47.653 29.352 ;
     RECT  47.549 53.952 47.689 55.464 ;
     RECT  46.793 56.448 47.689 58.728 ;
     RECT  46.433 3.024 47.725 3.384 ;
     RECT  47.725 2.928 47.797 3.384 ;
     RECT  47.797 2.544 47.837 3.384 ;
     RECT  46.829 43.296 47.941 50.04 ;
     RECT  47.653 5.232 48.157 29.352 ;
     RECT  46.613 30.336 48.157 41.64 ;
     RECT  47.689 53.952 48.181 58.728 ;
     RECT  47.477 59.76 48.181 61.944 ;
     RECT  47.941 43.296 48.373 50.568 ;
     RECT  48.157 5.232 48.479 41.64 ;
     RECT  48.373 42.624 48.479 50.568 ;
     RECT  48.479 5.232 48.593 50.568 ;
     RECT  48.593 5.232 48.661 23.64 ;
     RECT  48.181 53.952 48.697 61.944 ;
     RECT  48.593 24.672 48.737 50.568 ;
     RECT  48.737 24.672 48.755 31.56 ;
     RECT  48.661 4.944 48.805 23.64 ;
     RECT  47.549 51.696 48.841 52.776 ;
     RECT  48.697 53.952 48.841 62.136 ;
     RECT  47.837 2.544 48.881 3.192 ;
     RECT  48.841 51.696 48.881 62.136 ;
     RECT  48.737 32.976 48.917 50.568 ;
     RECT  48.881 51.696 48.953 60.024 ;
     RECT  48.755 25.44 49.025 31.56 ;
     RECT  49.025 27.888 49.097 31.56 ;
     RECT  48.953 51.696 49.097 58.68 ;
     RECT  48.805 4.8 49.129 23.64 ;
     RECT  49.097 30.048 49.133 31.56 ;
     RECT  48.881 2.832 49.205 3.192 ;
     RECT  48.917 32.976 49.205 45.72 ;
     RECT  49.097 56.4 49.385 58.68 ;
     RECT  49.129 4.656 49.42 23.64 ;
     RECT  49.385 56.4 49.475 57.048 ;
     RECT  49.385 58.08 49.493 58.68 ;
     RECT  49.205 2.928 49.525 3.192 ;
     RECT  49.205 33.552 49.637 45.72 ;
     RECT  49.42 4.656 49.709 18.408 ;
     RECT  49.42 19.536 49.724 23.64 ;
     RECT  49.025 25.44 49.724 26.904 ;
     RECT  49.097 51.696 49.745 55.176 ;
     RECT  49.724 19.536 49.763 26.904 ;
     RECT  49.133 30.096 49.781 31.56 ;
     RECT  49.781 31.392 49.817 31.56 ;
     RECT  49.637 40.944 49.859 45.72 ;
     RECT  49.859 42.72 49.921 45.72 ;
     RECT  49.817 31.536 49.955 31.56 ;
     RECT  48.917 47.088 49.961 50.568 ;
     RECT  49.961 47.328 49.993 50.568 ;
     RECT  49.745 53.952 50.065 55.176 ;
     RECT  49.475 56.4 50.065 56.712 ;
     RECT  49.993 47.328 50.093 50.712 ;
     RECT  49.745 51.696 50.093 52.728 ;
     RECT  48.953 60 50.245 60.024 ;
     RECT  48.881 61.056 50.245 62.136 ;
     RECT  49.921 42.72 50.281 45.768 ;
     RECT  49.525 2.928 50.461 3.288 ;
     RECT  49.709 4.656 50.461 18.168 ;
     RECT  50.245 60 50.54 62.136 ;
     RECT  50.54 59.616 50.569 62.136 ;
     RECT  49.637 33.552 50.677 39.864 ;
     RECT  49.859 40.944 50.677 41.256 ;
     RECT  49.097 27.888 50.785 29.064 ;
     RECT  49.781 30.096 50.785 30.408 ;
     RECT  49.493 58.08 50.785 58.296 ;
     RECT  50.569 59.28 50.785 62.136 ;
     RECT  50.065 53.952 50.828 56.712 ;
     RECT  50.785 58.08 50.828 62.136 ;
     RECT  50.785 27.888 50.849 30.408 ;
     RECT  50.281 42.72 50.893 45.816 ;
     RECT  50.461 2.928 51.001 18.168 ;
     RECT  49.763 19.536 51.001 26.616 ;
     RECT  51.001 2.784 51.008 18.168 ;
     RECT  51.001 19.536 51.008 26.808 ;
     RECT  50.849 27.888 51.008 30.6 ;
     RECT  50.677 33.552 51.008 41.256 ;
     RECT  50.893 42.72 51.008 46.248 ;
     RECT  50.093 47.328 51.008 52.728 ;
     RECT  50.828 53.952 51.008 62.136 ;
     RECT  51.008 2.148 51.112 62.652 ;
     RECT  51.112 2.418 51.304 62.382 ;
     RECT  51.304 2.784 51.365 19.848 ;
     RECT  51.304 20.88 51.401 22.296 ;
     RECT  51.304 23.28 51.401 30.408 ;
     RECT  51.365 2.784 51.443 17.64 ;
     RECT  51.304 54.048 51.509 56.616 ;
     RECT  51.401 25.008 51.581 30.408 ;
     RECT  51.443 2.784 51.689 9.912 ;
     RECT  51.304 47.328 51.779 52.584 ;
     RECT  51.509 54.048 51.827 56.568 ;
     RECT  51.365 18.864 51.833 19.848 ;
     RECT  51.581 29.328 51.833 30.408 ;
     RECT  51.304 57.6 51.833 60.312 ;
     RECT  51.689 2.784 51.869 9.816 ;
     RECT  51.833 59.76 51.869 60.312 ;
     RECT  51.833 57.6 51.877 58.728 ;
     RECT  51.401 21.12 51.905 22.296 ;
     RECT  51.833 18.864 51.941 19.656 ;
     RECT  51.581 25.008 51.941 28.248 ;
     RECT  51.304 33.072 51.977 41.208 ;
     RECT  51.443 10.896 52.019 17.64 ;
     RECT  51.869 3.024 52.115 9.816 ;
     RECT  52.019 10.992 52.229 17.64 ;
     RECT  51.977 34.656 52.229 41.208 ;
     RECT  51.827 54.048 52.252 55.272 ;
     RECT  52.229 34.992 52.265 41.208 ;
     RECT  52.265 38.448 52.297 41.208 ;
     RECT  51.304 42.192 52.297 46.248 ;
     RECT  52.115 3.024 52.301 3.048 ;
     RECT  52.297 38.448 52.405 46.248 ;
     RECT  51.779 47.328 52.405 52.488 ;
     RECT  52.405 38.448 52.409 52.488 ;
     RECT  51.941 25.296 52.445 28.248 ;
     RECT  51.941 19.632 52.481 19.656 ;
     RECT  52.409 38.688 52.481 52.488 ;
     RECT  52.445 25.488 52.621 28.248 ;
     RECT  51.304 32.064 52.621 32.088 ;
     RECT  51.977 33.072 52.621 33.576 ;
     RECT  52.115 4.656 52.625 9.816 ;
     RECT  51.905 21.648 52.657 22.296 ;
     RECT  51.401 23.28 52.657 23.928 ;
     RECT  52.625 5.232 52.805 9.816 ;
     RECT  52.481 38.688 52.805 50.328 ;
     RECT  51.827 56.544 52.873 56.568 ;
     RECT  51.877 57.6 52.873 58.68 ;
     RECT  52.481 51.312 52.877 52.488 ;
     RECT  52.621 25.488 52.909 28.584 ;
     RECT  51.833 29.76 52.909 30.408 ;
     RECT  52.873 56.544 52.913 58.68 ;
     RECT  52.621 32.064 52.981 33.576 ;
     RECT  52.981 32.064 53.017 33.864 ;
     RECT  52.945 19.056 53.053 19.08 ;
     RECT  52.909 25.488 53.197 30.408 ;
     RECT  52.657 21.648 53.201 23.928 ;
     RECT  52.252 54.144 53.267 55.272 ;
     RECT  53.017 31.536 53.269 33.864 ;
     RECT  52.265 34.992 53.269 37.032 ;
     RECT  52.229 11.808 53.309 17.64 ;
     RECT  53.309 14.688 53.341 17.64 ;
     RECT  53.309 11.808 53.377 13.608 ;
     RECT  52.805 5.232 53.417 9.768 ;
     RECT  53.341 14.688 53.417 17.688 ;
     RECT  52.805 41.76 53.417 50.328 ;
     RECT  53.197 25.488 53.449 30.504 ;
     RECT  53.417 14.784 53.453 17.688 ;
     RECT  51.869 59.76 53.489 59.784 ;
     RECT  53.417 5.52 53.525 9.768 ;
     RECT  53.417 41.904 53.555 50.328 ;
     RECT  53.377 11.136 53.557 13.608 ;
     RECT  53.525 5.52 53.561 9 ;
     RECT  53.555 43.632 53.596 50.328 ;
     RECT  53.449 25.248 53.633 30.504 ;
     RECT  53.561 6.096 53.669 9 ;
     RECT  53.453 14.976 53.701 17.688 ;
     RECT  53.053 18.672 53.701 19.08 ;
     RECT  53.267 54.48 53.705 55.272 ;
     RECT  52.913 56.88 53.741 58.68 ;
     RECT  53.701 14.976 53.749 19.08 ;
     RECT  53.557 20.208 53.749 20.376 ;
     RECT  53.557 10.896 53.809 13.608 ;
     RECT  53.749 14.976 53.917 20.376 ;
     RECT  52.805 38.688 53.989 40.392 ;
     RECT  53.809 10.224 54.065 13.608 ;
     RECT  53.917 14.976 54.133 20.52 ;
     RECT  53.201 21.648 54.133 23.448 ;
     RECT  54.133 14.976 54.173 23.448 ;
     RECT  53.741 56.88 54.173 58.488 ;
     RECT  54.173 14.976 54.179 22.2 ;
     RECT  53.596 43.92 54.181 50.328 ;
     RECT  52.877 51.312 54.181 52.44 ;
     RECT  54.173 56.88 54.325 57.864 ;
     RECT  54.065 12 54.353 13.32 ;
     RECT  54.181 43.92 54.353 52.44 ;
     RECT  54.325 56.496 54.371 57.864 ;
     RECT  54.371 57.84 54.412 57.864 ;
     RECT  54.179 14.976 54.421 21.096 ;
     RECT  53.989 38.688 54.425 40.872 ;
     RECT  54.425 40.8 54.457 40.872 ;
     RECT  53.669 6.096 54.529 8.712 ;
     RECT  53.633 25.248 54.572 30.456 ;
     RECT  54.572 24.912 54.659 30.456 ;
     RECT  54.065 10.224 54.706 10.68 ;
     RECT  54.421 14.784 54.781 21.096 ;
     RECT  54.781 14.688 54.785 21.096 ;
     RECT  53.555 41.904 54.817 42.648 ;
     RECT  54.353 43.92 54.817 49.512 ;
     RECT  53.269 31.536 54.857 37.032 ;
     RECT  54.659 25.536 54.893 30.456 ;
     RECT  54.817 41.904 54.901 49.512 ;
     RECT  53.705 55.104 54.917 55.272 ;
     RECT  54.371 56.496 54.917 56.52 ;
     RECT  54.529 5.616 54.929 8.712 ;
     RECT  54.173 23.376 54.929 23.448 ;
     RECT  54.353 50.736 54.949 52.44 ;
     RECT  54.893 25.584 54.997 30.456 ;
     RECT  54.857 31.536 54.997 36.936 ;
     RECT  54.917 55.104 54.997 56.52 ;
     RECT  54.706 10.176 55.1 10.68 ;
     RECT  54.785 14.688 55.109 17.256 ;
     RECT  54.353 12 55.139 12.12 ;
     RECT  55.139 12 55.18 12.024 ;
     RECT  54.997 54.336 55.18 56.52 ;
     RECT  54.785 18.48 55.181 21.096 ;
     RECT  55.18 54.336 55.181 54.36 ;
     RECT  55.1 9.648 55.187 10.68 ;
     RECT  54.353 13.296 55.187 13.32 ;
     RECT  54.457 40.8 55.213 40.92 ;
     RECT  54.901 41.904 55.213 42.648 ;
     RECT  55.181 18.768 55.283 20.088 ;
     RECT  54.425 38.688 55.285 39.768 ;
     RECT  54.901 43.92 55.333 49.512 ;
     RECT  54.949 50.736 55.333 53.304 ;
     RECT  55.18 55.968 55.361 56.52 ;
     RECT  54.929 5.616 55.379 8.52 ;
     RECT  55.333 43.92 55.379 53.304 ;
     RECT  54.997 25.584 55.405 36.936 ;
     RECT  55.379 47.664 55.427 53.304 ;
     RECT  55.285 37.92 55.477 39.768 ;
     RECT  55.213 40.8 55.477 42.648 ;
     RECT  55.109 14.688 55.645 15.576 ;
     RECT  55.405 35.76 55.825 36.936 ;
     RECT  55.477 37.92 55.825 42.648 ;
     RECT  55.825 35.76 56.005 42.648 ;
     RECT  56.005 35.76 56.365 42.744 ;
     RECT  55.379 43.92 56.365 46.536 ;
     RECT  55.379 6.192 56.408 8.52 ;
     RECT  55.187 10.608 56.408 10.68 ;
     RECT  55.645 13.824 56.408 15.576 ;
     RECT  55.109 16.56 56.408 17.256 ;
     RECT  55.283 18.768 56.408 18.792 ;
     RECT  55.283 20.064 56.408 20.088 ;
     RECT  54.179 22.176 56.408 22.2 ;
     RECT  54.929 23.376 56.408 23.4 ;
     RECT  55.405 25.584 56.408 34.488 ;
     RECT  56.365 35.76 56.408 46.536 ;
     RECT  55.427 47.664 56.408 52.584 ;
     RECT  55.361 55.968 56.408 55.992 ;
     RECT  56.408 2.148 56.512 62.652 ;
     RECT  56.512 2.418 56.704 62.382 ;
     RECT  56.704 42.576 56.765 44.952 ;
     RECT  56.704 47.664 56.765 48.264 ;
     RECT  56.704 25.632 56.801 27.384 ;
     RECT  56.704 12.384 56.819 12.408 ;
     RECT  56.801 25.632 56.819 27.144 ;
     RECT  56.765 47.856 56.837 48.264 ;
     RECT  56.819 25.632 56.845 25.656 ;
     RECT  56.704 10.608 56.873 10.68 ;
     RECT  56.704 23.376 56.873 23.4 ;
     RECT  56.837 48.24 56.873 48.264 ;
     RECT  56.765 42.576 56.88 44.328 ;
     RECT  56.88 43.536 56.909 44.328 ;
     RECT  56.704 20.064 56.915 21.672 ;
     RECT  56.873 10.608 56.981 10.632 ;
     RECT  56.704 13.824 56.981 13.896 ;
     RECT  56.704 18.768 56.981 18.792 ;
     RECT  56.704 7.344 57.059 8.568 ;
     RECT  56.981 13.872 57.125 13.896 ;
     RECT  56.915 21.648 57.125 21.672 ;
     RECT  56.704 46.08 57.161 46.104 ;
     RECT  57.059 8.208 57.197 8.568 ;
     RECT  56.704 15.312 57.197 15.336 ;
     RECT  56.704 29.088 57.197 38.184 ;
     RECT  56.704 39.792 57.197 39.816 ;
     RECT  56.909 43.536 57.197 43.56 ;
     RECT  56.704 40.848 57.305 40.872 ;
     RECT  56.819 26.688 57.377 27.144 ;
     RECT  57.377 26.688 57.413 26.712 ;
     RECT  57.197 8.544 57.491 8.568 ;
     RECT  57.197 29.184 57.593 38.184 ;
     RECT  57.593 29.184 58.061 30.216 ;
     RECT  57.593 31.2 58.169 38.184 ;
     RECT  58.169 31.632 58.205 38.184 ;
     RECT  58.061 29.184 58.525 29.736 ;
     RECT  58.205 31.632 58.745 37.656 ;
     RECT  58.525 28.992 59.389 29.736 ;
     RECT  59.389 27.408 59.497 27.432 ;
     RECT  58.093 26.352 59.605 26.376 ;
     RECT  59.497 27.408 59.605 27.912 ;
     RECT  58.745 31.632 59.605 36.936 ;
     RECT  59.389 28.992 59.641 29.88 ;
     RECT  59.605 31.344 59.749 36.936 ;
     RECT  59.641 28.944 59.821 29.88 ;
     RECT  59.605 26.352 60.253 27.912 ;
     RECT  59.821 28.944 60.253 30.072 ;
     RECT  59.749 31.344 60.365 36.984 ;
     RECT  60.365 31.392 60.689 36.984 ;
     RECT  60.253 26.352 60.793 30.072 ;
     RECT  60.793 26.304 60.901 30.072 ;
     RECT  60.901 26.256 61.477 30.072 ;
     RECT  61.477 26.016 61.585 30.072 ;
     RECT  60.689 31.392 61.585 32.616 ;
     RECT  61.585 26.016 61.808 32.616 ;
     RECT  60.689 33.696 61.808 36.984 ;
     RECT  61.808 2.148 61.912 62.652 ;
     RECT  61.912 2.418 62.104 62.382 ;
     RECT  62.104 33.648 63.097 36.024 ;
     RECT  63.097 33.648 63.133 36.168 ;
     RECT  62.104 37.584 63.133 38.472 ;
     RECT  62.104 26.352 63.277 32.616 ;
     RECT  63.277 26.256 63.745 32.616 ;
     RECT  63.133 33.648 63.745 38.472 ;
     RECT  63.745 26.256 64.764 38.472 ;
    LAYER M5 ;
     RECT  2.4 2.137 2.52 2.151 ;
     RECT  7.8 2.137 7.92 2.151 ;
     RECT  13.2 2.137 13.32 2.151 ;
     RECT  18.6 2.137 18.72 2.151 ;
     RECT  24 2.137 24.12 2.151 ;
     RECT  29.4 2.137 29.52 2.151 ;
     RECT  34.8 2.137 34.92 2.151 ;
     RECT  40.2 2.137 40.32 2.151 ;
     RECT  45.6 2.137 45.72 2.151 ;
     RECT  51 2.137 51.12 2.151 ;
     RECT  56.4 2.137 56.52 2.151 ;
     RECT  61.8 2.137 61.92 2.151 ;
     RECT  29.4 2.151 29.712 2.245 ;
     RECT  18.6 2.151 18.912 2.629 ;
     RECT  34.8 2.151 35.112 2.821 ;
     RECT  33.6 2.533 33.624 3.061 ;
     RECT  34.8 2.821 35.352 3.061 ;
     RECT  11.04 2.629 11.064 3.107 ;
     RECT  36.768 2.581 36.792 3.203 ;
     RECT  29.4 2.245 29.832 3.253 ;
     RECT  20.688 3.061 20.712 3.301 ;
     RECT  7.8 2.151 8.112 3.397 ;
     RECT  33.6 3.061 35.352 3.587 ;
     RECT  29.4 3.253 30.312 3.877 ;
     RECT  51 2.151 51.312 3.925 ;
     RECT  7.248 3.397 8.112 4.451 ;
     RECT  20.688 3.301 21.672 4.547 ;
     RECT  38.112 3.397 38.136 4.645 ;
     RECT  29.28 3.877 30.312 4.691 ;
     RECT  51 3.925 52.104 4.741 ;
     RECT  17.616 2.629 18.912 4.931 ;
     RECT  13.2 2.151 13.512 5.077 ;
     RECT  14.592 3.685 14.616 5.077 ;
     RECT  18.48 4.931 18.912 5.171 ;
     RECT  21.6 4.547 21.672 5.413 ;
     RECT  15.648 3.349 15.672 5.747 ;
     RECT  47.76 3.349 47.784 5.845 ;
     RECT  47.76 5.845 47.88 5.891 ;
     RECT  42.528 3.301 42.552 5.987 ;
     RECT  13.2 5.077 14.664 6.133 ;
     RECT  45.6 2.151 45.912 6.133 ;
     RECT  38.112 4.645 38.232 6.181 ;
     RECT  54.672 5.605 55.368 6.227 ;
     RECT  25.44 4.789 25.464 6.371 ;
     RECT  34.8 3.587 35.352 6.371 ;
     RECT  50.736 4.741 52.104 6.563 ;
     RECT  10.128 5.893 10.152 6.611 ;
     RECT  40.2 2.151 40.512 6.613 ;
     RECT  37.056 4.693 37.08 6.659 ;
     RECT  38.112 6.181 38.808 6.659 ;
     RECT  45.6 6.133 46.008 6.757 ;
     RECT  40.2 6.613 41.064 6.805 ;
     RECT  40.2 6.805 41.544 6.851 ;
     RECT  21.6 5.413 21.912 6.995 ;
     RECT  47.856 5.891 47.88 7.045 ;
     RECT  50.736 6.563 52.008 7.235 ;
     RECT  21.888 6.995 21.912 7.333 ;
     RECT  56.4 2.151 56.712 7.333 ;
     RECT  7.296 4.451 8.112 7.381 ;
     RECT  11.424 3.685 11.448 7.381 ;
     RECT  55.152 6.227 55.368 7.381 ;
     RECT  21.888 7.333 22.344 7.475 ;
     RECT  36.768 6.709 37.032 7.475 ;
     RECT  20.256 6.613 20.28 7.619 ;
     RECT  47.136 7.045 47.88 7.619 ;
     RECT  11.424 7.381 11.496 7.621 ;
     RECT  51 7.235 52.008 7.667 ;
     RECT  37.008 7.475 37.032 7.715 ;
     RECT  13.2 6.133 14.808 7.765 ;
     RECT  18.6 5.171 18.912 7.909 ;
     RECT  43.632 7.189 43.656 7.909 ;
     RECT  41.52 6.851 41.544 7.957 ;
     RECT  45.6 6.757 46.152 7.957 ;
     RECT  38.784 6.659 38.808 8.003 ;
     RECT  45.504 7.957 46.152 8.003 ;
     RECT  47.856 7.619 47.88 8.003 ;
     RECT  41.52 7.957 41.592 8.005 ;
     RECT  42.96 7.909 43.656 8.005 ;
     RECT  41.52 8.005 43.656 8.051 ;
     RECT  33.6 3.587 33.624 8.245 ;
     RECT  34.8 6.371 35.112 8.245 ;
     RECT  33.072 8.245 33.624 8.291 ;
     RECT  10.56 7.621 11.496 8.483 ;
     RECT  40.2 6.851 40.512 8.485 ;
     RECT  41.52 8.051 42.264 8.485 ;
     RECT  54.72 7.381 55.368 8.531 ;
     RECT  56.4 7.333 57.048 8.533 ;
     RECT  40.2 8.485 42.264 8.963 ;
     RECT  4.608 8.485 4.632 8.965 ;
     RECT  7.296 7.381 8.232 9.011 ;
     RECT  4.608 8.965 5.256 9.203 ;
     RECT  18.48 7.909 18.912 9.299 ;
     RECT  45.504 8.003 45.912 9.299 ;
     RECT  33.072 8.291 33.096 9.395 ;
     RECT  40.2 8.963 41.592 9.493 ;
     RECT  39.36 9.493 41.592 9.589 ;
     RECT  51 7.667 51.312 9.637 ;
     RECT  13.2 7.765 14.856 9.779 ;
     RECT  5.232 9.203 5.256 9.781 ;
     RECT  6.24 9.349 6.264 9.781 ;
     RECT  38.736 9.589 41.592 10.067 ;
     RECT  7.8 9.011 8.232 10.069 ;
     RECT  22.32 7.475 22.344 10.165 ;
     RECT  55.152 8.531 55.368 10.165 ;
     RECT  53.568 6.709 53.592 10.213 ;
     RECT  55.104 10.165 55.368 10.213 ;
     RECT  45.6 9.299 45.912 10.309 ;
     RECT  18.6 9.299 18.912 10.357 ;
     RECT  50.688 9.637 51.312 10.357 ;
     RECT  37.056 10.261 37.08 10.403 ;
     RECT  5.232 9.781 6.264 10.597 ;
     RECT  11.376 8.483 11.496 10.597 ;
     RECT  34.8 8.245 35.784 10.741 ;
     RECT  7.68 10.069 8.232 10.835 ;
     RECT  43.632 8.051 43.656 10.837 ;
     RECT  22.128 10.165 22.344 10.883 ;
     RECT  34.176 10.741 35.784 10.883 ;
     RECT  43.344 10.837 43.656 10.883 ;
     RECT  50.688 10.357 51.432 10.885 ;
     RECT  50.688 10.885 52.008 11.029 ;
     RECT  29.4 4.691 30.312 11.123 ;
     RECT  10.896 10.597 11.496 11.219 ;
     RECT  50.112 11.029 52.008 11.221 ;
     RECT  9.696 10.309 9.72 11.365 ;
     RECT  10.896 11.219 10.92 11.365 ;
     RECT  18.6 10.357 19.032 11.365 ;
     RECT  24 2.151 24.312 11.365 ;
     RECT  13.2 9.779 14.136 11.411 ;
     RECT  7.68 10.835 8.112 11.459 ;
     RECT  38.736 10.067 40.512 11.459 ;
     RECT  48.672 10.165 48.696 11.459 ;
     RECT  31.344 10.213 31.368 11.651 ;
     RECT  45.504 10.309 45.912 11.653 ;
     RECT  17.664 11.365 19.032 11.699 ;
     RECT  34.176 10.883 35.112 11.699 ;
     RECT  15.408 10.981 15.432 11.747 ;
     RECT  29.4 11.123 30.168 11.891 ;
     RECT  7.8 11.459 8.112 11.941 ;
     RECT  38.736 11.459 38.76 12.035 ;
     RECT  34.8 11.699 35.112 12.037 ;
     RECT  34.8 12.037 35.208 12.179 ;
     RECT  9.696 11.365 10.92 12.227 ;
     RECT  53.568 10.213 55.368 12.229 ;
     RECT  24 11.365 24.552 12.469 ;
     RECT  16.512 11.749 16.536 12.517 ;
     RECT  17.664 11.699 18.912 12.517 ;
     RECT  50.064 11.221 52.008 12.517 ;
     RECT  23.52 12.469 24.552 12.611 ;
     RECT  53.28 12.229 55.368 12.611 ;
     RECT  45.408 11.653 45.912 12.709 ;
     RECT  41.568 10.067 41.592 12.803 ;
     RECT  45.408 12.709 46.776 12.899 ;
     RECT  13.2 11.411 13.848 12.995 ;
     RECT  37.584 11.845 37.608 13.091 ;
     RECT  16.512 12.517 18.912 13.139 ;
     RECT  49.584 12.517 52.008 13.139 ;
     RECT  50.064 13.139 52.008 13.283 ;
     RECT  20.784 12.517 20.808 13.285 ;
     RECT  20.688 13.285 20.808 13.331 ;
     RECT  22.32 10.883 22.344 13.427 ;
     RECT  10.896 12.227 10.92 13.573 ;
     RECT  36.48 12.853 36.504 13.621 ;
     RECT  40.2 11.459 40.512 13.621 ;
     RECT  44.4 11.365 44.424 13.669 ;
     RECT  45.408 12.899 45.912 13.669 ;
     RECT  9.696 12.227 9.72 14.003 ;
     RECT  7.8 11.941 8.616 14.099 ;
     RECT  16.704 13.139 18.912 14.099 ;
     RECT  23.52 12.611 24.312 14.147 ;
     RECT  10.848 13.573 10.92 14.291 ;
     RECT  5.04 10.597 6.264 14.387 ;
     RECT  16.704 14.099 16.728 14.485 ;
     RECT  43.344 10.883 43.368 14.581 ;
     RECT  44.4 13.669 45.912 14.581 ;
     RECT  20.688 13.331 20.712 14.773 ;
     RECT  17.904 14.099 18.912 14.819 ;
     RECT  50.064 13.283 51.312 14.819 ;
     RECT  20.16 14.773 20.712 14.821 ;
     RECT  20.16 14.821 21.432 14.869 ;
     RECT  50.112 14.819 51.312 14.915 ;
     RECT  39.888 13.621 40.968 14.963 ;
     RECT  5.184 14.387 6.264 15.251 ;
     RECT  29.4 11.891 30.12 15.253 ;
     RECT  5.472 15.251 6.264 15.301 ;
     RECT  7.8 14.099 8.112 15.301 ;
     RECT  20.16 14.869 21.576 15.395 ;
     RECT  5.472 15.301 8.112 15.443 ;
     RECT  15.792 14.485 16.728 15.443 ;
     RECT  39.888 14.963 40.512 15.443 ;
     RECT  43.344 14.581 45.912 15.443 ;
     RECT  34.8 12.179 35.112 15.493 ;
     RECT  36.48 13.621 37.224 15.539 ;
     RECT  20.16 15.395 21.432 15.587 ;
     RECT  24 14.147 24.312 15.589 ;
     RECT  53.568 12.611 55.368 15.589 ;
     RECT  29.184 15.253 30.12 15.637 ;
     RECT  43.344 15.443 44.424 15.637 ;
     RECT  32.928 12.181 32.952 15.683 ;
     RECT  29.184 15.637 30.744 15.685 ;
     RECT  13.2 12.995 13.512 15.733 ;
     RECT  50.88 14.915 51.312 15.923 ;
     RECT  10.896 14.291 10.92 15.971 ;
     RECT  48.432 14.005 48.456 16.019 ;
     RECT  29.184 15.685 30.84 16.067 ;
     RECT  31.92 14.149 31.944 16.451 ;
     RECT  37.2 15.539 37.224 16.595 ;
     RECT  43.104 15.637 44.424 16.595 ;
     RECT  24 15.589 24.408 16.835 ;
     RECT  51 15.923 51.312 16.885 ;
     RECT  20.16 15.587 20.712 17.075 ;
     RECT  16.704 15.443 16.728 17.077 ;
     RECT  53.376 15.589 55.368 17.077 ;
     RECT  56.4 8.533 57.48 17.077 ;
     RECT  33.072 16.645 33.096 17.123 ;
     RECT  45.6 15.443 45.912 17.173 ;
     RECT  16.704 17.077 17.16 17.219 ;
     RECT  50.736 16.885 51.312 17.219 ;
     RECT  53.376 17.077 57.48 17.267 ;
     RECT  6.24 15.443 8.112 17.605 ;
     RECT  14.688 15.349 14.712 17.651 ;
     RECT  53.376 17.267 55.368 17.699 ;
     RECT  16.704 17.219 16.824 17.893 ;
     RECT  24 16.835 24.312 17.893 ;
     RECT  12 17.509 12.024 18.037 ;
     RECT  13.056 15.733 13.512 18.037 ;
     RECT  20.688 17.075 20.712 18.085 ;
     RECT  45.6 17.173 46.344 18.179 ;
     RECT  29.4 16.067 30.84 18.181 ;
     RECT  34.8 15.493 35.208 18.181 ;
     RECT  15.936 17.893 16.824 18.565 ;
     RECT  44.016 16.595 44.424 18.565 ;
     RECT  43.968 18.565 44.424 18.707 ;
     RECT  20.688 18.085 20.952 18.757 ;
     RECT  40.2 15.443 40.512 18.757 ;
     RECT  44.016 18.707 44.424 18.803 ;
     RECT  34.8 18.181 36.024 18.851 ;
     RECT  6.24 17.605 8.376 18.995 ;
     RECT  12 18.037 13.512 19.235 ;
     RECT  29.4 18.181 31.368 19.285 ;
     RECT  29.4 19.285 31.848 19.331 ;
     RECT  31.824 19.331 31.848 19.429 ;
     RECT  15.936 18.565 17.448 19.571 ;
     RECT  34.8 18.851 35.592 19.571 ;
     RECT  40.2 18.757 40.92 19.571 ;
     RECT  33.312 18.709 33.336 19.621 ;
     RECT  6.24 18.995 8.112 19.667 ;
     RECT  40.2 19.571 40.872 19.811 ;
     RECT  38.016 19.093 38.04 19.909 ;
     RECT  39.12 19.189 39.144 19.909 ;
     RECT  33.312 19.621 33.72 20.003 ;
     RECT  20.64 18.757 20.952 20.051 ;
     RECT  44.304 18.803 44.424 20.053 ;
     RECT  45.6 18.179 46.008 20.053 ;
     RECT  49.344 18.565 49.368 20.099 ;
     RECT  44.304 20.053 46.008 20.101 ;
     RECT  38.016 19.909 39.144 20.531 ;
     RECT  29.4 19.331 30.6 20.533 ;
     RECT  31.824 19.429 31.944 20.533 ;
     RECT  26.16 18.709 26.184 20.579 ;
     RECT  29.4 20.533 31.944 20.675 ;
     RECT  29.4 20.675 30.6 20.725 ;
     RECT  33.696 20.003 33.72 20.819 ;
     RECT  24 17.893 24.552 20.965 ;
     RECT  44.304 20.101 46.632 21.059 ;
     RECT  48.72 20.485 48.744 21.061 ;
     RECT  7.8 19.667 8.112 21.109 ;
     RECT  38.688 20.531 39.144 21.347 ;
     RECT  20.64 20.051 20.856 21.395 ;
     RECT  16.8 19.571 17.448 21.637 ;
     RECT  18.6 14.819 18.912 21.637 ;
     RECT  12.24 19.235 13.512 21.683 ;
     RECT  16.8 21.637 18.912 21.925 ;
     RECT  16.656 21.925 18.912 21.971 ;
     RECT  6.24 19.667 6.6 22.165 ;
     RECT  28.512 20.725 30.6 22.211 ;
     RECT  48.72 21.061 49.464 22.211 ;
     RECT  37.584 21.301 37.608 22.259 ;
     RECT  28.512 22.211 29.976 22.307 ;
     RECT  44.304 21.059 46.392 22.307 ;
     RECT  33.648 21.061 33.672 22.403 ;
     RECT  34.8 19.571 35.112 22.453 ;
     RECT  40.2 19.811 40.512 22.453 ;
     RECT  7.8 21.109 8.232 22.499 ;
     RECT  39.12 21.347 39.144 22.499 ;
     RECT  31.824 20.675 31.944 22.501 ;
     RECT  10.848 21.637 10.872 22.643 ;
     RECT  40.2 22.453 41.016 22.741 ;
     RECT  48.72 22.211 48.744 22.741 ;
     RECT  51 17.219 51.312 22.741 ;
     RECT  24 20.965 25.224 22.787 ;
     RECT  27.264 20.005 27.288 22.835 ;
     RECT  16.656 21.971 16.824 23.027 ;
     RECT  29.4 22.307 29.976 23.267 ;
     RECT  5.952 22.165 6.6 23.269 ;
     RECT  20.832 21.395 20.856 23.269 ;
     RECT  47.904 22.741 48.744 23.459 ;
     RECT  44.304 22.307 45.912 23.555 ;
     RECT  50.88 22.741 51.312 23.555 ;
     RECT  2.4 2.151 2.712 23.701 ;
     RECT  4.032 23.365 4.056 23.701 ;
     RECT  31.824 22.501 32.376 23.939 ;
     RECT  34.224 22.453 35.112 23.941 ;
     RECT  12.864 21.683 13.512 23.987 ;
     RECT  16.8 23.027 16.824 23.987 ;
     RECT  44.304 23.555 44.328 23.987 ;
     RECT  2.4 23.701 4.056 24.131 ;
     RECT  5.712 23.269 6.6 24.179 ;
     RECT  10.848 23.941 10.872 24.275 ;
     RECT  39.936 22.741 41.016 24.515 ;
     RECT  7.8 22.499 8.112 24.517 ;
     RECT  6.24 24.179 6.6 24.563 ;
     RECT  29.4 23.267 29.832 24.563 ;
     RECT  40.2 24.515 41.016 24.659 ;
     RECT  29.4 24.563 29.712 24.661 ;
     RECT  22.8 24.661 22.824 24.803 ;
     RECT  29.28 24.661 29.712 24.803 ;
     RECT  7.8 24.517 8.232 24.995 ;
     RECT  45.36 23.555 45.912 25.045 ;
     RECT  51 23.555 51.312 25.045 ;
     RECT  17.808 21.971 18.912 25.139 ;
     RECT  24 22.787 24.312 25.285 ;
     RECT  34.224 23.941 35.352 25.427 ;
     RECT  15.36 21.781 15.384 25.525 ;
     RECT  40.2 24.659 40.728 25.573 ;
     RECT  10.464 25.045 10.488 25.621 ;
     RECT  45.264 25.045 45.912 25.621 ;
     RECT  47.712 25.045 47.736 25.621 ;
     RECT  20.832 23.269 21.672 25.667 ;
     RECT  13.2 23.987 13.512 25.717 ;
     RECT  20.832 25.667 20.856 25.717 ;
     RECT  53.568 17.699 55.368 26.053 ;
     RECT  29.4 24.803 29.712 26.101 ;
     RECT  26.208 23.557 26.232 26.243 ;
     RECT  36.576 25.573 36.6 26.243 ;
     RECT  45.264 25.621 47.736 26.243 ;
     RECT  45.264 26.243 47.064 26.245 ;
     RECT  37.68 25.045 37.704 26.291 ;
     RECT  51 25.045 51.864 26.291 ;
     RECT  4.464 24.757 4.632 26.531 ;
     RECT  13.008 25.717 13.512 26.627 ;
     RECT  34.224 25.427 35.112 26.725 ;
     RECT  39.456 25.573 40.728 26.725 ;
     RECT  10.464 25.621 10.632 26.819 ;
     RECT  15.36 25.525 15.672 26.821 ;
     RECT  49.776 24.469 49.8 26.869 ;
     RECT  44.4 26.245 47.064 27.011 ;
     RECT  28.944 26.101 29.712 27.157 ;
     RECT  28.944 27.157 30.264 27.203 ;
     RECT  6.48 24.563 6.6 27.301 ;
     RECT  7.8 24.995 8.112 27.301 ;
     RECT  39.312 26.725 40.728 27.301 ;
     RECT  44.4 27.011 44.424 27.301 ;
     RECT  48.72 23.459 48.744 27.301 ;
     RECT  49.728 26.869 49.8 27.301 ;
     RECT  15.36 26.821 15.72 27.637 ;
     RECT  39.312 27.301 40.92 27.685 ;
     RECT  42.384 26.965 42.408 27.733 ;
     RECT  53.232 26.053 55.368 27.733 ;
     RECT  10.464 26.819 10.488 27.829 ;
     RECT  52.992 27.733 55.368 27.875 ;
     RECT  48.72 27.301 49.8 27.877 ;
     RECT  20.544 25.717 20.856 27.923 ;
     RECT  39.312 27.685 41.208 27.923 ;
     RECT  42.336 27.733 42.408 27.923 ;
     RECT  15.072 27.637 15.72 27.971 ;
     RECT  53.232 27.875 55.368 27.971 ;
     RECT  23.904 25.285 24.312 28.211 ;
     RECT  42.336 27.923 42.36 28.309 ;
     RECT  53.28 27.971 55.368 28.355 ;
     RECT  31.824 23.939 31.848 28.453 ;
     RECT  39.36 27.923 41.208 28.453 ;
     RECT  42.192 28.309 42.36 28.453 ;
     RECT  43.776 27.301 44.424 28.453 ;
     RECT  54.528 28.355 55.368 28.453 ;
     RECT  56.4 17.267 57.48 28.453 ;
     RECT  29.4 27.203 30.264 28.499 ;
     RECT  15.072 27.971 15.672 28.501 ;
     RECT  48.72 27.877 49.992 28.501 ;
     RECT  53.28 28.355 53.304 28.547 ;
     RECT  45.6 27.011 47.064 28.549 ;
     RECT  48.336 28.501 49.992 28.549 ;
     RECT  45.6 28.549 49.992 28.595 ;
     RECT  10.272 27.829 10.488 28.597 ;
     RECT  10.272 28.597 10.776 28.643 ;
     RECT  43.632 28.453 44.424 28.837 ;
     RECT  39.36 28.453 42.36 28.979 ;
     RECT  47.376 28.595 49.992 29.029 ;
     RECT  51 26.291 51.312 29.029 ;
     RECT  6.48 27.301 8.112 29.123 ;
     RECT  10.464 28.643 10.776 29.123 ;
     RECT  22.32 26.101 22.344 29.171 ;
     RECT  27.984 28.165 28.008 29.461 ;
     RECT  0.144 25.189 0.168 29.555 ;
     RECT  34.224 26.725 35.448 29.699 ;
     RECT  47.376 29.029 51.312 29.699 ;
     RECT  54.528 28.453 57.48 29.699 ;
     RECT  14.784 28.501 15.672 29.747 ;
     RECT  34.8 29.699 35.448 29.747 ;
     RECT  39.36 28.979 42.312 29.795 ;
     RECT  13.2 26.627 13.512 29.797 ;
     RECT  25.776 27.877 25.8 29.989 ;
     RECT  10.464 29.123 10.488 30.035 ;
     RECT  25.776 29.989 26.232 30.035 ;
     RECT  54.528 29.699 55.368 30.275 ;
     RECT  2.4 24.131 3.336 30.323 ;
     RECT  7.68 29.123 8.112 30.371 ;
     RECT  31.728 28.453 31.848 30.467 ;
     RECT  27.888 29.461 28.008 30.517 ;
     RECT  29.4 28.499 29.712 30.517 ;
     RECT  27.888 30.517 29.712 30.563 ;
     RECT  20.832 27.923 20.856 30.611 ;
     RECT  27.984 30.563 29.712 30.611 ;
     RECT  49.056 29.699 51.312 30.611 ;
     RECT  37.056 29.941 37.08 30.613 ;
     RECT  13.2 29.797 13.608 30.757 ;
     RECT  37.008 30.613 37.08 30.803 ;
     RECT  7.8 30.371 8.112 30.805 ;
     RECT  0.288 30.757 0.312 30.853 ;
     RECT  0.144 30.853 0.312 30.899 ;
     RECT  43.344 28.837 44.424 30.899 ;
     RECT  26.208 30.035 26.232 31.187 ;
     RECT  47.376 29.699 47.928 31.379 ;
     RECT  24 28.211 24.312 31.381 ;
     RECT  39.36 29.795 41.208 31.477 ;
     RECT  42.192 29.795 42.312 31.477 ;
     RECT  39.36 31.477 42.312 31.523 ;
     RECT  49.056 30.611 49.944 31.571 ;
     RECT  0.144 30.899 0.168 31.619 ;
     RECT  39.36 31.523 40.512 31.667 ;
     RECT  22.512 30.181 22.536 31.955 ;
     RECT  13.2 30.757 14.136 32.003 ;
     RECT  47.856 31.379 47.928 32.005 ;
     RECT  49.056 31.571 49.8 32.005 ;
     RECT  43.344 30.899 43.368 32.053 ;
     RECT  44.4 30.899 44.424 32.053 ;
     RECT  41.568 31.523 42.312 32.099 ;
     RECT  28.416 30.611 29.712 32.149 ;
     RECT  7.8 30.805 9.096 32.195 ;
     RECT  28.176 32.149 29.712 32.195 ;
     RECT  43.344 32.053 44.424 32.243 ;
     RECT  24 31.381 24.408 32.341 ;
     RECT  42.192 32.099 42.312 32.341 ;
     RECT  31.824 30.467 31.848 32.437 ;
     RECT  34.8 29.747 35.112 32.437 ;
     RECT  37.008 30.803 37.032 32.437 ;
     RECT  20.88 32.389 21.24 32.579 ;
     RECT  43.584 32.243 44.424 32.581 ;
     RECT  45.6 28.595 45.912 32.581 ;
     RECT  37.008 32.437 37.656 32.963 ;
     RECT  17.136 32.485 17.16 33.059 ;
     RECT  42.192 32.341 42.36 33.059 ;
     RECT  6.48 29.123 6.504 33.061 ;
     RECT  7.8 32.195 8.856 33.061 ;
     RECT  21.168 32.579 21.24 33.061 ;
     RECT  6.48 33.061 8.856 33.203 ;
     RECT  21.168 33.061 22.056 33.253 ;
     RECT  24 32.341 24.984 33.299 ;
     RECT  28.176 32.195 28.2 33.349 ;
     RECT  29.4 32.195 29.712 33.349 ;
     RECT  31.824 32.437 32.424 33.541 ;
     RECT  15.648 29.747 15.672 33.589 ;
     RECT  28.176 33.349 29.712 33.731 ;
     RECT  47.856 32.005 49.8 33.779 ;
     RECT  15.36 33.589 15.672 33.827 ;
     RECT  13.2 32.003 13.608 33.925 ;
     RECT  21.168 33.253 22.104 33.971 ;
     RECT  42.192 33.059 42.312 34.069 ;
     RECT  43.584 32.581 45.912 34.069 ;
     RECT  38.736 32.053 38.76 34.163 ;
     RECT  28.752 33.731 29.712 34.165 ;
     RECT  34.128 32.437 35.112 34.165 ;
     RECT  51 30.611 51.312 34.165 ;
     RECT  7.8 33.203 8.856 34.211 ;
     RECT  37.632 32.963 37.656 34.211 ;
     RECT  13.2 33.925 14.232 34.213 ;
     RECT  15.36 33.827 15.432 34.213 ;
     RECT  53.808 34.069 53.832 34.309 ;
     RECT  55.344 30.275 55.368 34.309 ;
     RECT  12.144 32.197 12.168 34.355 ;
     RECT  6.48 33.203 6.504 34.453 ;
     RECT  7.8 34.211 8.112 34.453 ;
     RECT  21.216 33.971 22.104 34.499 ;
     RECT  42.192 34.069 45.912 34.501 ;
     RECT  21.744 34.499 22.104 34.691 ;
     RECT  10.32 34.165 10.344 34.741 ;
     RECT  18.6 25.139 18.912 34.741 ;
     RECT  47.856 33.779 47.88 34.741 ;
     RECT  49.2 33.779 49.8 34.741 ;
     RECT  53.808 34.309 55.368 34.787 ;
     RECT  34.128 34.165 35.304 34.835 ;
     RECT  42.192 34.501 46.44 34.981 ;
     RECT  51 34.165 51.816 35.173 ;
     RECT  28.752 34.165 29.832 35.269 ;
     RECT  34.608 34.835 35.304 35.269 ;
     RECT  42.192 34.981 46.536 35.269 ;
     RECT  55.344 34.787 55.368 35.363 ;
     RECT  56.4 29.699 57.48 35.363 ;
     RECT  6.48 34.453 8.112 35.413 ;
     RECT  47.856 34.741 49.8 35.461 ;
     RECT  50.88 35.173 51.816 35.461 ;
     RECT  10.32 34.741 10.44 35.651 ;
     RECT  24 33.299 24.312 35.701 ;
     RECT  18.48 34.741 18.912 35.747 ;
     RECT  47.856 35.461 51.816 35.797 ;
     RECT  31.248 33.541 32.424 35.891 ;
     RECT  13.2 34.213 15.432 35.939 ;
     RECT  42.144 35.269 46.536 36.227 ;
     RECT  43.584 36.227 46.536 36.229 ;
     RECT  47.808 35.797 51.816 36.229 ;
     RECT  28.56 35.269 29.832 36.373 ;
     RECT  6.48 35.413 9.096 36.421 ;
     RECT  24 35.701 24.408 36.421 ;
     RECT  26.208 35.317 26.232 36.421 ;
     RECT  37.296 35.269 37.32 36.421 ;
     RECT  21.744 34.691 21.768 36.515 ;
     RECT  24 36.421 26.232 36.515 ;
     RECT  42.144 36.227 42.456 36.515 ;
     RECT  56.4 35.363 57.192 36.515 ;
     RECT  15.408 35.939 15.432 36.517 ;
     RECT  5.76 36.421 9.096 36.659 ;
     RECT  43.584 36.229 51.816 36.755 ;
     RECT  31.824 35.891 32.424 36.997 ;
     RECT  13.2 35.939 14.232 37.045 ;
     RECT  37.248 36.421 37.32 37.381 ;
     RECT  43.584 36.755 49.8 37.427 ;
     RECT  51 36.755 51.816 37.427 ;
     RECT  24 36.515 25.32 37.429 ;
     RECT  42.192 36.515 42.456 37.475 ;
     RECT  34.608 35.269 36.024 37.573 ;
     RECT  40.2 31.667 40.512 37.573 ;
     RECT  23.712 37.429 25.32 37.619 ;
     RECT  31.68 36.997 32.424 37.619 ;
     RECT  48.528 37.427 49.8 37.619 ;
     RECT  49.536 37.619 49.8 37.667 ;
     RECT  37.104 37.381 37.32 37.763 ;
     RECT  23.712 37.619 24.408 37.907 ;
     RECT  21.36 37.861 21.384 38.149 ;
     RECT  28.56 36.373 30.312 38.149 ;
     RECT  0.144 37.141 0.168 38.195 ;
     RECT  18.6 35.747 18.912 38.197 ;
     RECT  33.648 37.573 36.024 38.243 ;
     RECT  37.296 37.763 37.32 38.435 ;
     RECT  10.32 35.651 10.344 38.533 ;
     RECT  12.528 37.045 14.232 38.675 ;
     RECT  53.808 34.787 53.832 38.677 ;
     RECT  18.24 38.197 18.912 38.725 ;
     RECT  28.56 38.149 30.84 38.771 ;
     RECT  23.712 37.907 24.312 38.819 ;
     RECT  21.36 38.149 21.672 39.013 ;
     RECT  26.736 38.917 26.76 39.013 ;
     RECT  26.352 39.013 26.76 39.059 ;
     RECT  15.408 36.517 15.48 39.253 ;
     RECT  43.584 37.427 47.256 39.253 ;
     RECT  48.528 37.619 48.552 39.253 ;
     RECT  28.56 38.771 29.976 39.301 ;
     RECT  43.584 39.253 48.552 39.301 ;
     RECT  49.536 37.667 49.56 39.301 ;
     RECT  17.856 38.725 18.912 39.347 ;
     RECT  15.36 39.253 15.48 39.541 ;
     RECT  54.864 39.349 54.888 39.541 ;
     RECT  56.4 36.515 56.712 39.541 ;
     RECT  2.4 30.323 2.712 39.733 ;
     RECT  13.2 38.675 14.232 39.733 ;
     RECT  15.36 39.541 15.864 39.733 ;
     RECT  5.76 36.659 8.112 39.829 ;
     RECT  40.2 37.573 41.016 39.877 ;
     RECT  42.288 37.475 42.456 39.877 ;
     RECT  53.376 38.677 53.832 39.877 ;
     RECT  54.864 39.541 56.712 39.877 ;
     RECT  10.32 38.533 10.824 39.923 ;
     RECT  18.24 39.347 18.912 39.923 ;
     RECT  43.584 39.301 49.56 39.923 ;
     RECT  20.928 39.013 21.672 39.971 ;
     RECT  40.2 39.877 42.456 40.019 ;
     RECT  13.2 39.733 15.864 40.163 ;
     RECT  43.584 39.923 49.368 40.259 ;
     RECT  34.608 38.243 36.024 40.307 ;
     RECT  53.376 39.877 56.712 40.307 ;
     RECT  4.608 26.531 4.632 40.357 ;
     RECT  5.76 39.829 9.096 40.357 ;
     RECT  42.432 40.019 42.456 40.357 ;
     RECT  43.584 40.259 46.872 40.357 ;
     RECT  4.608 40.357 9.096 40.403 ;
     RECT  42.432 40.357 46.872 40.403 ;
     RECT  24 38.819 24.312 40.405 ;
     RECT  31.824 37.619 32.424 40.405 ;
     RECT  34.608 40.307 35.208 40.405 ;
     RECT  14.88 40.163 15.864 40.595 ;
     RECT  28.464 39.301 29.976 40.693 ;
     RECT  51 37.427 51.624 40.789 ;
     RECT  34.224 40.405 35.208 40.883 ;
     RECT  40.2 40.019 41.4 41.029 ;
     RECT  42.432 40.403 44.472 41.029 ;
     RECT  20.928 39.971 21.384 41.075 ;
     RECT  4.608 40.403 8.472 41.171 ;
     RECT  48.192 40.259 49.368 41.171 ;
     RECT  48.384 41.171 49.368 41.221 ;
     RECT  40.2 41.029 44.472 41.507 ;
     RECT  34.224 40.883 35.112 41.509 ;
     RECT  15.408 40.595 15.864 41.605 ;
     RECT  45.6 40.403 46.872 41.605 ;
     RECT  4.608 41.171 8.232 41.651 ;
     RECT  10.32 39.923 10.584 41.651 ;
     RECT  14.832 41.605 15.864 41.651 ;
     RECT  24 40.405 25.128 41.651 ;
     RECT  26.352 39.059 26.376 41.651 ;
     RECT  48.384 41.221 49.848 41.651 ;
     RECT  27.408 40.933 27.432 41.699 ;
     RECT  14.832 41.651 15.432 41.747 ;
     RECT  28.464 40.693 30.504 41.747 ;
     RECT  33.936 41.509 35.112 41.893 ;
     RECT  54.288 40.307 56.712 41.939 ;
     RECT  31.728 40.405 32.424 41.989 ;
     RECT  33.936 41.893 35.208 41.989 ;
     RECT  17.328 41.557 17.352 42.133 ;
     RECT  18.48 39.923 18.912 42.133 ;
     RECT  37.488 40.981 37.512 42.179 ;
     RECT  2.4 39.733 3.432 42.227 ;
     RECT  28.512 41.747 30.504 42.227 ;
     RECT  31.728 41.989 35.208 42.227 ;
     RECT  56.4 41.939 56.712 42.565 ;
     RECT  48.528 41.651 49.848 42.611 ;
     RECT  6.864 41.651 8.232 42.709 ;
     RECT  48.96 42.611 49.848 42.709 ;
     RECT  51 40.789 51.864 42.709 ;
     RECT  10.56 41.651 10.584 42.757 ;
     RECT  15.408 41.747 15.432 42.757 ;
     RECT  10.56 42.757 11.448 42.803 ;
     RECT  17.328 42.133 18.912 42.803 ;
     RECT  41.904 41.507 44.472 42.803 ;
     RECT  38.784 41.749 38.808 42.995 ;
     RECT  41.904 42.803 44.376 42.995 ;
     RECT  52.896 41.749 52.92 43.237 ;
     RECT  54.288 41.939 55.272 43.237 ;
     RECT  48.96 42.709 51.864 43.283 ;
     RECT  45.6 41.605 47.4 43.333 ;
     RECT  11.424 42.803 11.448 43.379 ;
     RECT  31.824 42.227 35.208 43.523 ;
     RECT  40.2 41.507 40.512 43.525 ;
     RECT  6.864 42.709 8.52 43.571 ;
     RECT  48.96 43.283 48.984 43.813 ;
     RECT  31.824 43.523 33.336 43.859 ;
     RECT  48.912 43.813 48.984 43.955 ;
     RECT  42.432 42.995 44.376 44.003 ;
     RECT  52.896 43.237 55.272 44.051 ;
     RECT  34.8 43.523 35.208 44.101 ;
     RECT  36.528 43.333 36.552 44.101 ;
     RECT  50.064 43.283 51.312 44.195 ;
     RECT  24 41.651 24.312 44.197 ;
     RECT  28.512 42.227 30.168 44.197 ;
     RECT  45.408 43.333 47.4 44.245 ;
     RECT  48.912 43.955 48.936 44.245 ;
     RECT  56.4 42.565 56.808 44.339 ;
     RECT  4.8 41.651 5.784 44.341 ;
     RECT  50.88 44.195 51.312 44.389 ;
     RECT  15.072 42.757 15.432 44.435 ;
     RECT  53.28 44.051 55.272 44.437 ;
     RECT  7.008 43.571 8.52 44.579 ;
     RECT  39.312 43.525 40.512 44.579 ;
     RECT  4.368 44.341 5.784 44.723 ;
     RECT  13.2 40.163 13.512 44.965 ;
     RECT  24 44.197 25.176 44.965 ;
     RECT  43.392 44.003 44.376 44.965 ;
     RECT  45.408 44.245 48.936 45.011 ;
     RECT  21.36 41.075 21.384 45.059 ;
     RECT  45.408 45.011 48.024 45.059 ;
     RECT  24 44.965 25.656 45.107 ;
     RECT  34.8 44.101 36.552 45.157 ;
     RECT  50.88 44.389 51.864 45.253 ;
     RECT  34.8 45.157 37.032 45.299 ;
     RECT  50.208 45.253 51.864 45.299 ;
     RECT  11.712 44.389 11.736 45.301 ;
     RECT  11.424 45.301 11.736 45.347 ;
     RECT  28.512 44.197 30.408 45.397 ;
     RECT  53.28 44.437 55.368 45.781 ;
     RECT  39.36 44.579 40.512 45.877 ;
     RECT  24 45.107 25.464 45.923 ;
     RECT  15.408 44.435 15.432 45.971 ;
     RECT  5.76 44.723 5.784 46.069 ;
     RECT  31.824 43.859 32.424 46.165 ;
     RECT  25.44 45.923 25.464 46.211 ;
     RECT  27.888 45.397 30.408 46.211 ;
     RECT  43.008 44.965 44.376 46.211 ;
     RECT  4.368 44.723 4.392 46.213 ;
     RECT  5.76 46.069 5.928 46.213 ;
     RECT  28.128 46.211 30.408 46.259 ;
     RECT  20.112 45.397 20.136 46.309 ;
     RECT  4.368 46.213 5.928 46.595 ;
     RECT  11.424 45.347 11.448 46.787 ;
     RECT  22.752 40.981 22.776 46.787 ;
     RECT  28.128 46.259 29.712 46.787 ;
     RECT  31.824 46.165 33.048 46.787 ;
     RECT  34.8 45.299 36.456 46.787 ;
     RECT  52.464 45.781 55.368 46.787 ;
     RECT  20.016 46.309 20.136 46.883 ;
     RECT  31.824 46.787 32.424 46.883 ;
     RECT  4.368 46.595 5.784 46.931 ;
     RECT  39.312 45.877 40.512 47.123 ;
     RECT  9.552 46.645 9.576 47.125 ;
     RECT  17.328 42.803 17.352 47.269 ;
     RECT  17.136 47.269 17.352 47.315 ;
     RECT  45.408 45.059 47.928 47.411 ;
     RECT  34.8 46.787 36.168 47.651 ;
     RECT  45.408 47.411 47.832 47.651 ;
     RECT  50.208 45.299 51.312 47.701 ;
     RECT  37.248 47.269 37.272 47.747 ;
     RECT  54.192 46.787 55.368 47.749 ;
     RECT  56.4 44.339 56.712 47.749 ;
     RECT  7.008 44.579 8.112 47.797 ;
     RECT  9.552 47.125 9.864 47.797 ;
     RECT  49.296 47.701 51.312 47.797 ;
     RECT  32.4 46.883 32.424 47.845 ;
     RECT  43.344 46.211 44.376 47.845 ;
     RECT  45.408 47.651 46.44 47.845 ;
     RECT  36.144 47.651 36.168 47.893 ;
     RECT  29.088 46.787 29.712 47.939 ;
     RECT  49.008 47.797 51.312 47.939 ;
     RECT  54.192 47.749 56.712 47.939 ;
     RECT  13.2 44.965 13.704 48.085 ;
     RECT  20.016 46.883 20.04 48.131 ;
     RECT  4.368 46.931 4.392 48.179 ;
     RECT  29.4 47.939 29.712 48.229 ;
     RECT  53.136 46.787 53.208 48.229 ;
     RECT  52.416 48.229 53.208 48.613 ;
     RECT  54.192 47.939 54.216 48.613 ;
     RECT  25.92 47.845 25.944 48.659 ;
     RECT  36.144 47.893 36.888 48.659 ;
     RECT  55.2 47.939 56.712 48.659 ;
     RECT  24 45.923 24.408 48.707 ;
     RECT  43.344 47.845 46.44 48.709 ;
     RECT  47.472 47.651 47.832 48.709 ;
     RECT  49.296 47.939 51.312 48.803 ;
     RECT  32.4 47.845 32.76 48.853 ;
     RECT  49.296 48.803 49.464 48.899 ;
     RECT  43.344 48.709 47.832 48.949 ;
     RECT  17.136 47.315 17.16 48.997 ;
     RECT  18.6 42.803 18.912 48.997 ;
     RECT  36.864 48.659 36.888 48.997 ;
     RECT  27.648 47.845 27.672 49.043 ;
     RECT  52.416 48.613 54.216 49.043 ;
     RECT  7.008 47.797 9.864 49.091 ;
     RECT  36.864 48.997 37.08 49.139 ;
     RECT  38.352 48.229 38.376 49.139 ;
     RECT  36.864 49.139 36.984 49.187 ;
     RECT  5.76 46.931 5.784 49.189 ;
     RECT  7.008 49.091 8.904 49.189 ;
     RECT  13.2 48.085 13.848 49.477 ;
     RECT  43.344 48.949 47.88 49.571 ;
     RECT  5.76 49.189 8.904 49.619 ;
     RECT  44.688 49.571 47.88 49.763 ;
     RECT  29.4 48.229 29.832 49.765 ;
     RECT  12.24 49.477 13.848 49.811 ;
     RECT  20.496 48.421 20.52 50.195 ;
     RECT  53.136 49.043 54.216 50.245 ;
     RECT  10.992 47.317 11.016 50.291 ;
     RECT  49.44 48.899 49.464 50.485 ;
     RECT  51 48.803 51.312 50.485 ;
     RECT  5.76 49.619 8.856 50.629 ;
     RECT  5.088 50.629 8.856 50.677 ;
     RECT  26.16 49.861 26.184 50.677 ;
     RECT  4.752 50.677 8.856 50.771 ;
     RECT  26.16 50.677 27.144 50.819 ;
     RECT  44.688 49.763 47.64 50.819 ;
     RECT  43.344 49.571 43.464 51.109 ;
     RECT  43.344 51.109 43.56 51.155 ;
     RECT  29.088 49.765 29.832 51.205 ;
     RECT  32.4 48.853 33.048 51.251 ;
     RECT  17.136 48.997 18.912 51.299 ;
     RECT  49.44 50.485 51.312 51.347 ;
     RECT  52.416 50.245 54.216 51.347 ;
     RECT  50.736 51.347 51.312 51.349 ;
     RECT  52.416 51.347 53.304 51.349 ;
     RECT  9.648 51.205 9.672 51.539 ;
     RECT  18.192 51.299 18.912 51.541 ;
     RECT  24 48.707 24.312 51.637 ;
     RECT  55.344 48.659 56.712 51.637 ;
     RECT  43.392 51.155 43.56 51.733 ;
     RECT  44.688 50.819 46.632 51.733 ;
     RECT  50.736 51.349 53.304 51.923 ;
     RECT  26.16 50.819 27.048 52.021 ;
     RECT  22.224 51.253 22.248 52.211 ;
     RECT  25.92 52.021 27.048 52.211 ;
     RECT  54.912 51.637 56.712 52.403 ;
     RECT  32.4 51.251 32.424 52.405 ;
     RECT  33.552 52.261 33.576 52.405 ;
     RECT  14.832 51.205 14.856 52.499 ;
     RECT  12.24 49.811 13.512 52.595 ;
     RECT  54.96 52.403 56.712 52.595 ;
     RECT  4.752 50.771 8.112 52.691 ;
     RECT  43.392 51.733 46.632 52.693 ;
     RECT  47.616 50.819 47.64 52.693 ;
     RECT  50.736 51.923 52.2 52.739 ;
     RECT  13.2 52.595 13.512 53.029 ;
     RECT  18.192 51.541 19.704 53.075 ;
     RECT  25.92 52.211 25.944 53.123 ;
     RECT  28.992 51.205 29.832 53.219 ;
     RECT  18.24 53.075 19.704 53.267 ;
     RECT  40.2 47.123 40.512 53.269 ;
     RECT  54.96 52.595 55.416 53.315 ;
     RECT  5.04 52.691 8.112 53.363 ;
     RECT  38.736 50.677 38.76 53.363 ;
     RECT  36.864 49.187 36.888 53.507 ;
     RECT  41.808 50.725 41.832 53.507 ;
     RECT  13.2 53.029 13.608 53.555 ;
     RECT  23.664 51.637 24.312 53.557 ;
     RECT  23.664 53.557 24.936 53.603 ;
     RECT  43.392 52.693 47.64 53.603 ;
     RECT  34.8 47.651 35.112 53.941 ;
     RECT  51 52.739 52.2 54.083 ;
     RECT  17.136 51.299 17.16 54.179 ;
     RECT  24 53.603 24.936 54.179 ;
     RECT  43.536 53.603 47.64 54.179 ;
     RECT  53.232 51.923 53.256 54.179 ;
     RECT  18.24 53.267 18.912 54.323 ;
     RECT  43.536 54.179 43.896 54.371 ;
     RECT  21.168 53.557 21.192 54.611 ;
     RECT  32.4 52.405 33.576 54.611 ;
     RECT  13.2 53.555 13.512 54.661 ;
     RECT  39.888 53.269 40.512 54.755 ;
     RECT  27.024 52.211 27.048 55.141 ;
     RECT  27.024 55.141 27.72 55.187 ;
     RECT  29.4 53.219 29.832 55.237 ;
     RECT  6.096 53.363 8.112 55.331 ;
     RECT  34.8 53.941 35.208 55.715 ;
     RECT  5.04 53.363 5.064 55.813 ;
     RECT  44.976 54.179 47.064 55.813 ;
     RECT  51 54.083 51.816 55.813 ;
     RECT  6.528 55.331 8.112 55.907 ;
     RECT  44.976 55.813 47.88 55.907 ;
     RECT  27.696 55.187 27.72 55.909 ;
     RECT  28.848 55.237 29.832 55.909 ;
     RECT  22.368 55.237 22.392 55.955 ;
     RECT  27.696 55.909 29.832 55.955 ;
     RECT  54.96 53.315 55.128 55.955 ;
     RECT  50.88 55.813 51.816 56.051 ;
     RECT  13.104 54.661 13.512 56.149 ;
     RECT  36.48 55.813 36.504 56.341 ;
     RECT  13.104 56.149 13.608 56.483 ;
     RECT  54.96 55.955 55.032 56.485 ;
     RECT  7.68 55.907 8.112 56.531 ;
     RECT  36.48 56.341 36.744 56.531 ;
     RECT  54.336 56.485 55.032 56.531 ;
     RECT  47.04 55.907 47.88 56.533 ;
     RECT  33.552 54.611 33.576 56.773 ;
     RECT  34.8 55.715 35.112 56.773 ;
     RECT  22.8 56.869 22.824 57.059 ;
     RECT  33.552 56.773 35.112 57.059 ;
     RECT  49.44 51.347 49.464 57.059 ;
     RECT  4.464 55.813 5.064 57.299 ;
     RECT  50.88 56.051 51.312 57.299 ;
     RECT  44.976 55.907 45.912 57.349 ;
     RECT  47.04 56.533 48.264 57.349 ;
     RECT  7.8 56.531 8.112 57.541 ;
     RECT  9.552 56.581 9.576 57.587 ;
     RECT  27.696 55.955 28.248 57.635 ;
     RECT  52.992 56.965 53.016 57.635 ;
     RECT  44.976 57.349 48.264 57.875 ;
     RECT  54.336 56.531 54.36 57.875 ;
     RECT  44.976 57.875 47.064 58.019 ;
     RECT  51 57.299 51.312 58.117 ;
     RECT  6.528 55.907 6.552 58.163 ;
     RECT  29.4 55.955 29.832 58.645 ;
     RECT  36.72 56.531 36.744 58.691 ;
     RECT  44.976 58.019 47.016 58.691 ;
     RECT  48.24 57.875 48.264 58.739 ;
     RECT  51 58.117 51.864 58.739 ;
     RECT  27.696 57.635 27.72 59.221 ;
     RECT  32.4 54.611 32.424 59.221 ;
     RECT  39.12 56.965 39.144 59.267 ;
     RECT  17.184 58.501 17.208 59.315 ;
     RECT  26.88 59.221 27.72 59.315 ;
     RECT  26.88 59.315 26.904 59.507 ;
     RECT  29.4 58.645 30.12 59.507 ;
     RECT  51 58.739 51.312 59.605 ;
     RECT  5.04 57.299 5.064 59.747 ;
     RECT  46.992 58.691 47.016 59.797 ;
     RECT  48.192 59.029 48.216 59.797 ;
     RECT  46.992 59.797 48.216 59.843 ;
     RECT  7.8 57.541 8.28 59.845 ;
     RECT  47.28 59.843 48.216 60.035 ;
     RECT  18.336 54.323 18.912 60.277 ;
     RECT  7.152 59.845 8.328 60.371 ;
     RECT  48.192 60.035 48.216 60.419 ;
     RECT  7.8 60.371 8.328 60.563 ;
     RECT  18.24 60.277 18.912 60.563 ;
     RECT  13.2 56.483 13.512 60.661 ;
     RECT  14.832 59.749 14.856 60.661 ;
     RECT  43.872 54.371 43.896 60.661 ;
     RECT  13.2 60.661 14.856 60.707 ;
     RECT  42.72 59.797 42.744 60.707 ;
     RECT  25.824 57.541 25.848 60.755 ;
     RECT  50.592 59.605 51.312 60.805 ;
     RECT  21.12 58.021 21.144 60.851 ;
     RECT  13.2 60.707 14.424 60.949 ;
     RECT  32.16 59.221 32.424 61.379 ;
     RECT  12.432 60.949 14.424 61.619 ;
     RECT  43.776 60.661 43.896 61.619 ;
     RECT  29.4 59.507 29.712 61.621 ;
     RECT  43.872 61.619 43.896 61.667 ;
     RECT  41.616 60.949 41.64 61.811 ;
     RECT  44.976 58.691 45.912 61.955 ;
     RECT  17.136 59.749 17.16 62.051 ;
     RECT  36.432 60.661 36.456 62.147 ;
     RECT  50.256 60.805 51.312 62.147 ;
     RECT  13.2 61.619 14.424 62.195 ;
     RECT  29.088 61.621 29.712 62.195 ;
     RECT  2.4 42.227 2.712 62.649 ;
     RECT  7.8 60.563 8.112 62.649 ;
     RECT  13.2 62.195 13.512 62.649 ;
     RECT  18.6 60.563 18.912 62.649 ;
     RECT  24 54.179 24.312 62.649 ;
     RECT  29.4 62.195 29.712 62.649 ;
     RECT  34.8 57.059 35.112 62.649 ;
     RECT  40.2 54.755 40.512 62.649 ;
     RECT  45.6 61.955 45.912 62.649 ;
     RECT  51 62.147 51.312 62.649 ;
     RECT  56.4 52.595 56.712 62.649 ;
     RECT  61.8 2.151 62.112 62.649 ;
     RECT  2.4 62.649 2.52 62.663 ;
     RECT  7.8 62.649 7.92 62.663 ;
     RECT  13.2 62.649 13.32 62.663 ;
     RECT  18.6 62.649 18.72 62.663 ;
     RECT  24 62.649 24.12 62.663 ;
     RECT  29.4 62.649 29.52 62.663 ;
     RECT  34.8 62.649 34.92 62.663 ;
     RECT  40.2 62.649 40.32 62.663 ;
     RECT  45.6 62.649 45.72 62.663 ;
     RECT  51 62.649 51.12 62.663 ;
     RECT  56.4 62.649 56.52 62.663 ;
     RECT  61.8 62.649 61.92 62.663 ;
     RECT  33.624 2.533 34.8 3.061 ;
     RECT  35.352 2.821 36.768 3.203 ;
     RECT  33.624 3.587 34.8 8.291 ;
     RECT  13.512 3.685 14.592 5.077 ;
     RECT  14.616 3.685 15.648 5.077 ;
     RECT  37.08 4.693 38.112 6.659 ;
     RECT  24.312 4.789 25.44 6.371 ;
     RECT  14.664 5.077 15.648 5.747 ;
     RECT  55.368 5.605 56.4 17.077 ;
     RECT  14.664 5.747 14.808 6.133 ;
     RECT  47.76 5.891 47.856 7.045 ;
     RECT  10.152 5.893 11.424 6.611 ;
     RECT  38.808 6.181 40.2 8.003 ;
     RECT  54.672 6.227 55.152 6.709 ;
     RECT  10.56 6.611 11.424 7.621 ;
     RECT  18.912 6.613 20.256 7.619 ;
     RECT  20.28 6.613 21.6 6.995 ;
     RECT  53.592 6.709 55.152 7.381 ;
     RECT  40.512 6.851 41.52 8.485 ;
     RECT  46.152 7.045 47.136 7.619 ;
     RECT  53.592 7.381 54.72 8.531 ;
     RECT  41.544 7.909 42.96 7.957 ;
     RECT  41.592 7.957 42.96 8.005 ;
     RECT  39.36 8.003 40.2 9.493 ;
     RECT  42.264 8.051 43.632 8.963 ;
     RECT  7.296 9.011 7.8 9.349 ;
     RECT  5.04 9.203 5.232 10.597 ;
     RECT  45.504 9.299 45.6 10.309 ;
     RECT  5.256 9.349 6.24 9.781 ;
     RECT  6.264 9.349 7.8 10.069 ;
     RECT  14.136 9.779 14.856 10.981 ;
     RECT  40.512 10.067 41.568 12.803 ;
     RECT  6.264 10.069 7.68 11.459 ;
     RECT  53.592 10.165 55.104 10.213 ;
     RECT  30.312 10.213 31.344 11.123 ;
     RECT  35.784 10.261 37.056 10.403 ;
     RECT  8.232 10.309 9.696 10.835 ;
     RECT  9.72 10.597 10.896 11.365 ;
     RECT  8.112 10.835 9.696 11.941 ;
     RECT  35.112 10.883 35.208 12.037 ;
     RECT  43.368 10.883 43.656 11.365 ;
     RECT  14.136 10.981 15.408 11.411 ;
     RECT  48.696 11.029 50.112 11.221 ;
     RECT  30.168 11.123 31.344 11.651 ;
     RECT  48.696 11.221 50.064 11.459 ;
     RECT  43.368 11.365 44.4 14.581 ;
     RECT  44.424 11.365 45.504 11.653 ;
     RECT  38.76 11.459 40.2 12.035 ;
     RECT  49.584 11.459 50.064 12.517 ;
     RECT  44.424 11.653 45.408 13.669 ;
     RECT  16.536 11.749 17.664 12.517 ;
     RECT  37.608 11.845 38.736 12.035 ;
     RECT  8.616 11.941 9.696 14.003 ;
     RECT  35.112 12.179 35.208 12.853 ;
     RECT  9.72 12.227 10.896 13.573 ;
     RECT  52.008 12.229 53.28 12.611 ;
     RECT  22.344 12.469 23.52 13.427 ;
     RECT  20.808 12.517 22.32 13.331 ;
     RECT  40.512 12.803 40.968 13.621 ;
     RECT  35.112 12.853 36.48 15.493 ;
     RECT  36.504 12.853 37.584 13.091 ;
     RECT  36.504 13.091 37.224 13.621 ;
     RECT  16.512 13.139 16.704 14.485 ;
     RECT  20.712 13.331 22.32 13.427 ;
     RECT  20.712 13.427 21.576 14.821 ;
     RECT  9.72 13.573 10.848 14.003 ;
     RECT  16.728 14.099 17.904 14.819 ;
     RECT  31.944 14.149 32.928 15.683 ;
     RECT  18.912 14.773 20.16 17.075 ;
     RECT  21.432 14.821 21.576 14.869 ;
     RECT  13.512 15.349 14.688 17.651 ;
     RECT  14.712 15.349 15.792 15.443 ;
     RECT  44.424 15.443 45.6 20.053 ;
     RECT  35.208 15.493 36.48 15.539 ;
     RECT  30.744 15.637 31.92 15.685 ;
     RECT  30.84 15.685 31.92 16.451 ;
     RECT  50.88 15.923 51 16.885 ;
     RECT  24.312 16.835 24.408 17.893 ;
     RECT  17.16 17.077 18.6 17.219 ;
     RECT  16.824 17.219 18.6 18.565 ;
     RECT  55.368 17.267 56.4 28.453 ;
     RECT  12.024 17.509 13.056 18.037 ;
     RECT  17.448 18.565 18.6 21.637 ;
     RECT  33.336 18.709 34.8 19.621 ;
     RECT  38.04 19.189 39.12 19.909 ;
     RECT  39.144 19.189 40.2 22.499 ;
     RECT  31.848 19.285 33.312 19.429 ;
     RECT  30.6 19.331 31.824 20.533 ;
     RECT  31.944 19.429 33.312 20.003 ;
     RECT  33.72 19.621 34.8 20.819 ;
     RECT  6.6 19.667 7.8 27.301 ;
     RECT  33.648 20.003 33.696 20.819 ;
     RECT  26.184 20.005 27.264 20.579 ;
     RECT  49.344 20.099 49.368 20.485 ;
     RECT  48.744 20.485 49.368 21.061 ;
     RECT  38.016 20.531 38.688 21.301 ;
     RECT  30.6 20.675 31.824 22.211 ;
     RECT  27.288 20.725 28.512 22.307 ;
     RECT  33.648 20.819 34.8 21.061 ;
     RECT  33.672 21.061 34.8 22.403 ;
     RECT  37.608 21.301 38.688 21.347 ;
     RECT  37.608 21.347 39.12 22.259 ;
     RECT  10.872 21.637 12.24 21.683 ;
     RECT  15.384 21.781 16.8 21.925 ;
     RECT  15.384 21.925 16.656 23.027 ;
     RECT  16.824 21.971 17.808 23.987 ;
     RECT  34.224 22.403 34.8 22.453 ;
     RECT  39.936 22.499 40.2 22.741 ;
     RECT  10.848 22.643 10.872 23.941 ;
     RECT  15.384 23.027 16.8 23.987 ;
     RECT  2.712 23.365 4.032 23.701 ;
     RECT  44.328 23.555 45.36 23.987 ;
     RECT  50.88 23.555 51 24.469 ;
     RECT  45.264 23.987 45.36 25.045 ;
     RECT  3.336 24.131 4.056 24.757 ;
     RECT  48.744 24.469 49.776 26.869 ;
     RECT  49.8 24.469 51 27.877 ;
     RECT  39.936 24.515 40.2 25.573 ;
     RECT  21.672 24.661 22.8 24.803 ;
     RECT  22.824 24.661 24 24.803 ;
     RECT  3.336 24.757 4.464 26.531 ;
     RECT  21.672 24.803 22.344 25.667 ;
     RECT  23.904 24.803 24 25.285 ;
     RECT  29.28 24.803 29.4 26.101 ;
     RECT  47.736 25.045 48.72 26.243 ;
     RECT  35.112 25.427 35.352 25.573 ;
     RECT  35.112 25.573 36.576 26.243 ;
     RECT  36.6 25.573 37.68 26.243 ;
     RECT  20.856 25.667 22.344 26.101 ;
     RECT  51.864 26.053 53.232 26.291 ;
     RECT  20.856 26.101 22.32 29.171 ;
     RECT  35.112 26.243 35.448 26.725 ;
     RECT  52.992 26.291 53.232 27.733 ;
     RECT  3.336 26.531 4.608 30.323 ;
     RECT  48.744 26.869 49.728 27.301 ;
     RECT  44.424 27.011 45.6 32.581 ;
     RECT  28.944 27.203 29.4 28.165 ;
     RECT  40.92 27.301 42.384 27.685 ;
     RECT  42.408 27.301 43.776 27.923 ;
     RECT  41.208 27.685 42.384 27.733 ;
     RECT  41.208 27.733 42.336 28.309 ;
     RECT  24.312 27.877 25.776 30.035 ;
     RECT  49.992 27.877 51 29.029 ;
     RECT  42.36 27.923 43.776 28.453 ;
     RECT  28.008 28.165 29.4 30.517 ;
     RECT  41.208 28.309 42.192 28.453 ;
     RECT  53.304 28.355 54.528 28.547 ;
     RECT  30.264 28.453 31.728 28.499 ;
     RECT  42.36 28.453 43.632 28.837 ;
     RECT  13.512 28.501 14.784 29.747 ;
     RECT  47.064 28.501 48.336 28.549 ;
     RECT  45.912 28.595 47.376 31.379 ;
     RECT  42.36 28.837 43.344 28.979 ;
     RECT  42.312 28.979 43.344 32.243 ;
     RECT  6.504 29.123 7.68 30.371 ;
     RECT  0.144 29.555 0.168 30.757 ;
     RECT  47.928 29.699 49.056 32.005 ;
     RECT  55.368 29.699 56.4 35.363 ;
     RECT  13.512 29.747 15.648 29.797 ;
     RECT  41.208 29.795 42.192 31.477 ;
     RECT  13.608 29.797 15.648 30.757 ;
     RECT  24.312 30.035 24.408 31.381 ;
     RECT  22.536 30.181 24 31.955 ;
     RECT  6.504 30.371 7.8 33.061 ;
     RECT  49.944 30.611 51 31.571 ;
     RECT  0.144 30.757 0.288 30.853 ;
     RECT  14.136 30.757 15.648 32.003 ;
     RECT  43.368 30.899 44.4 32.053 ;
     RECT  40.512 31.523 41.568 32.099 ;
     RECT  49.8 31.571 51 35.173 ;
     RECT  39.36 31.667 40.2 32.053 ;
     RECT  38.76 32.053 40.2 34.163 ;
     RECT  28.2 32.195 29.4 33.349 ;
     RECT  12.168 32.197 13.2 34.355 ;
     RECT  42.312 32.243 43.584 32.341 ;
     RECT  42.36 32.341 43.584 33.059 ;
     RECT  37.656 32.437 38.736 34.163 ;
     RECT  15.672 32.485 17.136 33.059 ;
     RECT  17.16 32.485 18.6 33.059 ;
     RECT  42.312 33.059 43.584 34.069 ;
     RECT  6.504 33.203 7.8 34.453 ;
     RECT  47.88 33.779 49.2 34.741 ;
     RECT  14.232 33.925 15.36 34.213 ;
     RECT  53.832 34.069 55.344 34.309 ;
     RECT  8.856 34.165 10.32 34.211 ;
     RECT  29.832 34.165 31.248 35.891 ;
     RECT  8.112 34.211 10.32 35.413 ;
     RECT  46.44 34.501 47.856 34.981 ;
     RECT  53.832 34.787 55.344 35.363 ;
     RECT  46.536 34.981 47.856 35.797 ;
     RECT  49.8 35.173 50.88 35.461 ;
     RECT  36.024 35.269 37.296 36.421 ;
     RECT  9.096 35.413 10.32 36.659 ;
     RECT  46.536 35.797 47.808 36.229 ;
     RECT  29.832 35.891 31.824 36.373 ;
     RECT  14.232 35.939 15.408 39.253 ;
     RECT  42.456 36.227 43.584 40.357 ;
     RECT  30.312 36.373 31.824 36.997 ;
     RECT  4.632 36.421 5.76 40.357 ;
     RECT  36.024 36.421 37.248 37.381 ;
     RECT  42.144 36.515 42.192 37.475 ;
     RECT  49.8 36.755 51 37.667 ;
     RECT  30.312 36.997 31.68 37.619 ;
     RECT  36.024 37.381 37.104 37.763 ;
     RECT  47.256 37.427 48.528 39.253 ;
     RECT  42.144 37.475 42.288 37.573 ;
     RECT  32.424 37.573 33.648 38.243 ;
     RECT  41.016 37.573 42.288 39.877 ;
     RECT  30.312 37.619 31.824 38.149 ;
     RECT  48.552 37.619 49.536 39.301 ;
     RECT  49.56 37.667 51 39.923 ;
     RECT  36.024 37.763 37.296 38.435 ;
     RECT  30.84 38.149 31.824 38.771 ;
     RECT  14.232 39.253 15.36 39.733 ;
     RECT  53.832 39.349 54.864 39.877 ;
     RECT  54.888 39.349 56.4 39.541 ;
     RECT  3.432 39.733 4.608 41.651 ;
     RECT  9.096 39.829 10.32 40.403 ;
     RECT  49.368 39.923 51 41.221 ;
     RECT  21.384 39.971 21.672 40.981 ;
     RECT  41.4 40.019 42.432 41.029 ;
     RECT  13.512 40.163 14.88 40.595 ;
     RECT  46.872 40.259 48.192 41.171 ;
     RECT  53.376 40.307 54.288 40.789 ;
     RECT  44.472 40.403 45.6 42.803 ;
     RECT  25.128 40.405 26.352 41.651 ;
     RECT  13.512 40.595 15.408 41.605 ;
     RECT  30.504 40.693 31.728 42.227 ;
     RECT  51.864 40.789 54.288 41.749 ;
     RECT  35.112 40.883 35.208 41.893 ;
     RECT  26.376 40.933 27.408 41.651 ;
     RECT  27.432 40.933 28.464 41.699 ;
     RECT  21.384 40.981 22.752 45.059 ;
     RECT  22.776 40.981 24 46.787 ;
     RECT  46.872 41.171 48.384 41.605 ;
     RECT  49.848 41.221 51 42.709 ;
     RECT  40.512 41.507 41.904 42.995 ;
     RECT  32.424 41.509 33.936 41.989 ;
     RECT  15.864 41.557 17.328 41.651 ;
     RECT  17.352 41.557 18.48 42.133 ;
     RECT  13.512 41.605 14.832 41.747 ;
     RECT  47.4 41.605 48.384 41.651 ;
     RECT  3.432 41.651 4.8 42.227 ;
     RECT  5.784 41.651 6.864 43.571 ;
     RECT  47.4 41.651 48.528 42.611 ;
     RECT  15.072 41.747 15.408 42.757 ;
     RECT  37.512 41.749 38.784 42.179 ;
     RECT  38.808 41.749 40.2 42.995 ;
     RECT  51.864 41.749 52.896 43.283 ;
     RECT  52.92 41.749 54.288 43.237 ;
     RECT  55.272 41.939 56.4 44.437 ;
     RECT  47.4 42.611 48.96 43.813 ;
     RECT  17.352 42.803 18.6 47.315 ;
     RECT  44.376 42.803 45.6 43.333 ;
     RECT  39.312 42.995 40.2 43.525 ;
     RECT  48.984 43.283 50.064 43.955 ;
     RECT  51.312 43.283 52.896 44.051 ;
     RECT  35.208 43.333 36.528 44.101 ;
     RECT  44.376 43.333 45.408 47.845 ;
     RECT  33.336 43.523 34.8 43.859 ;
     RECT  5.784 43.571 7.008 46.069 ;
     RECT  47.4 43.813 48.912 44.245 ;
     RECT  48.936 43.955 50.064 44.195 ;
     RECT  43.008 44.003 43.392 44.965 ;
     RECT  51.312 44.051 53.28 44.389 ;
     RECT  48.936 44.195 50.88 45.011 ;
     RECT  30.408 44.197 31.824 46.259 ;
     RECT  11.736 44.389 13.2 45.347 ;
     RECT  51.864 44.389 53.28 45.299 ;
     RECT  55.368 44.437 56.4 47.749 ;
     RECT  39.312 44.579 39.36 45.877 ;
     RECT  4.392 44.723 5.76 46.213 ;
     RECT  50.208 45.011 50.88 45.253 ;
     RECT  51.312 45.299 53.28 45.781 ;
     RECT  18.912 45.397 20.112 46.309 ;
     RECT  51.312 45.781 52.464 46.787 ;
     RECT  24.408 45.923 25.44 46.211 ;
     RECT  5.928 46.069 7.008 46.595 ;
     RECT  18.912 46.309 20.016 48.131 ;
     RECT  5.784 46.595 7.008 49.189 ;
     RECT  8.112 46.645 9.552 47.797 ;
     RECT  28.128 46.787 29.088 47.845 ;
     RECT  32.424 46.787 32.76 47.845 ;
     RECT  36.168 46.787 36.456 47.269 ;
     RECT  51.312 46.787 53.136 48.229 ;
     RECT  53.208 46.787 54.192 48.613 ;
     RECT  4.392 46.931 5.76 48.179 ;
     RECT  36.168 47.269 37.248 47.747 ;
     RECT  17.16 47.315 18.6 48.997 ;
     RECT  9.864 47.317 10.992 49.091 ;
     RECT  47.832 47.411 47.928 47.701 ;
     RECT  35.112 47.651 36.144 48.659 ;
     RECT  46.44 47.651 47.472 48.709 ;
     RECT  47.832 47.701 49.296 47.797 ;
     RECT  36.168 47.747 37.272 47.893 ;
     RECT  47.832 47.797 49.008 47.939 ;
     RECT  24.408 47.845 25.92 48.659 ;
     RECT  27.672 47.845 29.088 47.939 ;
     RECT  36.888 47.893 37.272 48.229 ;
     RECT  47.832 47.939 49.296 48.899 ;
     RECT  54.216 47.939 55.2 48.659 ;
     RECT  36.888 48.229 38.352 48.997 ;
     RECT  51.312 48.229 52.416 49.043 ;
     RECT  54.216 48.659 55.344 51.347 ;
     RECT  47.832 48.899 47.88 48.949 ;
     RECT  37.08 48.997 38.352 49.139 ;
     RECT  51.312 49.043 53.136 50.245 ;
     RECT  11.016 49.477 12.24 50.291 ;
     RECT  43.464 49.571 44.688 51.109 ;
     RECT  13.512 49.811 13.848 51.205 ;
     RECT  51.312 50.245 52.416 51.349 ;
     RECT  38.76 50.677 40.2 53.269 ;
     RECT  40.512 50.725 41.808 53.507 ;
     RECT  41.832 50.725 43.344 51.155 ;
     RECT  46.632 50.819 47.616 52.693 ;
     RECT  43.56 51.109 44.688 51.733 ;
     RECT  13.512 51.205 14.832 52.499 ;
     RECT  32.424 51.251 33.048 52.261 ;
     RECT  17.16 51.299 18.192 53.075 ;
     RECT  49.464 51.347 50.736 52.739 ;
     RECT  54.912 51.347 55.344 51.637 ;
     RECT  22.248 51.637 23.664 52.211 ;
     RECT  52.2 51.923 53.232 54.083 ;
     RECT  25.944 52.211 27.024 53.123 ;
     RECT  32.424 52.261 33.552 52.405 ;
     RECT  33.576 52.261 34.8 56.773 ;
     RECT  13.512 52.499 13.608 53.029 ;
     RECT  55.416 52.595 56.4 53.315 ;
     RECT  17.16 53.075 18.24 54.179 ;
     RECT  38.76 53.269 39.888 53.363 ;
     RECT  55.128 53.315 56.4 55.955 ;
     RECT  5.064 53.363 6.096 55.331 ;
     RECT  51.816 54.083 53.232 54.179 ;
     RECT  43.896 54.179 44.976 61.667 ;
     RECT  32.424 54.611 33.552 57.059 ;
     RECT  27.72 55.237 28.848 55.909 ;
     RECT  5.064 55.331 6.528 58.163 ;
     RECT  35.112 55.715 35.208 55.813 ;
     RECT  35.112 55.813 36.48 56.531 ;
     RECT  49.464 55.813 50.88 57.059 ;
     RECT  6.552 55.907 7.68 56.531 ;
     RECT  45.912 55.907 47.04 57.349 ;
     RECT  28.248 55.955 29.4 57.635 ;
     RECT  55.032 55.955 56.4 56.531 ;
     RECT  6.552 56.531 7.8 58.163 ;
     RECT  48.264 56.533 49.44 57.059 ;
     RECT  8.112 56.581 9.552 57.541 ;
     RECT  22.824 56.869 24 57.059 ;
     RECT  39.144 56.965 40.2 59.267 ;
     RECT  53.016 56.965 54.336 57.635 ;
     RECT  8.28 57.541 9.552 57.587 ;
     RECT  24.312 57.541 25.824 60.755 ;
     RECT  47.064 57.875 48.24 58.019 ;
     RECT  47.016 58.019 48.24 58.739 ;
     RECT  17.208 58.501 18.336 59.315 ;
     RECT  45.912 58.691 46.992 59.843 ;
     RECT  47.016 58.739 48.216 59.029 ;
     RECT  47.016 59.029 48.192 59.797 ;
     RECT  25.848 59.221 26.88 59.507 ;
     RECT  17.184 59.315 18.336 59.749 ;
     RECT  13.512 59.749 14.832 60.661 ;
     RECT  17.16 59.749 18.336 60.277 ;
     RECT  42.744 59.797 43.872 60.661 ;
     RECT  45.912 59.843 47.28 60.035 ;
     RECT  17.16 60.277 18.24 60.563 ;
     RECT  17.16 60.563 18.6 62.051 ;
     RECT  35.112 60.661 36.432 62.147 ;
     RECT  42.744 60.661 43.776 60.707 ;
     RECT  40.512 60.949 41.616 61.811 ;
  END
END ot_hgi_coll_pring_static_state_capture_lane
END LIBRARY
